VERSION 5.7 ;
BUSBITCHARS "[]" ;
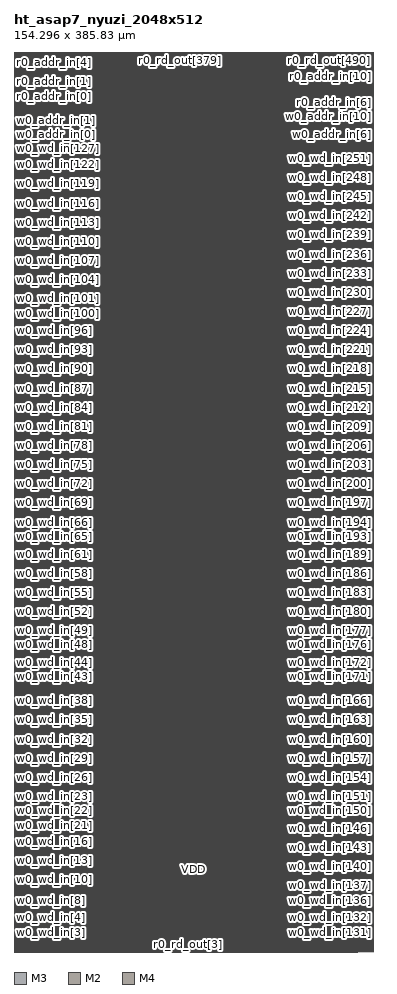
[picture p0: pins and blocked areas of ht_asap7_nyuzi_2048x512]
MACRO ht_asap7_nyuzi_2048x512
  FOREIGN ht_asap7_nyuzi_2048x512 0 0 ;
  SYMMETRY X Y R90 ;
  SIZE 154.296 BY 385.830 ;
  CLASS BLOCK ;
  PIN w0_wd_in[0]
    DIRECTION INPUT ;
    USE SIGNAL ;
    SHAPE ABUTMENT ;
    PORT
      LAYER M3 ;
      RECT 0.000 0.276 0.072 0.300 ;
    END
  END w0_wd_in[0]
  PIN w0_wd_in[1]
    DIRECTION INPUT ;
    USE SIGNAL ;
    SHAPE ABUTMENT ;
    PORT
      LAYER M3 ;
      RECT 0.000 3.012 0.072 3.036 ;
    END
  END w0_wd_in[1]
  PIN w0_wd_in[2]
    DIRECTION INPUT ;
    USE SIGNAL ;
    SHAPE ABUTMENT ;
    PORT
      LAYER M3 ;
      RECT 0.000 5.748 0.072 5.772 ;
    END
  END w0_wd_in[2]
  PIN w0_wd_in[3]
    DIRECTION INPUT ;
    USE SIGNAL ;
    SHAPE ABUTMENT ;
    PORT
      LAYER M3 ;
      RECT 0.000 8.484 0.072 8.508 ;
    END
  END w0_wd_in[3]
  PIN w0_wd_in[4]
    DIRECTION INPUT ;
    USE SIGNAL ;
    SHAPE ABUTMENT ;
    PORT
      LAYER M3 ;
      RECT 0.000 11.220 0.072 11.244 ;
    END
  END w0_wd_in[4]
  PIN w0_wd_in[5]
    DIRECTION INPUT ;
    USE SIGNAL ;
    SHAPE ABUTMENT ;
    PORT
      LAYER M3 ;
      RECT 0.000 13.956 0.072 13.980 ;
    END
  END w0_wd_in[5]
  PIN w0_wd_in[6]
    DIRECTION INPUT ;
    USE SIGNAL ;
    SHAPE ABUTMENT ;
    PORT
      LAYER M3 ;
      RECT 0.000 16.692 0.072 16.716 ;
    END
  END w0_wd_in[6]
  PIN w0_wd_in[7]
    DIRECTION INPUT ;
    USE SIGNAL ;
    SHAPE ABUTMENT ;
    PORT
      LAYER M3 ;
      RECT 0.000 19.428 0.072 19.452 ;
    END
  END w0_wd_in[7]
  PIN w0_wd_in[8]
    DIRECTION INPUT ;
    USE SIGNAL ;
    SHAPE ABUTMENT ;
    PORT
      LAYER M3 ;
      RECT 0.000 22.164 0.072 22.188 ;
    END
  END w0_wd_in[8]
  PIN w0_wd_in[9]
    DIRECTION INPUT ;
    USE SIGNAL ;
    SHAPE ABUTMENT ;
    PORT
      LAYER M3 ;
      RECT 0.000 24.900 0.072 24.924 ;
    END
  END w0_wd_in[9]
  PIN w0_wd_in[10]
    DIRECTION INPUT ;
    USE SIGNAL ;
    SHAPE ABUTMENT ;
    PORT
      LAYER M3 ;
      RECT 0.000 27.636 0.072 27.660 ;
    END
  END w0_wd_in[10]
  PIN w0_wd_in[11]
    DIRECTION INPUT ;
    USE SIGNAL ;
    SHAPE ABUTMENT ;
    PORT
      LAYER M3 ;
      RECT 0.000 30.372 0.072 30.396 ;
    END
  END w0_wd_in[11]
  PIN w0_wd_in[12]
    DIRECTION INPUT ;
    USE SIGNAL ;
    SHAPE ABUTMENT ;
    PORT
      LAYER M3 ;
      RECT 0.000 33.108 0.072 33.132 ;
    END
  END w0_wd_in[12]
  PIN w0_wd_in[13]
    DIRECTION INPUT ;
    USE SIGNAL ;
    SHAPE ABUTMENT ;
    PORT
      LAYER M3 ;
      RECT 0.000 35.844 0.072 35.868 ;
    END
  END w0_wd_in[13]
  PIN w0_wd_in[14]
    DIRECTION INPUT ;
    USE SIGNAL ;
    SHAPE ABUTMENT ;
    PORT
      LAYER M3 ;
      RECT 0.000 38.580 0.072 38.604 ;
    END
  END w0_wd_in[14]
  PIN w0_wd_in[15]
    DIRECTION INPUT ;
    USE SIGNAL ;
    SHAPE ABUTMENT ;
    PORT
      LAYER M3 ;
      RECT 0.000 41.316 0.072 41.340 ;
    END
  END w0_wd_in[15]
  PIN w0_wd_in[16]
    DIRECTION INPUT ;
    USE SIGNAL ;
    SHAPE ABUTMENT ;
    PORT
      LAYER M3 ;
      RECT 0.000 44.052 0.072 44.076 ;
    END
  END w0_wd_in[16]
  PIN w0_wd_in[17]
    DIRECTION INPUT ;
    USE SIGNAL ;
    SHAPE ABUTMENT ;
    PORT
      LAYER M3 ;
      RECT 0.000 46.788 0.072 46.812 ;
    END
  END w0_wd_in[17]
  PIN w0_wd_in[18]
    DIRECTION INPUT ;
    USE SIGNAL ;
    SHAPE ABUTMENT ;
    PORT
      LAYER M3 ;
      RECT 0.000 49.524 0.072 49.548 ;
    END
  END w0_wd_in[18]
  PIN w0_wd_in[19]
    DIRECTION INPUT ;
    USE SIGNAL ;
    SHAPE ABUTMENT ;
    PORT
      LAYER M3 ;
      RECT 0.000 52.260 0.072 52.284 ;
    END
  END w0_wd_in[19]
  PIN w0_wd_in[20]
    DIRECTION INPUT ;
    USE SIGNAL ;
    SHAPE ABUTMENT ;
    PORT
      LAYER M3 ;
      RECT 0.000 54.996 0.072 55.020 ;
    END
  END w0_wd_in[20]
  PIN w0_wd_in[21]
    DIRECTION INPUT ;
    USE SIGNAL ;
    SHAPE ABUTMENT ;
    PORT
      LAYER M3 ;
      RECT 0.000 57.732 0.072 57.756 ;
    END
  END w0_wd_in[21]
  PIN w0_wd_in[22]
    DIRECTION INPUT ;
    USE SIGNAL ;
    SHAPE ABUTMENT ;
    PORT
      LAYER M3 ;
      RECT 0.000 60.468 0.072 60.492 ;
    END
  END w0_wd_in[22]
  PIN w0_wd_in[23]
    DIRECTION INPUT ;
    USE SIGNAL ;
    SHAPE ABUTMENT ;
    PORT
      LAYER M3 ;
      RECT 0.000 63.204 0.072 63.228 ;
    END
  END w0_wd_in[23]
  PIN w0_wd_in[24]
    DIRECTION INPUT ;
    USE SIGNAL ;
    SHAPE ABUTMENT ;
    PORT
      LAYER M3 ;
      RECT 0.000 65.940 0.072 65.964 ;
    END
  END w0_wd_in[24]
  PIN w0_wd_in[25]
    DIRECTION INPUT ;
    USE SIGNAL ;
    SHAPE ABUTMENT ;
    PORT
      LAYER M3 ;
      RECT 0.000 68.676 0.072 68.700 ;
    END
  END w0_wd_in[25]
  PIN w0_wd_in[26]
    DIRECTION INPUT ;
    USE SIGNAL ;
    SHAPE ABUTMENT ;
    PORT
      LAYER M3 ;
      RECT 0.000 71.412 0.072 71.436 ;
    END
  END w0_wd_in[26]
  PIN w0_wd_in[27]
    DIRECTION INPUT ;
    USE SIGNAL ;
    SHAPE ABUTMENT ;
    PORT
      LAYER M3 ;
      RECT 0.000 74.148 0.072 74.172 ;
    END
  END w0_wd_in[27]
  PIN w0_wd_in[28]
    DIRECTION INPUT ;
    USE SIGNAL ;
    SHAPE ABUTMENT ;
    PORT
      LAYER M3 ;
      RECT 0.000 76.884 0.072 76.908 ;
    END
  END w0_wd_in[28]
  PIN w0_wd_in[29]
    DIRECTION INPUT ;
    USE SIGNAL ;
    SHAPE ABUTMENT ;
    PORT
      LAYER M3 ;
      RECT 0.000 79.620 0.072 79.644 ;
    END
  END w0_wd_in[29]
  PIN w0_wd_in[30]
    DIRECTION INPUT ;
    USE SIGNAL ;
    SHAPE ABUTMENT ;
    PORT
      LAYER M3 ;
      RECT 0.000 82.356 0.072 82.380 ;
    END
  END w0_wd_in[30]
  PIN w0_wd_in[31]
    DIRECTION INPUT ;
    USE SIGNAL ;
    SHAPE ABUTMENT ;
    PORT
      LAYER M3 ;
      RECT 0.000 85.092 0.072 85.116 ;
    END
  END w0_wd_in[31]
  PIN w0_wd_in[32]
    DIRECTION INPUT ;
    USE SIGNAL ;
    SHAPE ABUTMENT ;
    PORT
      LAYER M3 ;
      RECT 0.000 87.828 0.072 87.852 ;
    END
  END w0_wd_in[32]
  PIN w0_wd_in[33]
    DIRECTION INPUT ;
    USE SIGNAL ;
    SHAPE ABUTMENT ;
    PORT
      LAYER M3 ;
      RECT 0.000 90.564 0.072 90.588 ;
    END
  END w0_wd_in[33]
  PIN w0_wd_in[34]
    DIRECTION INPUT ;
    USE SIGNAL ;
    SHAPE ABUTMENT ;
    PORT
      LAYER M3 ;
      RECT 0.000 93.300 0.072 93.324 ;
    END
  END w0_wd_in[34]
  PIN w0_wd_in[35]
    DIRECTION INPUT ;
    USE SIGNAL ;
    SHAPE ABUTMENT ;
    PORT
      LAYER M3 ;
      RECT 0.000 96.036 0.072 96.060 ;
    END
  END w0_wd_in[35]
  PIN w0_wd_in[36]
    DIRECTION INPUT ;
    USE SIGNAL ;
    SHAPE ABUTMENT ;
    PORT
      LAYER M3 ;
      RECT 0.000 98.772 0.072 98.796 ;
    END
  END w0_wd_in[36]
  PIN w0_wd_in[37]
    DIRECTION INPUT ;
    USE SIGNAL ;
    SHAPE ABUTMENT ;
    PORT
      LAYER M3 ;
      RECT 0.000 101.508 0.072 101.532 ;
    END
  END w0_wd_in[37]
  PIN w0_wd_in[38]
    DIRECTION INPUT ;
    USE SIGNAL ;
    SHAPE ABUTMENT ;
    PORT
      LAYER M3 ;
      RECT 0.000 104.244 0.072 104.268 ;
    END
  END w0_wd_in[38]
  PIN w0_wd_in[39]
    DIRECTION INPUT ;
    USE SIGNAL ;
    SHAPE ABUTMENT ;
    PORT
      LAYER M3 ;
      RECT 0.000 106.980 0.072 107.004 ;
    END
  END w0_wd_in[39]
  PIN w0_wd_in[40]
    DIRECTION INPUT ;
    USE SIGNAL ;
    SHAPE ABUTMENT ;
    PORT
      LAYER M3 ;
      RECT 0.000 109.716 0.072 109.740 ;
    END
  END w0_wd_in[40]
  PIN w0_wd_in[41]
    DIRECTION INPUT ;
    USE SIGNAL ;
    SHAPE ABUTMENT ;
    PORT
      LAYER M3 ;
      RECT 0.000 112.452 0.072 112.476 ;
    END
  END w0_wd_in[41]
  PIN w0_wd_in[42]
    DIRECTION INPUT ;
    USE SIGNAL ;
    SHAPE ABUTMENT ;
    PORT
      LAYER M3 ;
      RECT 0.000 115.188 0.072 115.212 ;
    END
  END w0_wd_in[42]
  PIN w0_wd_in[43]
    DIRECTION INPUT ;
    USE SIGNAL ;
    SHAPE ABUTMENT ;
    PORT
      LAYER M3 ;
      RECT 0.000 117.924 0.072 117.948 ;
    END
  END w0_wd_in[43]
  PIN w0_wd_in[44]
    DIRECTION INPUT ;
    USE SIGNAL ;
    SHAPE ABUTMENT ;
    PORT
      LAYER M3 ;
      RECT 0.000 120.660 0.072 120.684 ;
    END
  END w0_wd_in[44]
  PIN w0_wd_in[45]
    DIRECTION INPUT ;
    USE SIGNAL ;
    SHAPE ABUTMENT ;
    PORT
      LAYER M3 ;
      RECT 0.000 123.396 0.072 123.420 ;
    END
  END w0_wd_in[45]
  PIN w0_wd_in[46]
    DIRECTION INPUT ;
    USE SIGNAL ;
    SHAPE ABUTMENT ;
    PORT
      LAYER M3 ;
      RECT 0.000 126.132 0.072 126.156 ;
    END
  END w0_wd_in[46]
  PIN w0_wd_in[47]
    DIRECTION INPUT ;
    USE SIGNAL ;
    SHAPE ABUTMENT ;
    PORT
      LAYER M3 ;
      RECT 0.000 128.868 0.072 128.892 ;
    END
  END w0_wd_in[47]
  PIN w0_wd_in[48]
    DIRECTION INPUT ;
    USE SIGNAL ;
    SHAPE ABUTMENT ;
    PORT
      LAYER M3 ;
      RECT 0.000 131.604 0.072 131.628 ;
    END
  END w0_wd_in[48]
  PIN w0_wd_in[49]
    DIRECTION INPUT ;
    USE SIGNAL ;
    SHAPE ABUTMENT ;
    PORT
      LAYER M3 ;
      RECT 0.000 134.340 0.072 134.364 ;
    END
  END w0_wd_in[49]
  PIN w0_wd_in[50]
    DIRECTION INPUT ;
    USE SIGNAL ;
    SHAPE ABUTMENT ;
    PORT
      LAYER M3 ;
      RECT 0.000 137.076 0.072 137.100 ;
    END
  END w0_wd_in[50]
  PIN w0_wd_in[51]
    DIRECTION INPUT ;
    USE SIGNAL ;
    SHAPE ABUTMENT ;
    PORT
      LAYER M3 ;
      RECT 0.000 139.812 0.072 139.836 ;
    END
  END w0_wd_in[51]
  PIN w0_wd_in[52]
    DIRECTION INPUT ;
    USE SIGNAL ;
    SHAPE ABUTMENT ;
    PORT
      LAYER M3 ;
      RECT 0.000 142.548 0.072 142.572 ;
    END
  END w0_wd_in[52]
  PIN w0_wd_in[53]
    DIRECTION INPUT ;
    USE SIGNAL ;
    SHAPE ABUTMENT ;
    PORT
      LAYER M3 ;
      RECT 0.000 145.284 0.072 145.308 ;
    END
  END w0_wd_in[53]
  PIN w0_wd_in[54]
    DIRECTION INPUT ;
    USE SIGNAL ;
    SHAPE ABUTMENT ;
    PORT
      LAYER M3 ;
      RECT 0.000 148.020 0.072 148.044 ;
    END
  END w0_wd_in[54]
  PIN w0_wd_in[55]
    DIRECTION INPUT ;
    USE SIGNAL ;
    SHAPE ABUTMENT ;
    PORT
      LAYER M3 ;
      RECT 0.000 150.756 0.072 150.780 ;
    END
  END w0_wd_in[55]
  PIN w0_wd_in[56]
    DIRECTION INPUT ;
    USE SIGNAL ;
    SHAPE ABUTMENT ;
    PORT
      LAYER M3 ;
      RECT 0.000 153.492 0.072 153.516 ;
    END
  END w0_wd_in[56]
  PIN w0_wd_in[57]
    DIRECTION INPUT ;
    USE SIGNAL ;
    SHAPE ABUTMENT ;
    PORT
      LAYER M3 ;
      RECT 0.000 156.228 0.072 156.252 ;
    END
  END w0_wd_in[57]
  PIN w0_wd_in[58]
    DIRECTION INPUT ;
    USE SIGNAL ;
    SHAPE ABUTMENT ;
    PORT
      LAYER M3 ;
      RECT 0.000 158.964 0.072 158.988 ;
    END
  END w0_wd_in[58]
  PIN w0_wd_in[59]
    DIRECTION INPUT ;
    USE SIGNAL ;
    SHAPE ABUTMENT ;
    PORT
      LAYER M3 ;
      RECT 0.000 161.700 0.072 161.724 ;
    END
  END w0_wd_in[59]
  PIN w0_wd_in[60]
    DIRECTION INPUT ;
    USE SIGNAL ;
    SHAPE ABUTMENT ;
    PORT
      LAYER M3 ;
      RECT 0.000 164.436 0.072 164.460 ;
    END
  END w0_wd_in[60]
  PIN w0_wd_in[61]
    DIRECTION INPUT ;
    USE SIGNAL ;
    SHAPE ABUTMENT ;
    PORT
      LAYER M3 ;
      RECT 0.000 167.172 0.072 167.196 ;
    END
  END w0_wd_in[61]
  PIN w0_wd_in[62]
    DIRECTION INPUT ;
    USE SIGNAL ;
    SHAPE ABUTMENT ;
    PORT
      LAYER M3 ;
      RECT 0.000 169.908 0.072 169.932 ;
    END
  END w0_wd_in[62]
  PIN w0_wd_in[63]
    DIRECTION INPUT ;
    USE SIGNAL ;
    SHAPE ABUTMENT ;
    PORT
      LAYER M3 ;
      RECT 0.000 172.644 0.072 172.668 ;
    END
  END w0_wd_in[63]
  PIN w0_wd_in[64]
    DIRECTION INPUT ;
    USE SIGNAL ;
    SHAPE ABUTMENT ;
    PORT
      LAYER M3 ;
      RECT 0.000 175.380 0.072 175.404 ;
    END
  END w0_wd_in[64]
  PIN w0_wd_in[65]
    DIRECTION INPUT ;
    USE SIGNAL ;
    SHAPE ABUTMENT ;
    PORT
      LAYER M3 ;
      RECT 0.000 178.116 0.072 178.140 ;
    END
  END w0_wd_in[65]
  PIN w0_wd_in[66]
    DIRECTION INPUT ;
    USE SIGNAL ;
    SHAPE ABUTMENT ;
    PORT
      LAYER M3 ;
      RECT 0.000 180.852 0.072 180.876 ;
    END
  END w0_wd_in[66]
  PIN w0_wd_in[67]
    DIRECTION INPUT ;
    USE SIGNAL ;
    SHAPE ABUTMENT ;
    PORT
      LAYER M3 ;
      RECT 0.000 183.588 0.072 183.612 ;
    END
  END w0_wd_in[67]
  PIN w0_wd_in[68]
    DIRECTION INPUT ;
    USE SIGNAL ;
    SHAPE ABUTMENT ;
    PORT
      LAYER M3 ;
      RECT 0.000 186.324 0.072 186.348 ;
    END
  END w0_wd_in[68]
  PIN w0_wd_in[69]
    DIRECTION INPUT ;
    USE SIGNAL ;
    SHAPE ABUTMENT ;
    PORT
      LAYER M3 ;
      RECT 0.000 189.060 0.072 189.084 ;
    END
  END w0_wd_in[69]
  PIN w0_wd_in[70]
    DIRECTION INPUT ;
    USE SIGNAL ;
    SHAPE ABUTMENT ;
    PORT
      LAYER M3 ;
      RECT 0.000 191.796 0.072 191.820 ;
    END
  END w0_wd_in[70]
  PIN w0_wd_in[71]
    DIRECTION INPUT ;
    USE SIGNAL ;
    SHAPE ABUTMENT ;
    PORT
      LAYER M3 ;
      RECT 0.000 194.532 0.072 194.556 ;
    END
  END w0_wd_in[71]
  PIN w0_wd_in[72]
    DIRECTION INPUT ;
    USE SIGNAL ;
    SHAPE ABUTMENT ;
    PORT
      LAYER M3 ;
      RECT 0.000 197.268 0.072 197.292 ;
    END
  END w0_wd_in[72]
  PIN w0_wd_in[73]
    DIRECTION INPUT ;
    USE SIGNAL ;
    SHAPE ABUTMENT ;
    PORT
      LAYER M3 ;
      RECT 0.000 200.004 0.072 200.028 ;
    END
  END w0_wd_in[73]
  PIN w0_wd_in[74]
    DIRECTION INPUT ;
    USE SIGNAL ;
    SHAPE ABUTMENT ;
    PORT
      LAYER M3 ;
      RECT 0.000 202.740 0.072 202.764 ;
    END
  END w0_wd_in[74]
  PIN w0_wd_in[75]
    DIRECTION INPUT ;
    USE SIGNAL ;
    SHAPE ABUTMENT ;
    PORT
      LAYER M3 ;
      RECT 0.000 205.476 0.072 205.500 ;
    END
  END w0_wd_in[75]
  PIN w0_wd_in[76]
    DIRECTION INPUT ;
    USE SIGNAL ;
    SHAPE ABUTMENT ;
    PORT
      LAYER M3 ;
      RECT 0.000 208.212 0.072 208.236 ;
    END
  END w0_wd_in[76]
  PIN w0_wd_in[77]
    DIRECTION INPUT ;
    USE SIGNAL ;
    SHAPE ABUTMENT ;
    PORT
      LAYER M3 ;
      RECT 0.000 210.948 0.072 210.972 ;
    END
  END w0_wd_in[77]
  PIN w0_wd_in[78]
    DIRECTION INPUT ;
    USE SIGNAL ;
    SHAPE ABUTMENT ;
    PORT
      LAYER M3 ;
      RECT 0.000 213.684 0.072 213.708 ;
    END
  END w0_wd_in[78]
  PIN w0_wd_in[79]
    DIRECTION INPUT ;
    USE SIGNAL ;
    SHAPE ABUTMENT ;
    PORT
      LAYER M3 ;
      RECT 0.000 216.420 0.072 216.444 ;
    END
  END w0_wd_in[79]
  PIN w0_wd_in[80]
    DIRECTION INPUT ;
    USE SIGNAL ;
    SHAPE ABUTMENT ;
    PORT
      LAYER M3 ;
      RECT 0.000 219.156 0.072 219.180 ;
    END
  END w0_wd_in[80]
  PIN w0_wd_in[81]
    DIRECTION INPUT ;
    USE SIGNAL ;
    SHAPE ABUTMENT ;
    PORT
      LAYER M3 ;
      RECT 0.000 221.892 0.072 221.916 ;
    END
  END w0_wd_in[81]
  PIN w0_wd_in[82]
    DIRECTION INPUT ;
    USE SIGNAL ;
    SHAPE ABUTMENT ;
    PORT
      LAYER M3 ;
      RECT 0.000 224.628 0.072 224.652 ;
    END
  END w0_wd_in[82]
  PIN w0_wd_in[83]
    DIRECTION INPUT ;
    USE SIGNAL ;
    SHAPE ABUTMENT ;
    PORT
      LAYER M3 ;
      RECT 0.000 227.364 0.072 227.388 ;
    END
  END w0_wd_in[83]
  PIN w0_wd_in[84]
    DIRECTION INPUT ;
    USE SIGNAL ;
    SHAPE ABUTMENT ;
    PORT
      LAYER M3 ;
      RECT 0.000 230.100 0.072 230.124 ;
    END
  END w0_wd_in[84]
  PIN w0_wd_in[85]
    DIRECTION INPUT ;
    USE SIGNAL ;
    SHAPE ABUTMENT ;
    PORT
      LAYER M3 ;
      RECT 0.000 232.836 0.072 232.860 ;
    END
  END w0_wd_in[85]
  PIN w0_wd_in[86]
    DIRECTION INPUT ;
    USE SIGNAL ;
    SHAPE ABUTMENT ;
    PORT
      LAYER M3 ;
      RECT 0.000 235.572 0.072 235.596 ;
    END
  END w0_wd_in[86]
  PIN w0_wd_in[87]
    DIRECTION INPUT ;
    USE SIGNAL ;
    SHAPE ABUTMENT ;
    PORT
      LAYER M3 ;
      RECT 0.000 238.308 0.072 238.332 ;
    END
  END w0_wd_in[87]
  PIN w0_wd_in[88]
    DIRECTION INPUT ;
    USE SIGNAL ;
    SHAPE ABUTMENT ;
    PORT
      LAYER M3 ;
      RECT 0.000 241.044 0.072 241.068 ;
    END
  END w0_wd_in[88]
  PIN w0_wd_in[89]
    DIRECTION INPUT ;
    USE SIGNAL ;
    SHAPE ABUTMENT ;
    PORT
      LAYER M3 ;
      RECT 0.000 243.780 0.072 243.804 ;
    END
  END w0_wd_in[89]
  PIN w0_wd_in[90]
    DIRECTION INPUT ;
    USE SIGNAL ;
    SHAPE ABUTMENT ;
    PORT
      LAYER M3 ;
      RECT 0.000 246.516 0.072 246.540 ;
    END
  END w0_wd_in[90]
  PIN w0_wd_in[91]
    DIRECTION INPUT ;
    USE SIGNAL ;
    SHAPE ABUTMENT ;
    PORT
      LAYER M3 ;
      RECT 0.000 249.252 0.072 249.276 ;
    END
  END w0_wd_in[91]
  PIN w0_wd_in[92]
    DIRECTION INPUT ;
    USE SIGNAL ;
    SHAPE ABUTMENT ;
    PORT
      LAYER M3 ;
      RECT 0.000 251.988 0.072 252.012 ;
    END
  END w0_wd_in[92]
  PIN w0_wd_in[93]
    DIRECTION INPUT ;
    USE SIGNAL ;
    SHAPE ABUTMENT ;
    PORT
      LAYER M3 ;
      RECT 0.000 254.724 0.072 254.748 ;
    END
  END w0_wd_in[93]
  PIN w0_wd_in[94]
    DIRECTION INPUT ;
    USE SIGNAL ;
    SHAPE ABUTMENT ;
    PORT
      LAYER M3 ;
      RECT 0.000 257.460 0.072 257.484 ;
    END
  END w0_wd_in[94]
  PIN w0_wd_in[95]
    DIRECTION INPUT ;
    USE SIGNAL ;
    SHAPE ABUTMENT ;
    PORT
      LAYER M3 ;
      RECT 0.000 260.196 0.072 260.220 ;
    END
  END w0_wd_in[95]
  PIN w0_wd_in[96]
    DIRECTION INPUT ;
    USE SIGNAL ;
    SHAPE ABUTMENT ;
    PORT
      LAYER M3 ;
      RECT 0.000 262.932 0.072 262.956 ;
    END
  END w0_wd_in[96]
  PIN w0_wd_in[97]
    DIRECTION INPUT ;
    USE SIGNAL ;
    SHAPE ABUTMENT ;
    PORT
      LAYER M3 ;
      RECT 0.000 265.668 0.072 265.692 ;
    END
  END w0_wd_in[97]
  PIN w0_wd_in[98]
    DIRECTION INPUT ;
    USE SIGNAL ;
    SHAPE ABUTMENT ;
    PORT
      LAYER M3 ;
      RECT 0.000 268.404 0.072 268.428 ;
    END
  END w0_wd_in[98]
  PIN w0_wd_in[99]
    DIRECTION INPUT ;
    USE SIGNAL ;
    SHAPE ABUTMENT ;
    PORT
      LAYER M3 ;
      RECT 0.000 271.140 0.072 271.164 ;
    END
  END w0_wd_in[99]
  PIN w0_wd_in[100]
    DIRECTION INPUT ;
    USE SIGNAL ;
    SHAPE ABUTMENT ;
    PORT
      LAYER M3 ;
      RECT 0.000 273.876 0.072 273.900 ;
    END
  END w0_wd_in[100]
  PIN w0_wd_in[101]
    DIRECTION INPUT ;
    USE SIGNAL ;
    SHAPE ABUTMENT ;
    PORT
      LAYER M3 ;
      RECT 0.000 276.612 0.072 276.636 ;
    END
  END w0_wd_in[101]
  PIN w0_wd_in[102]
    DIRECTION INPUT ;
    USE SIGNAL ;
    SHAPE ABUTMENT ;
    PORT
      LAYER M3 ;
      RECT 0.000 279.348 0.072 279.372 ;
    END
  END w0_wd_in[102]
  PIN w0_wd_in[103]
    DIRECTION INPUT ;
    USE SIGNAL ;
    SHAPE ABUTMENT ;
    PORT
      LAYER M3 ;
      RECT 0.000 282.084 0.072 282.108 ;
    END
  END w0_wd_in[103]
  PIN w0_wd_in[104]
    DIRECTION INPUT ;
    USE SIGNAL ;
    SHAPE ABUTMENT ;
    PORT
      LAYER M3 ;
      RECT 0.000 284.820 0.072 284.844 ;
    END
  END w0_wd_in[104]
  PIN w0_wd_in[105]
    DIRECTION INPUT ;
    USE SIGNAL ;
    SHAPE ABUTMENT ;
    PORT
      LAYER M3 ;
      RECT 0.000 287.556 0.072 287.580 ;
    END
  END w0_wd_in[105]
  PIN w0_wd_in[106]
    DIRECTION INPUT ;
    USE SIGNAL ;
    SHAPE ABUTMENT ;
    PORT
      LAYER M3 ;
      RECT 0.000 290.292 0.072 290.316 ;
    END
  END w0_wd_in[106]
  PIN w0_wd_in[107]
    DIRECTION INPUT ;
    USE SIGNAL ;
    SHAPE ABUTMENT ;
    PORT
      LAYER M3 ;
      RECT 0.000 293.028 0.072 293.052 ;
    END
  END w0_wd_in[107]
  PIN w0_wd_in[108]
    DIRECTION INPUT ;
    USE SIGNAL ;
    SHAPE ABUTMENT ;
    PORT
      LAYER M3 ;
      RECT 0.000 295.764 0.072 295.788 ;
    END
  END w0_wd_in[108]
  PIN w0_wd_in[109]
    DIRECTION INPUT ;
    USE SIGNAL ;
    SHAPE ABUTMENT ;
    PORT
      LAYER M3 ;
      RECT 0.000 298.500 0.072 298.524 ;
    END
  END w0_wd_in[109]
  PIN w0_wd_in[110]
    DIRECTION INPUT ;
    USE SIGNAL ;
    SHAPE ABUTMENT ;
    PORT
      LAYER M3 ;
      RECT 0.000 301.236 0.072 301.260 ;
    END
  END w0_wd_in[110]
  PIN w0_wd_in[111]
    DIRECTION INPUT ;
    USE SIGNAL ;
    SHAPE ABUTMENT ;
    PORT
      LAYER M3 ;
      RECT 0.000 303.972 0.072 303.996 ;
    END
  END w0_wd_in[111]
  PIN w0_wd_in[112]
    DIRECTION INPUT ;
    USE SIGNAL ;
    SHAPE ABUTMENT ;
    PORT
      LAYER M3 ;
      RECT 0.000 306.708 0.072 306.732 ;
    END
  END w0_wd_in[112]
  PIN w0_wd_in[113]
    DIRECTION INPUT ;
    USE SIGNAL ;
    SHAPE ABUTMENT ;
    PORT
      LAYER M3 ;
      RECT 0.000 309.444 0.072 309.468 ;
    END
  END w0_wd_in[113]
  PIN w0_wd_in[114]
    DIRECTION INPUT ;
    USE SIGNAL ;
    SHAPE ABUTMENT ;
    PORT
      LAYER M3 ;
      RECT 0.000 312.180 0.072 312.204 ;
    END
  END w0_wd_in[114]
  PIN w0_wd_in[115]
    DIRECTION INPUT ;
    USE SIGNAL ;
    SHAPE ABUTMENT ;
    PORT
      LAYER M3 ;
      RECT 0.000 314.916 0.072 314.940 ;
    END
  END w0_wd_in[115]
  PIN w0_wd_in[116]
    DIRECTION INPUT ;
    USE SIGNAL ;
    SHAPE ABUTMENT ;
    PORT
      LAYER M3 ;
      RECT 0.000 317.652 0.072 317.676 ;
    END
  END w0_wd_in[116]
  PIN w0_wd_in[117]
    DIRECTION INPUT ;
    USE SIGNAL ;
    SHAPE ABUTMENT ;
    PORT
      LAYER M3 ;
      RECT 0.000 320.388 0.072 320.412 ;
    END
  END w0_wd_in[117]
  PIN w0_wd_in[118]
    DIRECTION INPUT ;
    USE SIGNAL ;
    SHAPE ABUTMENT ;
    PORT
      LAYER M3 ;
      RECT 0.000 323.124 0.072 323.148 ;
    END
  END w0_wd_in[118]
  PIN w0_wd_in[119]
    DIRECTION INPUT ;
    USE SIGNAL ;
    SHAPE ABUTMENT ;
    PORT
      LAYER M3 ;
      RECT 0.000 325.860 0.072 325.884 ;
    END
  END w0_wd_in[119]
  PIN w0_wd_in[120]
    DIRECTION INPUT ;
    USE SIGNAL ;
    SHAPE ABUTMENT ;
    PORT
      LAYER M3 ;
      RECT 0.000 328.596 0.072 328.620 ;
    END
  END w0_wd_in[120]
  PIN w0_wd_in[121]
    DIRECTION INPUT ;
    USE SIGNAL ;
    SHAPE ABUTMENT ;
    PORT
      LAYER M3 ;
      RECT 0.000 331.332 0.072 331.356 ;
    END
  END w0_wd_in[121]
  PIN w0_wd_in[122]
    DIRECTION INPUT ;
    USE SIGNAL ;
    SHAPE ABUTMENT ;
    PORT
      LAYER M3 ;
      RECT 0.000 334.068 0.072 334.092 ;
    END
  END w0_wd_in[122]
  PIN w0_wd_in[123]
    DIRECTION INPUT ;
    USE SIGNAL ;
    SHAPE ABUTMENT ;
    PORT
      LAYER M3 ;
      RECT 0.000 336.804 0.072 336.828 ;
    END
  END w0_wd_in[123]
  PIN w0_wd_in[124]
    DIRECTION INPUT ;
    USE SIGNAL ;
    SHAPE ABUTMENT ;
    PORT
      LAYER M3 ;
      RECT 0.000 339.540 0.072 339.564 ;
    END
  END w0_wd_in[124]
  PIN w0_wd_in[125]
    DIRECTION INPUT ;
    USE SIGNAL ;
    SHAPE ABUTMENT ;
    PORT
      LAYER M3 ;
      RECT 0.000 342.276 0.072 342.300 ;
    END
  END w0_wd_in[125]
  PIN w0_wd_in[126]
    DIRECTION INPUT ;
    USE SIGNAL ;
    SHAPE ABUTMENT ;
    PORT
      LAYER M3 ;
      RECT 0.000 345.012 0.072 345.036 ;
    END
  END w0_wd_in[126]
  PIN w0_wd_in[127]
    DIRECTION INPUT ;
    USE SIGNAL ;
    SHAPE ABUTMENT ;
    PORT
      LAYER M3 ;
      RECT 0.000 347.748 0.072 347.772 ;
    END
  END w0_wd_in[127]
  PIN w0_wd_in[128]
    DIRECTION INPUT ;
    USE SIGNAL ;
    SHAPE ABUTMENT ;
    PORT
      LAYER M3 ;
      RECT 154.224 0.276 154.296 0.300 ;
    END
  END w0_wd_in[128]
  PIN w0_wd_in[129]
    DIRECTION INPUT ;
    USE SIGNAL ;
    SHAPE ABUTMENT ;
    PORT
      LAYER M3 ;
      RECT 154.224 3.012 154.296 3.036 ;
    END
  END w0_wd_in[129]
  PIN w0_wd_in[130]
    DIRECTION INPUT ;
    USE SIGNAL ;
    SHAPE ABUTMENT ;
    PORT
      LAYER M3 ;
      RECT 154.224 5.748 154.296 5.772 ;
    END
  END w0_wd_in[130]
  PIN w0_wd_in[131]
    DIRECTION INPUT ;
    USE SIGNAL ;
    SHAPE ABUTMENT ;
    PORT
      LAYER M3 ;
      RECT 154.224 8.484 154.296 8.508 ;
    END
  END w0_wd_in[131]
  PIN w0_wd_in[132]
    DIRECTION INPUT ;
    USE SIGNAL ;
    SHAPE ABUTMENT ;
    PORT
      LAYER M3 ;
      RECT 154.224 11.220 154.296 11.244 ;
    END
  END w0_wd_in[132]
  PIN w0_wd_in[133]
    DIRECTION INPUT ;
    USE SIGNAL ;
    SHAPE ABUTMENT ;
    PORT
      LAYER M3 ;
      RECT 154.224 13.956 154.296 13.980 ;
    END
  END w0_wd_in[133]
  PIN w0_wd_in[134]
    DIRECTION INPUT ;
    USE SIGNAL ;
    SHAPE ABUTMENT ;
    PORT
      LAYER M3 ;
      RECT 154.224 16.692 154.296 16.716 ;
    END
  END w0_wd_in[134]
  PIN w0_wd_in[135]
    DIRECTION INPUT ;
    USE SIGNAL ;
    SHAPE ABUTMENT ;
    PORT
      LAYER M3 ;
      RECT 154.224 19.428 154.296 19.452 ;
    END
  END w0_wd_in[135]
  PIN w0_wd_in[136]
    DIRECTION INPUT ;
    USE SIGNAL ;
    SHAPE ABUTMENT ;
    PORT
      LAYER M3 ;
      RECT 154.224 22.164 154.296 22.188 ;
    END
  END w0_wd_in[136]
  PIN w0_wd_in[137]
    DIRECTION INPUT ;
    USE SIGNAL ;
    SHAPE ABUTMENT ;
    PORT
      LAYER M3 ;
      RECT 154.224 24.900 154.296 24.924 ;
    END
  END w0_wd_in[137]
  PIN w0_wd_in[138]
    DIRECTION INPUT ;
    USE SIGNAL ;
    SHAPE ABUTMENT ;
    PORT
      LAYER M3 ;
      RECT 154.224 27.636 154.296 27.660 ;
    END
  END w0_wd_in[138]
  PIN w0_wd_in[139]
    DIRECTION INPUT ;
    USE SIGNAL ;
    SHAPE ABUTMENT ;
    PORT
      LAYER M3 ;
      RECT 154.224 30.372 154.296 30.396 ;
    END
  END w0_wd_in[139]
  PIN w0_wd_in[140]
    DIRECTION INPUT ;
    USE SIGNAL ;
    SHAPE ABUTMENT ;
    PORT
      LAYER M3 ;
      RECT 154.224 33.108 154.296 33.132 ;
    END
  END w0_wd_in[140]
  PIN w0_wd_in[141]
    DIRECTION INPUT ;
    USE SIGNAL ;
    SHAPE ABUTMENT ;
    PORT
      LAYER M3 ;
      RECT 154.224 35.844 154.296 35.868 ;
    END
  END w0_wd_in[141]
  PIN w0_wd_in[142]
    DIRECTION INPUT ;
    USE SIGNAL ;
    SHAPE ABUTMENT ;
    PORT
      LAYER M3 ;
      RECT 154.224 38.580 154.296 38.604 ;
    END
  END w0_wd_in[142]
  PIN w0_wd_in[143]
    DIRECTION INPUT ;
    USE SIGNAL ;
    SHAPE ABUTMENT ;
    PORT
      LAYER M3 ;
      RECT 154.224 41.316 154.296 41.340 ;
    END
  END w0_wd_in[143]
  PIN w0_wd_in[144]
    DIRECTION INPUT ;
    USE SIGNAL ;
    SHAPE ABUTMENT ;
    PORT
      LAYER M3 ;
      RECT 154.224 44.052 154.296 44.076 ;
    END
  END w0_wd_in[144]
  PIN w0_wd_in[145]
    DIRECTION INPUT ;
    USE SIGNAL ;
    SHAPE ABUTMENT ;
    PORT
      LAYER M3 ;
      RECT 154.224 46.788 154.296 46.812 ;
    END
  END w0_wd_in[145]
  PIN w0_wd_in[146]
    DIRECTION INPUT ;
    USE SIGNAL ;
    SHAPE ABUTMENT ;
    PORT
      LAYER M3 ;
      RECT 154.224 49.524 154.296 49.548 ;
    END
  END w0_wd_in[146]
  PIN w0_wd_in[147]
    DIRECTION INPUT ;
    USE SIGNAL ;
    SHAPE ABUTMENT ;
    PORT
      LAYER M3 ;
      RECT 154.224 52.260 154.296 52.284 ;
    END
  END w0_wd_in[147]
  PIN w0_wd_in[148]
    DIRECTION INPUT ;
    USE SIGNAL ;
    SHAPE ABUTMENT ;
    PORT
      LAYER M3 ;
      RECT 154.224 54.996 154.296 55.020 ;
    END
  END w0_wd_in[148]
  PIN w0_wd_in[149]
    DIRECTION INPUT ;
    USE SIGNAL ;
    SHAPE ABUTMENT ;
    PORT
      LAYER M3 ;
      RECT 154.224 57.732 154.296 57.756 ;
    END
  END w0_wd_in[149]
  PIN w0_wd_in[150]
    DIRECTION INPUT ;
    USE SIGNAL ;
    SHAPE ABUTMENT ;
    PORT
      LAYER M3 ;
      RECT 154.224 60.468 154.296 60.492 ;
    END
  END w0_wd_in[150]
  PIN w0_wd_in[151]
    DIRECTION INPUT ;
    USE SIGNAL ;
    SHAPE ABUTMENT ;
    PORT
      LAYER M3 ;
      RECT 154.224 63.204 154.296 63.228 ;
    END
  END w0_wd_in[151]
  PIN w0_wd_in[152]
    DIRECTION INPUT ;
    USE SIGNAL ;
    SHAPE ABUTMENT ;
    PORT
      LAYER M3 ;
      RECT 154.224 65.940 154.296 65.964 ;
    END
  END w0_wd_in[152]
  PIN w0_wd_in[153]
    DIRECTION INPUT ;
    USE SIGNAL ;
    SHAPE ABUTMENT ;
    PORT
      LAYER M3 ;
      RECT 154.224 68.676 154.296 68.700 ;
    END
  END w0_wd_in[153]
  PIN w0_wd_in[154]
    DIRECTION INPUT ;
    USE SIGNAL ;
    SHAPE ABUTMENT ;
    PORT
      LAYER M3 ;
      RECT 154.224 71.412 154.296 71.436 ;
    END
  END w0_wd_in[154]
  PIN w0_wd_in[155]
    DIRECTION INPUT ;
    USE SIGNAL ;
    SHAPE ABUTMENT ;
    PORT
      LAYER M3 ;
      RECT 154.224 74.148 154.296 74.172 ;
    END
  END w0_wd_in[155]
  PIN w0_wd_in[156]
    DIRECTION INPUT ;
    USE SIGNAL ;
    SHAPE ABUTMENT ;
    PORT
      LAYER M3 ;
      RECT 154.224 76.884 154.296 76.908 ;
    END
  END w0_wd_in[156]
  PIN w0_wd_in[157]
    DIRECTION INPUT ;
    USE SIGNAL ;
    SHAPE ABUTMENT ;
    PORT
      LAYER M3 ;
      RECT 154.224 79.620 154.296 79.644 ;
    END
  END w0_wd_in[157]
  PIN w0_wd_in[158]
    DIRECTION INPUT ;
    USE SIGNAL ;
    SHAPE ABUTMENT ;
    PORT
      LAYER M3 ;
      RECT 154.224 82.356 154.296 82.380 ;
    END
  END w0_wd_in[158]
  PIN w0_wd_in[159]
    DIRECTION INPUT ;
    USE SIGNAL ;
    SHAPE ABUTMENT ;
    PORT
      LAYER M3 ;
      RECT 154.224 85.092 154.296 85.116 ;
    END
  END w0_wd_in[159]
  PIN w0_wd_in[160]
    DIRECTION INPUT ;
    USE SIGNAL ;
    SHAPE ABUTMENT ;
    PORT
      LAYER M3 ;
      RECT 154.224 87.828 154.296 87.852 ;
    END
  END w0_wd_in[160]
  PIN w0_wd_in[161]
    DIRECTION INPUT ;
    USE SIGNAL ;
    SHAPE ABUTMENT ;
    PORT
      LAYER M3 ;
      RECT 154.224 90.564 154.296 90.588 ;
    END
  END w0_wd_in[161]
  PIN w0_wd_in[162]
    DIRECTION INPUT ;
    USE SIGNAL ;
    SHAPE ABUTMENT ;
    PORT
      LAYER M3 ;
      RECT 154.224 93.300 154.296 93.324 ;
    END
  END w0_wd_in[162]
  PIN w0_wd_in[163]
    DIRECTION INPUT ;
    USE SIGNAL ;
    SHAPE ABUTMENT ;
    PORT
      LAYER M3 ;
      RECT 154.224 96.036 154.296 96.060 ;
    END
  END w0_wd_in[163]
  PIN w0_wd_in[164]
    DIRECTION INPUT ;
    USE SIGNAL ;
    SHAPE ABUTMENT ;
    PORT
      LAYER M3 ;
      RECT 154.224 98.772 154.296 98.796 ;
    END
  END w0_wd_in[164]
  PIN w0_wd_in[165]
    DIRECTION INPUT ;
    USE SIGNAL ;
    SHAPE ABUTMENT ;
    PORT
      LAYER M3 ;
      RECT 154.224 101.508 154.296 101.532 ;
    END
  END w0_wd_in[165]
  PIN w0_wd_in[166]
    DIRECTION INPUT ;
    USE SIGNAL ;
    SHAPE ABUTMENT ;
    PORT
      LAYER M3 ;
      RECT 154.224 104.244 154.296 104.268 ;
    END
  END w0_wd_in[166]
  PIN w0_wd_in[167]
    DIRECTION INPUT ;
    USE SIGNAL ;
    SHAPE ABUTMENT ;
    PORT
      LAYER M3 ;
      RECT 154.224 106.980 154.296 107.004 ;
    END
  END w0_wd_in[167]
  PIN w0_wd_in[168]
    DIRECTION INPUT ;
    USE SIGNAL ;
    SHAPE ABUTMENT ;
    PORT
      LAYER M3 ;
      RECT 154.224 109.716 154.296 109.740 ;
    END
  END w0_wd_in[168]
  PIN w0_wd_in[169]
    DIRECTION INPUT ;
    USE SIGNAL ;
    SHAPE ABUTMENT ;
    PORT
      LAYER M3 ;
      RECT 154.224 112.452 154.296 112.476 ;
    END
  END w0_wd_in[169]
  PIN w0_wd_in[170]
    DIRECTION INPUT ;
    USE SIGNAL ;
    SHAPE ABUTMENT ;
    PORT
      LAYER M3 ;
      RECT 154.224 115.188 154.296 115.212 ;
    END
  END w0_wd_in[170]
  PIN w0_wd_in[171]
    DIRECTION INPUT ;
    USE SIGNAL ;
    SHAPE ABUTMENT ;
    PORT
      LAYER M3 ;
      RECT 154.224 117.924 154.296 117.948 ;
    END
  END w0_wd_in[171]
  PIN w0_wd_in[172]
    DIRECTION INPUT ;
    USE SIGNAL ;
    SHAPE ABUTMENT ;
    PORT
      LAYER M3 ;
      RECT 154.224 120.660 154.296 120.684 ;
    END
  END w0_wd_in[172]
  PIN w0_wd_in[173]
    DIRECTION INPUT ;
    USE SIGNAL ;
    SHAPE ABUTMENT ;
    PORT
      LAYER M3 ;
      RECT 154.224 123.396 154.296 123.420 ;
    END
  END w0_wd_in[173]
  PIN w0_wd_in[174]
    DIRECTION INPUT ;
    USE SIGNAL ;
    SHAPE ABUTMENT ;
    PORT
      LAYER M3 ;
      RECT 154.224 126.132 154.296 126.156 ;
    END
  END w0_wd_in[174]
  PIN w0_wd_in[175]
    DIRECTION INPUT ;
    USE SIGNAL ;
    SHAPE ABUTMENT ;
    PORT
      LAYER M3 ;
      RECT 154.224 128.868 154.296 128.892 ;
    END
  END w0_wd_in[175]
  PIN w0_wd_in[176]
    DIRECTION INPUT ;
    USE SIGNAL ;
    SHAPE ABUTMENT ;
    PORT
      LAYER M3 ;
      RECT 154.224 131.604 154.296 131.628 ;
    END
  END w0_wd_in[176]
  PIN w0_wd_in[177]
    DIRECTION INPUT ;
    USE SIGNAL ;
    SHAPE ABUTMENT ;
    PORT
      LAYER M3 ;
      RECT 154.224 134.340 154.296 134.364 ;
    END
  END w0_wd_in[177]
  PIN w0_wd_in[178]
    DIRECTION INPUT ;
    USE SIGNAL ;
    SHAPE ABUTMENT ;
    PORT
      LAYER M3 ;
      RECT 154.224 137.076 154.296 137.100 ;
    END
  END w0_wd_in[178]
  PIN w0_wd_in[179]
    DIRECTION INPUT ;
    USE SIGNAL ;
    SHAPE ABUTMENT ;
    PORT
      LAYER M3 ;
      RECT 154.224 139.812 154.296 139.836 ;
    END
  END w0_wd_in[179]
  PIN w0_wd_in[180]
    DIRECTION INPUT ;
    USE SIGNAL ;
    SHAPE ABUTMENT ;
    PORT
      LAYER M3 ;
      RECT 154.224 142.548 154.296 142.572 ;
    END
  END w0_wd_in[180]
  PIN w0_wd_in[181]
    DIRECTION INPUT ;
    USE SIGNAL ;
    SHAPE ABUTMENT ;
    PORT
      LAYER M3 ;
      RECT 154.224 145.284 154.296 145.308 ;
    END
  END w0_wd_in[181]
  PIN w0_wd_in[182]
    DIRECTION INPUT ;
    USE SIGNAL ;
    SHAPE ABUTMENT ;
    PORT
      LAYER M3 ;
      RECT 154.224 148.020 154.296 148.044 ;
    END
  END w0_wd_in[182]
  PIN w0_wd_in[183]
    DIRECTION INPUT ;
    USE SIGNAL ;
    SHAPE ABUTMENT ;
    PORT
      LAYER M3 ;
      RECT 154.224 150.756 154.296 150.780 ;
    END
  END w0_wd_in[183]
  PIN w0_wd_in[184]
    DIRECTION INPUT ;
    USE SIGNAL ;
    SHAPE ABUTMENT ;
    PORT
      LAYER M3 ;
      RECT 154.224 153.492 154.296 153.516 ;
    END
  END w0_wd_in[184]
  PIN w0_wd_in[185]
    DIRECTION INPUT ;
    USE SIGNAL ;
    SHAPE ABUTMENT ;
    PORT
      LAYER M3 ;
      RECT 154.224 156.228 154.296 156.252 ;
    END
  END w0_wd_in[185]
  PIN w0_wd_in[186]
    DIRECTION INPUT ;
    USE SIGNAL ;
    SHAPE ABUTMENT ;
    PORT
      LAYER M3 ;
      RECT 154.224 158.964 154.296 158.988 ;
    END
  END w0_wd_in[186]
  PIN w0_wd_in[187]
    DIRECTION INPUT ;
    USE SIGNAL ;
    SHAPE ABUTMENT ;
    PORT
      LAYER M3 ;
      RECT 154.224 161.700 154.296 161.724 ;
    END
  END w0_wd_in[187]
  PIN w0_wd_in[188]
    DIRECTION INPUT ;
    USE SIGNAL ;
    SHAPE ABUTMENT ;
    PORT
      LAYER M3 ;
      RECT 154.224 164.436 154.296 164.460 ;
    END
  END w0_wd_in[188]
  PIN w0_wd_in[189]
    DIRECTION INPUT ;
    USE SIGNAL ;
    SHAPE ABUTMENT ;
    PORT
      LAYER M3 ;
      RECT 154.224 167.172 154.296 167.196 ;
    END
  END w0_wd_in[189]
  PIN w0_wd_in[190]
    DIRECTION INPUT ;
    USE SIGNAL ;
    SHAPE ABUTMENT ;
    PORT
      LAYER M3 ;
      RECT 154.224 169.908 154.296 169.932 ;
    END
  END w0_wd_in[190]
  PIN w0_wd_in[191]
    DIRECTION INPUT ;
    USE SIGNAL ;
    SHAPE ABUTMENT ;
    PORT
      LAYER M3 ;
      RECT 154.224 172.644 154.296 172.668 ;
    END
  END w0_wd_in[191]
  PIN w0_wd_in[192]
    DIRECTION INPUT ;
    USE SIGNAL ;
    SHAPE ABUTMENT ;
    PORT
      LAYER M3 ;
      RECT 154.224 175.380 154.296 175.404 ;
    END
  END w0_wd_in[192]
  PIN w0_wd_in[193]
    DIRECTION INPUT ;
    USE SIGNAL ;
    SHAPE ABUTMENT ;
    PORT
      LAYER M3 ;
      RECT 154.224 178.116 154.296 178.140 ;
    END
  END w0_wd_in[193]
  PIN w0_wd_in[194]
    DIRECTION INPUT ;
    USE SIGNAL ;
    SHAPE ABUTMENT ;
    PORT
      LAYER M3 ;
      RECT 154.224 180.852 154.296 180.876 ;
    END
  END w0_wd_in[194]
  PIN w0_wd_in[195]
    DIRECTION INPUT ;
    USE SIGNAL ;
    SHAPE ABUTMENT ;
    PORT
      LAYER M3 ;
      RECT 154.224 183.588 154.296 183.612 ;
    END
  END w0_wd_in[195]
  PIN w0_wd_in[196]
    DIRECTION INPUT ;
    USE SIGNAL ;
    SHAPE ABUTMENT ;
    PORT
      LAYER M3 ;
      RECT 154.224 186.324 154.296 186.348 ;
    END
  END w0_wd_in[196]
  PIN w0_wd_in[197]
    DIRECTION INPUT ;
    USE SIGNAL ;
    SHAPE ABUTMENT ;
    PORT
      LAYER M3 ;
      RECT 154.224 189.060 154.296 189.084 ;
    END
  END w0_wd_in[197]
  PIN w0_wd_in[198]
    DIRECTION INPUT ;
    USE SIGNAL ;
    SHAPE ABUTMENT ;
    PORT
      LAYER M3 ;
      RECT 154.224 191.796 154.296 191.820 ;
    END
  END w0_wd_in[198]
  PIN w0_wd_in[199]
    DIRECTION INPUT ;
    USE SIGNAL ;
    SHAPE ABUTMENT ;
    PORT
      LAYER M3 ;
      RECT 154.224 194.532 154.296 194.556 ;
    END
  END w0_wd_in[199]
  PIN w0_wd_in[200]
    DIRECTION INPUT ;
    USE SIGNAL ;
    SHAPE ABUTMENT ;
    PORT
      LAYER M3 ;
      RECT 154.224 197.268 154.296 197.292 ;
    END
  END w0_wd_in[200]
  PIN w0_wd_in[201]
    DIRECTION INPUT ;
    USE SIGNAL ;
    SHAPE ABUTMENT ;
    PORT
      LAYER M3 ;
      RECT 154.224 200.004 154.296 200.028 ;
    END
  END w0_wd_in[201]
  PIN w0_wd_in[202]
    DIRECTION INPUT ;
    USE SIGNAL ;
    SHAPE ABUTMENT ;
    PORT
      LAYER M3 ;
      RECT 154.224 202.740 154.296 202.764 ;
    END
  END w0_wd_in[202]
  PIN w0_wd_in[203]
    DIRECTION INPUT ;
    USE SIGNAL ;
    SHAPE ABUTMENT ;
    PORT
      LAYER M3 ;
      RECT 154.224 205.476 154.296 205.500 ;
    END
  END w0_wd_in[203]
  PIN w0_wd_in[204]
    DIRECTION INPUT ;
    USE SIGNAL ;
    SHAPE ABUTMENT ;
    PORT
      LAYER M3 ;
      RECT 154.224 208.212 154.296 208.236 ;
    END
  END w0_wd_in[204]
  PIN w0_wd_in[205]
    DIRECTION INPUT ;
    USE SIGNAL ;
    SHAPE ABUTMENT ;
    PORT
      LAYER M3 ;
      RECT 154.224 210.948 154.296 210.972 ;
    END
  END w0_wd_in[205]
  PIN w0_wd_in[206]
    DIRECTION INPUT ;
    USE SIGNAL ;
    SHAPE ABUTMENT ;
    PORT
      LAYER M3 ;
      RECT 154.224 213.684 154.296 213.708 ;
    END
  END w0_wd_in[206]
  PIN w0_wd_in[207]
    DIRECTION INPUT ;
    USE SIGNAL ;
    SHAPE ABUTMENT ;
    PORT
      LAYER M3 ;
      RECT 154.224 216.420 154.296 216.444 ;
    END
  END w0_wd_in[207]
  PIN w0_wd_in[208]
    DIRECTION INPUT ;
    USE SIGNAL ;
    SHAPE ABUTMENT ;
    PORT
      LAYER M3 ;
      RECT 154.224 219.156 154.296 219.180 ;
    END
  END w0_wd_in[208]
  PIN w0_wd_in[209]
    DIRECTION INPUT ;
    USE SIGNAL ;
    SHAPE ABUTMENT ;
    PORT
      LAYER M3 ;
      RECT 154.224 221.892 154.296 221.916 ;
    END
  END w0_wd_in[209]
  PIN w0_wd_in[210]
    DIRECTION INPUT ;
    USE SIGNAL ;
    SHAPE ABUTMENT ;
    PORT
      LAYER M3 ;
      RECT 154.224 224.628 154.296 224.652 ;
    END
  END w0_wd_in[210]
  PIN w0_wd_in[211]
    DIRECTION INPUT ;
    USE SIGNAL ;
    SHAPE ABUTMENT ;
    PORT
      LAYER M3 ;
      RECT 154.224 227.364 154.296 227.388 ;
    END
  END w0_wd_in[211]
  PIN w0_wd_in[212]
    DIRECTION INPUT ;
    USE SIGNAL ;
    SHAPE ABUTMENT ;
    PORT
      LAYER M3 ;
      RECT 154.224 230.100 154.296 230.124 ;
    END
  END w0_wd_in[212]
  PIN w0_wd_in[213]
    DIRECTION INPUT ;
    USE SIGNAL ;
    SHAPE ABUTMENT ;
    PORT
      LAYER M3 ;
      RECT 154.224 232.836 154.296 232.860 ;
    END
  END w0_wd_in[213]
  PIN w0_wd_in[214]
    DIRECTION INPUT ;
    USE SIGNAL ;
    SHAPE ABUTMENT ;
    PORT
      LAYER M3 ;
      RECT 154.224 235.572 154.296 235.596 ;
    END
  END w0_wd_in[214]
  PIN w0_wd_in[215]
    DIRECTION INPUT ;
    USE SIGNAL ;
    SHAPE ABUTMENT ;
    PORT
      LAYER M3 ;
      RECT 154.224 238.308 154.296 238.332 ;
    END
  END w0_wd_in[215]
  PIN w0_wd_in[216]
    DIRECTION INPUT ;
    USE SIGNAL ;
    SHAPE ABUTMENT ;
    PORT
      LAYER M3 ;
      RECT 154.224 241.044 154.296 241.068 ;
    END
  END w0_wd_in[216]
  PIN w0_wd_in[217]
    DIRECTION INPUT ;
    USE SIGNAL ;
    SHAPE ABUTMENT ;
    PORT
      LAYER M3 ;
      RECT 154.224 243.780 154.296 243.804 ;
    END
  END w0_wd_in[217]
  PIN w0_wd_in[218]
    DIRECTION INPUT ;
    USE SIGNAL ;
    SHAPE ABUTMENT ;
    PORT
      LAYER M3 ;
      RECT 154.224 246.516 154.296 246.540 ;
    END
  END w0_wd_in[218]
  PIN w0_wd_in[219]
    DIRECTION INPUT ;
    USE SIGNAL ;
    SHAPE ABUTMENT ;
    PORT
      LAYER M3 ;
      RECT 154.224 249.252 154.296 249.276 ;
    END
  END w0_wd_in[219]
  PIN w0_wd_in[220]
    DIRECTION INPUT ;
    USE SIGNAL ;
    SHAPE ABUTMENT ;
    PORT
      LAYER M3 ;
      RECT 154.224 251.988 154.296 252.012 ;
    END
  END w0_wd_in[220]
  PIN w0_wd_in[221]
    DIRECTION INPUT ;
    USE SIGNAL ;
    SHAPE ABUTMENT ;
    PORT
      LAYER M3 ;
      RECT 154.224 254.724 154.296 254.748 ;
    END
  END w0_wd_in[221]
  PIN w0_wd_in[222]
    DIRECTION INPUT ;
    USE SIGNAL ;
    SHAPE ABUTMENT ;
    PORT
      LAYER M3 ;
      RECT 154.224 257.460 154.296 257.484 ;
    END
  END w0_wd_in[222]
  PIN w0_wd_in[223]
    DIRECTION INPUT ;
    USE SIGNAL ;
    SHAPE ABUTMENT ;
    PORT
      LAYER M3 ;
      RECT 154.224 260.196 154.296 260.220 ;
    END
  END w0_wd_in[223]
  PIN w0_wd_in[224]
    DIRECTION INPUT ;
    USE SIGNAL ;
    SHAPE ABUTMENT ;
    PORT
      LAYER M3 ;
      RECT 154.224 262.932 154.296 262.956 ;
    END
  END w0_wd_in[224]
  PIN w0_wd_in[225]
    DIRECTION INPUT ;
    USE SIGNAL ;
    SHAPE ABUTMENT ;
    PORT
      LAYER M3 ;
      RECT 154.224 265.668 154.296 265.692 ;
    END
  END w0_wd_in[225]
  PIN w0_wd_in[226]
    DIRECTION INPUT ;
    USE SIGNAL ;
    SHAPE ABUTMENT ;
    PORT
      LAYER M3 ;
      RECT 154.224 268.404 154.296 268.428 ;
    END
  END w0_wd_in[226]
  PIN w0_wd_in[227]
    DIRECTION INPUT ;
    USE SIGNAL ;
    SHAPE ABUTMENT ;
    PORT
      LAYER M3 ;
      RECT 154.224 271.140 154.296 271.164 ;
    END
  END w0_wd_in[227]
  PIN w0_wd_in[228]
    DIRECTION INPUT ;
    USE SIGNAL ;
    SHAPE ABUTMENT ;
    PORT
      LAYER M3 ;
      RECT 154.224 273.876 154.296 273.900 ;
    END
  END w0_wd_in[228]
  PIN w0_wd_in[229]
    DIRECTION INPUT ;
    USE SIGNAL ;
    SHAPE ABUTMENT ;
    PORT
      LAYER M3 ;
      RECT 154.224 276.612 154.296 276.636 ;
    END
  END w0_wd_in[229]
  PIN w0_wd_in[230]
    DIRECTION INPUT ;
    USE SIGNAL ;
    SHAPE ABUTMENT ;
    PORT
      LAYER M3 ;
      RECT 154.224 279.348 154.296 279.372 ;
    END
  END w0_wd_in[230]
  PIN w0_wd_in[231]
    DIRECTION INPUT ;
    USE SIGNAL ;
    SHAPE ABUTMENT ;
    PORT
      LAYER M3 ;
      RECT 154.224 282.084 154.296 282.108 ;
    END
  END w0_wd_in[231]
  PIN w0_wd_in[232]
    DIRECTION INPUT ;
    USE SIGNAL ;
    SHAPE ABUTMENT ;
    PORT
      LAYER M3 ;
      RECT 154.224 284.820 154.296 284.844 ;
    END
  END w0_wd_in[232]
  PIN w0_wd_in[233]
    DIRECTION INPUT ;
    USE SIGNAL ;
    SHAPE ABUTMENT ;
    PORT
      LAYER M3 ;
      RECT 154.224 287.556 154.296 287.580 ;
    END
  END w0_wd_in[233]
  PIN w0_wd_in[234]
    DIRECTION INPUT ;
    USE SIGNAL ;
    SHAPE ABUTMENT ;
    PORT
      LAYER M3 ;
      RECT 154.224 290.292 154.296 290.316 ;
    END
  END w0_wd_in[234]
  PIN w0_wd_in[235]
    DIRECTION INPUT ;
    USE SIGNAL ;
    SHAPE ABUTMENT ;
    PORT
      LAYER M3 ;
      RECT 154.224 293.028 154.296 293.052 ;
    END
  END w0_wd_in[235]
  PIN w0_wd_in[236]
    DIRECTION INPUT ;
    USE SIGNAL ;
    SHAPE ABUTMENT ;
    PORT
      LAYER M3 ;
      RECT 154.224 295.764 154.296 295.788 ;
    END
  END w0_wd_in[236]
  PIN w0_wd_in[237]
    DIRECTION INPUT ;
    USE SIGNAL ;
    SHAPE ABUTMENT ;
    PORT
      LAYER M3 ;
      RECT 154.224 298.500 154.296 298.524 ;
    END
  END w0_wd_in[237]
  PIN w0_wd_in[238]
    DIRECTION INPUT ;
    USE SIGNAL ;
    SHAPE ABUTMENT ;
    PORT
      LAYER M3 ;
      RECT 154.224 301.236 154.296 301.260 ;
    END
  END w0_wd_in[238]
  PIN w0_wd_in[239]
    DIRECTION INPUT ;
    USE SIGNAL ;
    SHAPE ABUTMENT ;
    PORT
      LAYER M3 ;
      RECT 154.224 303.972 154.296 303.996 ;
    END
  END w0_wd_in[239]
  PIN w0_wd_in[240]
    DIRECTION INPUT ;
    USE SIGNAL ;
    SHAPE ABUTMENT ;
    PORT
      LAYER M3 ;
      RECT 154.224 306.708 154.296 306.732 ;
    END
  END w0_wd_in[240]
  PIN w0_wd_in[241]
    DIRECTION INPUT ;
    USE SIGNAL ;
    SHAPE ABUTMENT ;
    PORT
      LAYER M3 ;
      RECT 154.224 309.444 154.296 309.468 ;
    END
  END w0_wd_in[241]
  PIN w0_wd_in[242]
    DIRECTION INPUT ;
    USE SIGNAL ;
    SHAPE ABUTMENT ;
    PORT
      LAYER M3 ;
      RECT 154.224 312.180 154.296 312.204 ;
    END
  END w0_wd_in[242]
  PIN w0_wd_in[243]
    DIRECTION INPUT ;
    USE SIGNAL ;
    SHAPE ABUTMENT ;
    PORT
      LAYER M3 ;
      RECT 154.224 314.916 154.296 314.940 ;
    END
  END w0_wd_in[243]
  PIN w0_wd_in[244]
    DIRECTION INPUT ;
    USE SIGNAL ;
    SHAPE ABUTMENT ;
    PORT
      LAYER M3 ;
      RECT 154.224 317.652 154.296 317.676 ;
    END
  END w0_wd_in[244]
  PIN w0_wd_in[245]
    DIRECTION INPUT ;
    USE SIGNAL ;
    SHAPE ABUTMENT ;
    PORT
      LAYER M3 ;
      RECT 154.224 320.388 154.296 320.412 ;
    END
  END w0_wd_in[245]
  PIN w0_wd_in[246]
    DIRECTION INPUT ;
    USE SIGNAL ;
    SHAPE ABUTMENT ;
    PORT
      LAYER M3 ;
      RECT 154.224 323.124 154.296 323.148 ;
    END
  END w0_wd_in[246]
  PIN w0_wd_in[247]
    DIRECTION INPUT ;
    USE SIGNAL ;
    SHAPE ABUTMENT ;
    PORT
      LAYER M3 ;
      RECT 154.224 325.860 154.296 325.884 ;
    END
  END w0_wd_in[247]
  PIN w0_wd_in[248]
    DIRECTION INPUT ;
    USE SIGNAL ;
    SHAPE ABUTMENT ;
    PORT
      LAYER M3 ;
      RECT 154.224 328.596 154.296 328.620 ;
    END
  END w0_wd_in[248]
  PIN w0_wd_in[249]
    DIRECTION INPUT ;
    USE SIGNAL ;
    SHAPE ABUTMENT ;
    PORT
      LAYER M3 ;
      RECT 154.224 331.332 154.296 331.356 ;
    END
  END w0_wd_in[249]
  PIN w0_wd_in[250]
    DIRECTION INPUT ;
    USE SIGNAL ;
    SHAPE ABUTMENT ;
    PORT
      LAYER M3 ;
      RECT 154.224 334.068 154.296 334.092 ;
    END
  END w0_wd_in[250]
  PIN w0_wd_in[251]
    DIRECTION INPUT ;
    USE SIGNAL ;
    SHAPE ABUTMENT ;
    PORT
      LAYER M3 ;
      RECT 154.224 336.804 154.296 336.828 ;
    END
  END w0_wd_in[251]
  PIN w0_wd_in[252]
    DIRECTION INPUT ;
    USE SIGNAL ;
    SHAPE ABUTMENT ;
    PORT
      LAYER M3 ;
      RECT 154.224 339.540 154.296 339.564 ;
    END
  END w0_wd_in[252]
  PIN w0_wd_in[253]
    DIRECTION INPUT ;
    USE SIGNAL ;
    SHAPE ABUTMENT ;
    PORT
      LAYER M3 ;
      RECT 154.224 342.276 154.296 342.300 ;
    END
  END w0_wd_in[253]
  PIN w0_wd_in[254]
    DIRECTION INPUT ;
    USE SIGNAL ;
    SHAPE ABUTMENT ;
    PORT
      LAYER M3 ;
      RECT 154.224 345.012 154.296 345.036 ;
    END
  END w0_wd_in[254]
  PIN w0_wd_in[255]
    DIRECTION INPUT ;
    USE SIGNAL ;
    SHAPE ABUTMENT ;
    PORT
      LAYER M3 ;
      RECT 154.224 347.748 154.296 347.772 ;
    END
  END w0_wd_in[255]
  PIN w0_wd_in[256]
    DIRECTION INPUT ;
    USE SIGNAL ;
    SHAPE ABUTMENT ;
    PORT
      LAYER M2 ;
      RECT 0.207 0.000 0.225 0.270 ;
    END
  END w0_wd_in[256]
  PIN w0_wd_in[257]
    DIRECTION INPUT ;
    USE SIGNAL ;
    SHAPE ABUTMENT ;
    PORT
      LAYER M2 ;
      RECT 0.495 0.000 0.513 0.270 ;
    END
  END w0_wd_in[257]
  PIN w0_wd_in[258]
    DIRECTION INPUT ;
    USE SIGNAL ;
    SHAPE ABUTMENT ;
    PORT
      LAYER M2 ;
      RECT 0.783 0.000 0.801 0.270 ;
    END
  END w0_wd_in[258]
  PIN w0_wd_in[259]
    DIRECTION INPUT ;
    USE SIGNAL ;
    SHAPE ABUTMENT ;
    PORT
      LAYER M2 ;
      RECT 1.071 0.000 1.089 0.270 ;
    END
  END w0_wd_in[259]
  PIN w0_wd_in[260]
    DIRECTION INPUT ;
    USE SIGNAL ;
    SHAPE ABUTMENT ;
    PORT
      LAYER M2 ;
      RECT 1.359 0.000 1.377 0.270 ;
    END
  END w0_wd_in[260]
  PIN w0_wd_in[261]
    DIRECTION INPUT ;
    USE SIGNAL ;
    SHAPE ABUTMENT ;
    PORT
      LAYER M2 ;
      RECT 1.647 0.000 1.665 0.270 ;
    END
  END w0_wd_in[261]
  PIN w0_wd_in[262]
    DIRECTION INPUT ;
    USE SIGNAL ;
    SHAPE ABUTMENT ;
    PORT
      LAYER M2 ;
      RECT 1.935 0.000 1.953 0.270 ;
    END
  END w0_wd_in[262]
  PIN w0_wd_in[263]
    DIRECTION INPUT ;
    USE SIGNAL ;
    SHAPE ABUTMENT ;
    PORT
      LAYER M2 ;
      RECT 2.223 0.000 2.241 0.270 ;
    END
  END w0_wd_in[263]
  PIN w0_wd_in[264]
    DIRECTION INPUT ;
    USE SIGNAL ;
    SHAPE ABUTMENT ;
    PORT
      LAYER M2 ;
      RECT 2.511 0.000 2.529 0.270 ;
    END
  END w0_wd_in[264]
  PIN w0_wd_in[265]
    DIRECTION INPUT ;
    USE SIGNAL ;
    SHAPE ABUTMENT ;
    PORT
      LAYER M2 ;
      RECT 2.799 0.000 2.817 0.270 ;
    END
  END w0_wd_in[265]
  PIN w0_wd_in[266]
    DIRECTION INPUT ;
    USE SIGNAL ;
    SHAPE ABUTMENT ;
    PORT
      LAYER M2 ;
      RECT 3.087 0.000 3.105 0.270 ;
    END
  END w0_wd_in[266]
  PIN w0_wd_in[267]
    DIRECTION INPUT ;
    USE SIGNAL ;
    SHAPE ABUTMENT ;
    PORT
      LAYER M2 ;
      RECT 3.375 0.000 3.393 0.270 ;
    END
  END w0_wd_in[267]
  PIN w0_wd_in[268]
    DIRECTION INPUT ;
    USE SIGNAL ;
    SHAPE ABUTMENT ;
    PORT
      LAYER M2 ;
      RECT 3.663 0.000 3.681 0.270 ;
    END
  END w0_wd_in[268]
  PIN w0_wd_in[269]
    DIRECTION INPUT ;
    USE SIGNAL ;
    SHAPE ABUTMENT ;
    PORT
      LAYER M2 ;
      RECT 3.951 0.000 3.969 0.270 ;
    END
  END w0_wd_in[269]
  PIN w0_wd_in[270]
    DIRECTION INPUT ;
    USE SIGNAL ;
    SHAPE ABUTMENT ;
    PORT
      LAYER M2 ;
      RECT 4.239 0.000 4.257 0.270 ;
    END
  END w0_wd_in[270]
  PIN w0_wd_in[271]
    DIRECTION INPUT ;
    USE SIGNAL ;
    SHAPE ABUTMENT ;
    PORT
      LAYER M2 ;
      RECT 4.527 0.000 4.545 0.270 ;
    END
  END w0_wd_in[271]
  PIN w0_wd_in[272]
    DIRECTION INPUT ;
    USE SIGNAL ;
    SHAPE ABUTMENT ;
    PORT
      LAYER M2 ;
      RECT 4.815 0.000 4.833 0.270 ;
    END
  END w0_wd_in[272]
  PIN w0_wd_in[273]
    DIRECTION INPUT ;
    USE SIGNAL ;
    SHAPE ABUTMENT ;
    PORT
      LAYER M2 ;
      RECT 5.103 0.000 5.121 0.270 ;
    END
  END w0_wd_in[273]
  PIN w0_wd_in[274]
    DIRECTION INPUT ;
    USE SIGNAL ;
    SHAPE ABUTMENT ;
    PORT
      LAYER M2 ;
      RECT 5.391 0.000 5.409 0.270 ;
    END
  END w0_wd_in[274]
  PIN w0_wd_in[275]
    DIRECTION INPUT ;
    USE SIGNAL ;
    SHAPE ABUTMENT ;
    PORT
      LAYER M2 ;
      RECT 5.679 0.000 5.697 0.270 ;
    END
  END w0_wd_in[275]
  PIN w0_wd_in[276]
    DIRECTION INPUT ;
    USE SIGNAL ;
    SHAPE ABUTMENT ;
    PORT
      LAYER M2 ;
      RECT 5.967 0.000 5.985 0.270 ;
    END
  END w0_wd_in[276]
  PIN w0_wd_in[277]
    DIRECTION INPUT ;
    USE SIGNAL ;
    SHAPE ABUTMENT ;
    PORT
      LAYER M2 ;
      RECT 6.255 0.000 6.273 0.270 ;
    END
  END w0_wd_in[277]
  PIN w0_wd_in[278]
    DIRECTION INPUT ;
    USE SIGNAL ;
    SHAPE ABUTMENT ;
    PORT
      LAYER M2 ;
      RECT 6.543 0.000 6.561 0.270 ;
    END
  END w0_wd_in[278]
  PIN w0_wd_in[279]
    DIRECTION INPUT ;
    USE SIGNAL ;
    SHAPE ABUTMENT ;
    PORT
      LAYER M2 ;
      RECT 6.831 0.000 6.849 0.270 ;
    END
  END w0_wd_in[279]
  PIN w0_wd_in[280]
    DIRECTION INPUT ;
    USE SIGNAL ;
    SHAPE ABUTMENT ;
    PORT
      LAYER M2 ;
      RECT 7.119 0.000 7.137 0.270 ;
    END
  END w0_wd_in[280]
  PIN w0_wd_in[281]
    DIRECTION INPUT ;
    USE SIGNAL ;
    SHAPE ABUTMENT ;
    PORT
      LAYER M2 ;
      RECT 7.407 0.000 7.425 0.270 ;
    END
  END w0_wd_in[281]
  PIN w0_wd_in[282]
    DIRECTION INPUT ;
    USE SIGNAL ;
    SHAPE ABUTMENT ;
    PORT
      LAYER M2 ;
      RECT 7.695 0.000 7.713 0.270 ;
    END
  END w0_wd_in[282]
  PIN w0_wd_in[283]
    DIRECTION INPUT ;
    USE SIGNAL ;
    SHAPE ABUTMENT ;
    PORT
      LAYER M2 ;
      RECT 7.983 0.000 8.001 0.270 ;
    END
  END w0_wd_in[283]
  PIN w0_wd_in[284]
    DIRECTION INPUT ;
    USE SIGNAL ;
    SHAPE ABUTMENT ;
    PORT
      LAYER M2 ;
      RECT 8.271 0.000 8.289 0.270 ;
    END
  END w0_wd_in[284]
  PIN w0_wd_in[285]
    DIRECTION INPUT ;
    USE SIGNAL ;
    SHAPE ABUTMENT ;
    PORT
      LAYER M2 ;
      RECT 8.559 0.000 8.577 0.270 ;
    END
  END w0_wd_in[285]
  PIN w0_wd_in[286]
    DIRECTION INPUT ;
    USE SIGNAL ;
    SHAPE ABUTMENT ;
    PORT
      LAYER M2 ;
      RECT 8.847 0.000 8.865 0.270 ;
    END
  END w0_wd_in[286]
  PIN w0_wd_in[287]
    DIRECTION INPUT ;
    USE SIGNAL ;
    SHAPE ABUTMENT ;
    PORT
      LAYER M2 ;
      RECT 9.135 0.000 9.153 0.270 ;
    END
  END w0_wd_in[287]
  PIN w0_wd_in[288]
    DIRECTION INPUT ;
    USE SIGNAL ;
    SHAPE ABUTMENT ;
    PORT
      LAYER M2 ;
      RECT 9.423 0.000 9.441 0.270 ;
    END
  END w0_wd_in[288]
  PIN w0_wd_in[289]
    DIRECTION INPUT ;
    USE SIGNAL ;
    SHAPE ABUTMENT ;
    PORT
      LAYER M2 ;
      RECT 9.711 0.000 9.729 0.270 ;
    END
  END w0_wd_in[289]
  PIN w0_wd_in[290]
    DIRECTION INPUT ;
    USE SIGNAL ;
    SHAPE ABUTMENT ;
    PORT
      LAYER M2 ;
      RECT 9.999 0.000 10.017 0.270 ;
    END
  END w0_wd_in[290]
  PIN w0_wd_in[291]
    DIRECTION INPUT ;
    USE SIGNAL ;
    SHAPE ABUTMENT ;
    PORT
      LAYER M2 ;
      RECT 10.287 0.000 10.305 0.270 ;
    END
  END w0_wd_in[291]
  PIN w0_wd_in[292]
    DIRECTION INPUT ;
    USE SIGNAL ;
    SHAPE ABUTMENT ;
    PORT
      LAYER M2 ;
      RECT 10.575 0.000 10.593 0.270 ;
    END
  END w0_wd_in[292]
  PIN w0_wd_in[293]
    DIRECTION INPUT ;
    USE SIGNAL ;
    SHAPE ABUTMENT ;
    PORT
      LAYER M2 ;
      RECT 10.863 0.000 10.881 0.270 ;
    END
  END w0_wd_in[293]
  PIN w0_wd_in[294]
    DIRECTION INPUT ;
    USE SIGNAL ;
    SHAPE ABUTMENT ;
    PORT
      LAYER M2 ;
      RECT 11.151 0.000 11.169 0.270 ;
    END
  END w0_wd_in[294]
  PIN w0_wd_in[295]
    DIRECTION INPUT ;
    USE SIGNAL ;
    SHAPE ABUTMENT ;
    PORT
      LAYER M2 ;
      RECT 11.439 0.000 11.457 0.270 ;
    END
  END w0_wd_in[295]
  PIN w0_wd_in[296]
    DIRECTION INPUT ;
    USE SIGNAL ;
    SHAPE ABUTMENT ;
    PORT
      LAYER M2 ;
      RECT 11.727 0.000 11.745 0.270 ;
    END
  END w0_wd_in[296]
  PIN w0_wd_in[297]
    DIRECTION INPUT ;
    USE SIGNAL ;
    SHAPE ABUTMENT ;
    PORT
      LAYER M2 ;
      RECT 12.015 0.000 12.033 0.270 ;
    END
  END w0_wd_in[297]
  PIN w0_wd_in[298]
    DIRECTION INPUT ;
    USE SIGNAL ;
    SHAPE ABUTMENT ;
    PORT
      LAYER M2 ;
      RECT 12.303 0.000 12.321 0.270 ;
    END
  END w0_wd_in[298]
  PIN w0_wd_in[299]
    DIRECTION INPUT ;
    USE SIGNAL ;
    SHAPE ABUTMENT ;
    PORT
      LAYER M2 ;
      RECT 12.591 0.000 12.609 0.270 ;
    END
  END w0_wd_in[299]
  PIN w0_wd_in[300]
    DIRECTION INPUT ;
    USE SIGNAL ;
    SHAPE ABUTMENT ;
    PORT
      LAYER M2 ;
      RECT 12.879 0.000 12.897 0.270 ;
    END
  END w0_wd_in[300]
  PIN w0_wd_in[301]
    DIRECTION INPUT ;
    USE SIGNAL ;
    SHAPE ABUTMENT ;
    PORT
      LAYER M2 ;
      RECT 13.167 0.000 13.185 0.270 ;
    END
  END w0_wd_in[301]
  PIN w0_wd_in[302]
    DIRECTION INPUT ;
    USE SIGNAL ;
    SHAPE ABUTMENT ;
    PORT
      LAYER M2 ;
      RECT 13.455 0.000 13.473 0.270 ;
    END
  END w0_wd_in[302]
  PIN w0_wd_in[303]
    DIRECTION INPUT ;
    USE SIGNAL ;
    SHAPE ABUTMENT ;
    PORT
      LAYER M2 ;
      RECT 13.743 0.000 13.761 0.270 ;
    END
  END w0_wd_in[303]
  PIN w0_wd_in[304]
    DIRECTION INPUT ;
    USE SIGNAL ;
    SHAPE ABUTMENT ;
    PORT
      LAYER M2 ;
      RECT 14.031 0.000 14.049 0.270 ;
    END
  END w0_wd_in[304]
  PIN w0_wd_in[305]
    DIRECTION INPUT ;
    USE SIGNAL ;
    SHAPE ABUTMENT ;
    PORT
      LAYER M2 ;
      RECT 14.319 0.000 14.337 0.270 ;
    END
  END w0_wd_in[305]
  PIN w0_wd_in[306]
    DIRECTION INPUT ;
    USE SIGNAL ;
    SHAPE ABUTMENT ;
    PORT
      LAYER M2 ;
      RECT 14.607 0.000 14.625 0.270 ;
    END
  END w0_wd_in[306]
  PIN w0_wd_in[307]
    DIRECTION INPUT ;
    USE SIGNAL ;
    SHAPE ABUTMENT ;
    PORT
      LAYER M2 ;
      RECT 14.895 0.000 14.913 0.270 ;
    END
  END w0_wd_in[307]
  PIN w0_wd_in[308]
    DIRECTION INPUT ;
    USE SIGNAL ;
    SHAPE ABUTMENT ;
    PORT
      LAYER M2 ;
      RECT 15.183 0.000 15.201 0.270 ;
    END
  END w0_wd_in[308]
  PIN w0_wd_in[309]
    DIRECTION INPUT ;
    USE SIGNAL ;
    SHAPE ABUTMENT ;
    PORT
      LAYER M2 ;
      RECT 15.471 0.000 15.489 0.270 ;
    END
  END w0_wd_in[309]
  PIN w0_wd_in[310]
    DIRECTION INPUT ;
    USE SIGNAL ;
    SHAPE ABUTMENT ;
    PORT
      LAYER M2 ;
      RECT 15.759 0.000 15.777 0.270 ;
    END
  END w0_wd_in[310]
  PIN w0_wd_in[311]
    DIRECTION INPUT ;
    USE SIGNAL ;
    SHAPE ABUTMENT ;
    PORT
      LAYER M2 ;
      RECT 16.047 0.000 16.065 0.270 ;
    END
  END w0_wd_in[311]
  PIN w0_wd_in[312]
    DIRECTION INPUT ;
    USE SIGNAL ;
    SHAPE ABUTMENT ;
    PORT
      LAYER M2 ;
      RECT 16.335 0.000 16.353 0.270 ;
    END
  END w0_wd_in[312]
  PIN w0_wd_in[313]
    DIRECTION INPUT ;
    USE SIGNAL ;
    SHAPE ABUTMENT ;
    PORT
      LAYER M2 ;
      RECT 16.623 0.000 16.641 0.270 ;
    END
  END w0_wd_in[313]
  PIN w0_wd_in[314]
    DIRECTION INPUT ;
    USE SIGNAL ;
    SHAPE ABUTMENT ;
    PORT
      LAYER M2 ;
      RECT 16.911 0.000 16.929 0.270 ;
    END
  END w0_wd_in[314]
  PIN w0_wd_in[315]
    DIRECTION INPUT ;
    USE SIGNAL ;
    SHAPE ABUTMENT ;
    PORT
      LAYER M2 ;
      RECT 17.199 0.000 17.217 0.270 ;
    END
  END w0_wd_in[315]
  PIN w0_wd_in[316]
    DIRECTION INPUT ;
    USE SIGNAL ;
    SHAPE ABUTMENT ;
    PORT
      LAYER M2 ;
      RECT 17.487 0.000 17.505 0.270 ;
    END
  END w0_wd_in[316]
  PIN w0_wd_in[317]
    DIRECTION INPUT ;
    USE SIGNAL ;
    SHAPE ABUTMENT ;
    PORT
      LAYER M2 ;
      RECT 17.775 0.000 17.793 0.270 ;
    END
  END w0_wd_in[317]
  PIN w0_wd_in[318]
    DIRECTION INPUT ;
    USE SIGNAL ;
    SHAPE ABUTMENT ;
    PORT
      LAYER M2 ;
      RECT 18.063 0.000 18.081 0.270 ;
    END
  END w0_wd_in[318]
  PIN w0_wd_in[319]
    DIRECTION INPUT ;
    USE SIGNAL ;
    SHAPE ABUTMENT ;
    PORT
      LAYER M2 ;
      RECT 18.351 0.000 18.369 0.270 ;
    END
  END w0_wd_in[319]
  PIN w0_wd_in[320]
    DIRECTION INPUT ;
    USE SIGNAL ;
    SHAPE ABUTMENT ;
    PORT
      LAYER M2 ;
      RECT 18.639 0.000 18.657 0.270 ;
    END
  END w0_wd_in[320]
  PIN w0_wd_in[321]
    DIRECTION INPUT ;
    USE SIGNAL ;
    SHAPE ABUTMENT ;
    PORT
      LAYER M2 ;
      RECT 18.927 0.000 18.945 0.270 ;
    END
  END w0_wd_in[321]
  PIN w0_wd_in[322]
    DIRECTION INPUT ;
    USE SIGNAL ;
    SHAPE ABUTMENT ;
    PORT
      LAYER M2 ;
      RECT 19.215 0.000 19.233 0.270 ;
    END
  END w0_wd_in[322]
  PIN w0_wd_in[323]
    DIRECTION INPUT ;
    USE SIGNAL ;
    SHAPE ABUTMENT ;
    PORT
      LAYER M2 ;
      RECT 19.503 0.000 19.521 0.270 ;
    END
  END w0_wd_in[323]
  PIN w0_wd_in[324]
    DIRECTION INPUT ;
    USE SIGNAL ;
    SHAPE ABUTMENT ;
    PORT
      LAYER M2 ;
      RECT 19.791 0.000 19.809 0.270 ;
    END
  END w0_wd_in[324]
  PIN w0_wd_in[325]
    DIRECTION INPUT ;
    USE SIGNAL ;
    SHAPE ABUTMENT ;
    PORT
      LAYER M2 ;
      RECT 20.079 0.000 20.097 0.270 ;
    END
  END w0_wd_in[325]
  PIN w0_wd_in[326]
    DIRECTION INPUT ;
    USE SIGNAL ;
    SHAPE ABUTMENT ;
    PORT
      LAYER M2 ;
      RECT 20.367 0.000 20.385 0.270 ;
    END
  END w0_wd_in[326]
  PIN w0_wd_in[327]
    DIRECTION INPUT ;
    USE SIGNAL ;
    SHAPE ABUTMENT ;
    PORT
      LAYER M2 ;
      RECT 20.655 0.000 20.673 0.270 ;
    END
  END w0_wd_in[327]
  PIN w0_wd_in[328]
    DIRECTION INPUT ;
    USE SIGNAL ;
    SHAPE ABUTMENT ;
    PORT
      LAYER M2 ;
      RECT 20.943 0.000 20.961 0.270 ;
    END
  END w0_wd_in[328]
  PIN w0_wd_in[329]
    DIRECTION INPUT ;
    USE SIGNAL ;
    SHAPE ABUTMENT ;
    PORT
      LAYER M2 ;
      RECT 21.231 0.000 21.249 0.270 ;
    END
  END w0_wd_in[329]
  PIN w0_wd_in[330]
    DIRECTION INPUT ;
    USE SIGNAL ;
    SHAPE ABUTMENT ;
    PORT
      LAYER M2 ;
      RECT 21.519 0.000 21.537 0.270 ;
    END
  END w0_wd_in[330]
  PIN w0_wd_in[331]
    DIRECTION INPUT ;
    USE SIGNAL ;
    SHAPE ABUTMENT ;
    PORT
      LAYER M2 ;
      RECT 21.807 0.000 21.825 0.270 ;
    END
  END w0_wd_in[331]
  PIN w0_wd_in[332]
    DIRECTION INPUT ;
    USE SIGNAL ;
    SHAPE ABUTMENT ;
    PORT
      LAYER M2 ;
      RECT 22.095 0.000 22.113 0.270 ;
    END
  END w0_wd_in[332]
  PIN w0_wd_in[333]
    DIRECTION INPUT ;
    USE SIGNAL ;
    SHAPE ABUTMENT ;
    PORT
      LAYER M2 ;
      RECT 22.383 0.000 22.401 0.270 ;
    END
  END w0_wd_in[333]
  PIN w0_wd_in[334]
    DIRECTION INPUT ;
    USE SIGNAL ;
    SHAPE ABUTMENT ;
    PORT
      LAYER M2 ;
      RECT 22.671 0.000 22.689 0.270 ;
    END
  END w0_wd_in[334]
  PIN w0_wd_in[335]
    DIRECTION INPUT ;
    USE SIGNAL ;
    SHAPE ABUTMENT ;
    PORT
      LAYER M2 ;
      RECT 22.959 0.000 22.977 0.270 ;
    END
  END w0_wd_in[335]
  PIN w0_wd_in[336]
    DIRECTION INPUT ;
    USE SIGNAL ;
    SHAPE ABUTMENT ;
    PORT
      LAYER M2 ;
      RECT 23.247 0.000 23.265 0.270 ;
    END
  END w0_wd_in[336]
  PIN w0_wd_in[337]
    DIRECTION INPUT ;
    USE SIGNAL ;
    SHAPE ABUTMENT ;
    PORT
      LAYER M2 ;
      RECT 23.535 0.000 23.553 0.270 ;
    END
  END w0_wd_in[337]
  PIN w0_wd_in[338]
    DIRECTION INPUT ;
    USE SIGNAL ;
    SHAPE ABUTMENT ;
    PORT
      LAYER M2 ;
      RECT 23.823 0.000 23.841 0.270 ;
    END
  END w0_wd_in[338]
  PIN w0_wd_in[339]
    DIRECTION INPUT ;
    USE SIGNAL ;
    SHAPE ABUTMENT ;
    PORT
      LAYER M2 ;
      RECT 24.111 0.000 24.129 0.270 ;
    END
  END w0_wd_in[339]
  PIN w0_wd_in[340]
    DIRECTION INPUT ;
    USE SIGNAL ;
    SHAPE ABUTMENT ;
    PORT
      LAYER M2 ;
      RECT 24.399 0.000 24.417 0.270 ;
    END
  END w0_wd_in[340]
  PIN w0_wd_in[341]
    DIRECTION INPUT ;
    USE SIGNAL ;
    SHAPE ABUTMENT ;
    PORT
      LAYER M2 ;
      RECT 24.687 0.000 24.705 0.270 ;
    END
  END w0_wd_in[341]
  PIN w0_wd_in[342]
    DIRECTION INPUT ;
    USE SIGNAL ;
    SHAPE ABUTMENT ;
    PORT
      LAYER M2 ;
      RECT 24.975 0.000 24.993 0.270 ;
    END
  END w0_wd_in[342]
  PIN w0_wd_in[343]
    DIRECTION INPUT ;
    USE SIGNAL ;
    SHAPE ABUTMENT ;
    PORT
      LAYER M2 ;
      RECT 25.263 0.000 25.281 0.270 ;
    END
  END w0_wd_in[343]
  PIN w0_wd_in[344]
    DIRECTION INPUT ;
    USE SIGNAL ;
    SHAPE ABUTMENT ;
    PORT
      LAYER M2 ;
      RECT 25.551 0.000 25.569 0.270 ;
    END
  END w0_wd_in[344]
  PIN w0_wd_in[345]
    DIRECTION INPUT ;
    USE SIGNAL ;
    SHAPE ABUTMENT ;
    PORT
      LAYER M2 ;
      RECT 25.839 0.000 25.857 0.270 ;
    END
  END w0_wd_in[345]
  PIN w0_wd_in[346]
    DIRECTION INPUT ;
    USE SIGNAL ;
    SHAPE ABUTMENT ;
    PORT
      LAYER M2 ;
      RECT 26.127 0.000 26.145 0.270 ;
    END
  END w0_wd_in[346]
  PIN w0_wd_in[347]
    DIRECTION INPUT ;
    USE SIGNAL ;
    SHAPE ABUTMENT ;
    PORT
      LAYER M2 ;
      RECT 26.415 0.000 26.433 0.270 ;
    END
  END w0_wd_in[347]
  PIN w0_wd_in[348]
    DIRECTION INPUT ;
    USE SIGNAL ;
    SHAPE ABUTMENT ;
    PORT
      LAYER M2 ;
      RECT 26.703 0.000 26.721 0.270 ;
    END
  END w0_wd_in[348]
  PIN w0_wd_in[349]
    DIRECTION INPUT ;
    USE SIGNAL ;
    SHAPE ABUTMENT ;
    PORT
      LAYER M2 ;
      RECT 26.991 0.000 27.009 0.270 ;
    END
  END w0_wd_in[349]
  PIN w0_wd_in[350]
    DIRECTION INPUT ;
    USE SIGNAL ;
    SHAPE ABUTMENT ;
    PORT
      LAYER M2 ;
      RECT 27.279 0.000 27.297 0.270 ;
    END
  END w0_wd_in[350]
  PIN w0_wd_in[351]
    DIRECTION INPUT ;
    USE SIGNAL ;
    SHAPE ABUTMENT ;
    PORT
      LAYER M2 ;
      RECT 27.567 0.000 27.585 0.270 ;
    END
  END w0_wd_in[351]
  PIN w0_wd_in[352]
    DIRECTION INPUT ;
    USE SIGNAL ;
    SHAPE ABUTMENT ;
    PORT
      LAYER M2 ;
      RECT 27.855 0.000 27.873 0.270 ;
    END
  END w0_wd_in[352]
  PIN w0_wd_in[353]
    DIRECTION INPUT ;
    USE SIGNAL ;
    SHAPE ABUTMENT ;
    PORT
      LAYER M2 ;
      RECT 28.143 0.000 28.161 0.270 ;
    END
  END w0_wd_in[353]
  PIN w0_wd_in[354]
    DIRECTION INPUT ;
    USE SIGNAL ;
    SHAPE ABUTMENT ;
    PORT
      LAYER M2 ;
      RECT 28.431 0.000 28.449 0.270 ;
    END
  END w0_wd_in[354]
  PIN w0_wd_in[355]
    DIRECTION INPUT ;
    USE SIGNAL ;
    SHAPE ABUTMENT ;
    PORT
      LAYER M2 ;
      RECT 28.719 0.000 28.737 0.270 ;
    END
  END w0_wd_in[355]
  PIN w0_wd_in[356]
    DIRECTION INPUT ;
    USE SIGNAL ;
    SHAPE ABUTMENT ;
    PORT
      LAYER M2 ;
      RECT 29.007 0.000 29.025 0.270 ;
    END
  END w0_wd_in[356]
  PIN w0_wd_in[357]
    DIRECTION INPUT ;
    USE SIGNAL ;
    SHAPE ABUTMENT ;
    PORT
      LAYER M2 ;
      RECT 29.295 0.000 29.313 0.270 ;
    END
  END w0_wd_in[357]
  PIN w0_wd_in[358]
    DIRECTION INPUT ;
    USE SIGNAL ;
    SHAPE ABUTMENT ;
    PORT
      LAYER M2 ;
      RECT 29.583 0.000 29.601 0.270 ;
    END
  END w0_wd_in[358]
  PIN w0_wd_in[359]
    DIRECTION INPUT ;
    USE SIGNAL ;
    SHAPE ABUTMENT ;
    PORT
      LAYER M2 ;
      RECT 29.871 0.000 29.889 0.270 ;
    END
  END w0_wd_in[359]
  PIN w0_wd_in[360]
    DIRECTION INPUT ;
    USE SIGNAL ;
    SHAPE ABUTMENT ;
    PORT
      LAYER M2 ;
      RECT 30.159 0.000 30.177 0.270 ;
    END
  END w0_wd_in[360]
  PIN w0_wd_in[361]
    DIRECTION INPUT ;
    USE SIGNAL ;
    SHAPE ABUTMENT ;
    PORT
      LAYER M2 ;
      RECT 30.447 0.000 30.465 0.270 ;
    END
  END w0_wd_in[361]
  PIN w0_wd_in[362]
    DIRECTION INPUT ;
    USE SIGNAL ;
    SHAPE ABUTMENT ;
    PORT
      LAYER M2 ;
      RECT 30.735 0.000 30.753 0.270 ;
    END
  END w0_wd_in[362]
  PIN w0_wd_in[363]
    DIRECTION INPUT ;
    USE SIGNAL ;
    SHAPE ABUTMENT ;
    PORT
      LAYER M2 ;
      RECT 31.023 0.000 31.041 0.270 ;
    END
  END w0_wd_in[363]
  PIN w0_wd_in[364]
    DIRECTION INPUT ;
    USE SIGNAL ;
    SHAPE ABUTMENT ;
    PORT
      LAYER M2 ;
      RECT 31.311 0.000 31.329 0.270 ;
    END
  END w0_wd_in[364]
  PIN w0_wd_in[365]
    DIRECTION INPUT ;
    USE SIGNAL ;
    SHAPE ABUTMENT ;
    PORT
      LAYER M2 ;
      RECT 31.599 0.000 31.617 0.270 ;
    END
  END w0_wd_in[365]
  PIN w0_wd_in[366]
    DIRECTION INPUT ;
    USE SIGNAL ;
    SHAPE ABUTMENT ;
    PORT
      LAYER M2 ;
      RECT 31.887 0.000 31.905 0.270 ;
    END
  END w0_wd_in[366]
  PIN w0_wd_in[367]
    DIRECTION INPUT ;
    USE SIGNAL ;
    SHAPE ABUTMENT ;
    PORT
      LAYER M2 ;
      RECT 32.175 0.000 32.193 0.270 ;
    END
  END w0_wd_in[367]
  PIN w0_wd_in[368]
    DIRECTION INPUT ;
    USE SIGNAL ;
    SHAPE ABUTMENT ;
    PORT
      LAYER M2 ;
      RECT 32.463 0.000 32.481 0.270 ;
    END
  END w0_wd_in[368]
  PIN w0_wd_in[369]
    DIRECTION INPUT ;
    USE SIGNAL ;
    SHAPE ABUTMENT ;
    PORT
      LAYER M2 ;
      RECT 32.751 0.000 32.769 0.270 ;
    END
  END w0_wd_in[369]
  PIN w0_wd_in[370]
    DIRECTION INPUT ;
    USE SIGNAL ;
    SHAPE ABUTMENT ;
    PORT
      LAYER M2 ;
      RECT 33.039 0.000 33.057 0.270 ;
    END
  END w0_wd_in[370]
  PIN w0_wd_in[371]
    DIRECTION INPUT ;
    USE SIGNAL ;
    SHAPE ABUTMENT ;
    PORT
      LAYER M2 ;
      RECT 33.327 0.000 33.345 0.270 ;
    END
  END w0_wd_in[371]
  PIN w0_wd_in[372]
    DIRECTION INPUT ;
    USE SIGNAL ;
    SHAPE ABUTMENT ;
    PORT
      LAYER M2 ;
      RECT 33.615 0.000 33.633 0.270 ;
    END
  END w0_wd_in[372]
  PIN w0_wd_in[373]
    DIRECTION INPUT ;
    USE SIGNAL ;
    SHAPE ABUTMENT ;
    PORT
      LAYER M2 ;
      RECT 33.903 0.000 33.921 0.270 ;
    END
  END w0_wd_in[373]
  PIN w0_wd_in[374]
    DIRECTION INPUT ;
    USE SIGNAL ;
    SHAPE ABUTMENT ;
    PORT
      LAYER M2 ;
      RECT 34.191 0.000 34.209 0.270 ;
    END
  END w0_wd_in[374]
  PIN w0_wd_in[375]
    DIRECTION INPUT ;
    USE SIGNAL ;
    SHAPE ABUTMENT ;
    PORT
      LAYER M2 ;
      RECT 34.479 0.000 34.497 0.270 ;
    END
  END w0_wd_in[375]
  PIN w0_wd_in[376]
    DIRECTION INPUT ;
    USE SIGNAL ;
    SHAPE ABUTMENT ;
    PORT
      LAYER M2 ;
      RECT 34.767 0.000 34.785 0.270 ;
    END
  END w0_wd_in[376]
  PIN w0_wd_in[377]
    DIRECTION INPUT ;
    USE SIGNAL ;
    SHAPE ABUTMENT ;
    PORT
      LAYER M2 ;
      RECT 35.055 0.000 35.073 0.270 ;
    END
  END w0_wd_in[377]
  PIN w0_wd_in[378]
    DIRECTION INPUT ;
    USE SIGNAL ;
    SHAPE ABUTMENT ;
    PORT
      LAYER M2 ;
      RECT 35.343 0.000 35.361 0.270 ;
    END
  END w0_wd_in[378]
  PIN w0_wd_in[379]
    DIRECTION INPUT ;
    USE SIGNAL ;
    SHAPE ABUTMENT ;
    PORT
      LAYER M2 ;
      RECT 35.631 0.000 35.649 0.270 ;
    END
  END w0_wd_in[379]
  PIN w0_wd_in[380]
    DIRECTION INPUT ;
    USE SIGNAL ;
    SHAPE ABUTMENT ;
    PORT
      LAYER M2 ;
      RECT 35.919 0.000 35.937 0.270 ;
    END
  END w0_wd_in[380]
  PIN w0_wd_in[381]
    DIRECTION INPUT ;
    USE SIGNAL ;
    SHAPE ABUTMENT ;
    PORT
      LAYER M2 ;
      RECT 36.207 0.000 36.225 0.270 ;
    END
  END w0_wd_in[381]
  PIN w0_wd_in[382]
    DIRECTION INPUT ;
    USE SIGNAL ;
    SHAPE ABUTMENT ;
    PORT
      LAYER M2 ;
      RECT 36.495 0.000 36.513 0.270 ;
    END
  END w0_wd_in[382]
  PIN w0_wd_in[383]
    DIRECTION INPUT ;
    USE SIGNAL ;
    SHAPE ABUTMENT ;
    PORT
      LAYER M2 ;
      RECT 36.783 0.000 36.801 0.270 ;
    END
  END w0_wd_in[383]
  PIN w0_wd_in[384]
    DIRECTION INPUT ;
    USE SIGNAL ;
    SHAPE ABUTMENT ;
    PORT
      LAYER M2 ;
      RECT 37.071 0.000 37.089 0.270 ;
    END
  END w0_wd_in[384]
  PIN w0_wd_in[385]
    DIRECTION INPUT ;
    USE SIGNAL ;
    SHAPE ABUTMENT ;
    PORT
      LAYER M2 ;
      RECT 37.359 0.000 37.377 0.270 ;
    END
  END w0_wd_in[385]
  PIN w0_wd_in[386]
    DIRECTION INPUT ;
    USE SIGNAL ;
    SHAPE ABUTMENT ;
    PORT
      LAYER M2 ;
      RECT 37.647 0.000 37.665 0.270 ;
    END
  END w0_wd_in[386]
  PIN w0_wd_in[387]
    DIRECTION INPUT ;
    USE SIGNAL ;
    SHAPE ABUTMENT ;
    PORT
      LAYER M2 ;
      RECT 37.935 0.000 37.953 0.270 ;
    END
  END w0_wd_in[387]
  PIN w0_wd_in[388]
    DIRECTION INPUT ;
    USE SIGNAL ;
    SHAPE ABUTMENT ;
    PORT
      LAYER M2 ;
      RECT 38.223 0.000 38.241 0.270 ;
    END
  END w0_wd_in[388]
  PIN w0_wd_in[389]
    DIRECTION INPUT ;
    USE SIGNAL ;
    SHAPE ABUTMENT ;
    PORT
      LAYER M2 ;
      RECT 38.511 0.000 38.529 0.270 ;
    END
  END w0_wd_in[389]
  PIN w0_wd_in[390]
    DIRECTION INPUT ;
    USE SIGNAL ;
    SHAPE ABUTMENT ;
    PORT
      LAYER M2 ;
      RECT 38.799 0.000 38.817 0.270 ;
    END
  END w0_wd_in[390]
  PIN w0_wd_in[391]
    DIRECTION INPUT ;
    USE SIGNAL ;
    SHAPE ABUTMENT ;
    PORT
      LAYER M2 ;
      RECT 39.087 0.000 39.105 0.270 ;
    END
  END w0_wd_in[391]
  PIN w0_wd_in[392]
    DIRECTION INPUT ;
    USE SIGNAL ;
    SHAPE ABUTMENT ;
    PORT
      LAYER M2 ;
      RECT 39.375 0.000 39.393 0.270 ;
    END
  END w0_wd_in[392]
  PIN w0_wd_in[393]
    DIRECTION INPUT ;
    USE SIGNAL ;
    SHAPE ABUTMENT ;
    PORT
      LAYER M2 ;
      RECT 39.663 0.000 39.681 0.270 ;
    END
  END w0_wd_in[393]
  PIN w0_wd_in[394]
    DIRECTION INPUT ;
    USE SIGNAL ;
    SHAPE ABUTMENT ;
    PORT
      LAYER M2 ;
      RECT 39.951 0.000 39.969 0.270 ;
    END
  END w0_wd_in[394]
  PIN w0_wd_in[395]
    DIRECTION INPUT ;
    USE SIGNAL ;
    SHAPE ABUTMENT ;
    PORT
      LAYER M2 ;
      RECT 40.239 0.000 40.257 0.270 ;
    END
  END w0_wd_in[395]
  PIN w0_wd_in[396]
    DIRECTION INPUT ;
    USE SIGNAL ;
    SHAPE ABUTMENT ;
    PORT
      LAYER M2 ;
      RECT 40.527 0.000 40.545 0.270 ;
    END
  END w0_wd_in[396]
  PIN w0_wd_in[397]
    DIRECTION INPUT ;
    USE SIGNAL ;
    SHAPE ABUTMENT ;
    PORT
      LAYER M2 ;
      RECT 40.815 0.000 40.833 0.270 ;
    END
  END w0_wd_in[397]
  PIN w0_wd_in[398]
    DIRECTION INPUT ;
    USE SIGNAL ;
    SHAPE ABUTMENT ;
    PORT
      LAYER M2 ;
      RECT 41.103 0.000 41.121 0.270 ;
    END
  END w0_wd_in[398]
  PIN w0_wd_in[399]
    DIRECTION INPUT ;
    USE SIGNAL ;
    SHAPE ABUTMENT ;
    PORT
      LAYER M2 ;
      RECT 41.391 0.000 41.409 0.270 ;
    END
  END w0_wd_in[399]
  PIN w0_wd_in[400]
    DIRECTION INPUT ;
    USE SIGNAL ;
    SHAPE ABUTMENT ;
    PORT
      LAYER M2 ;
      RECT 41.679 0.000 41.697 0.270 ;
    END
  END w0_wd_in[400]
  PIN w0_wd_in[401]
    DIRECTION INPUT ;
    USE SIGNAL ;
    SHAPE ABUTMENT ;
    PORT
      LAYER M2 ;
      RECT 41.967 0.000 41.985 0.270 ;
    END
  END w0_wd_in[401]
  PIN w0_wd_in[402]
    DIRECTION INPUT ;
    USE SIGNAL ;
    SHAPE ABUTMENT ;
    PORT
      LAYER M2 ;
      RECT 42.255 0.000 42.273 0.270 ;
    END
  END w0_wd_in[402]
  PIN w0_wd_in[403]
    DIRECTION INPUT ;
    USE SIGNAL ;
    SHAPE ABUTMENT ;
    PORT
      LAYER M2 ;
      RECT 42.543 0.000 42.561 0.270 ;
    END
  END w0_wd_in[403]
  PIN w0_wd_in[404]
    DIRECTION INPUT ;
    USE SIGNAL ;
    SHAPE ABUTMENT ;
    PORT
      LAYER M2 ;
      RECT 42.831 0.000 42.849 0.270 ;
    END
  END w0_wd_in[404]
  PIN w0_wd_in[405]
    DIRECTION INPUT ;
    USE SIGNAL ;
    SHAPE ABUTMENT ;
    PORT
      LAYER M2 ;
      RECT 43.119 0.000 43.137 0.270 ;
    END
  END w0_wd_in[405]
  PIN w0_wd_in[406]
    DIRECTION INPUT ;
    USE SIGNAL ;
    SHAPE ABUTMENT ;
    PORT
      LAYER M2 ;
      RECT 43.407 0.000 43.425 0.270 ;
    END
  END w0_wd_in[406]
  PIN w0_wd_in[407]
    DIRECTION INPUT ;
    USE SIGNAL ;
    SHAPE ABUTMENT ;
    PORT
      LAYER M2 ;
      RECT 43.695 0.000 43.713 0.270 ;
    END
  END w0_wd_in[407]
  PIN w0_wd_in[408]
    DIRECTION INPUT ;
    USE SIGNAL ;
    SHAPE ABUTMENT ;
    PORT
      LAYER M2 ;
      RECT 43.983 0.000 44.001 0.270 ;
    END
  END w0_wd_in[408]
  PIN w0_wd_in[409]
    DIRECTION INPUT ;
    USE SIGNAL ;
    SHAPE ABUTMENT ;
    PORT
      LAYER M2 ;
      RECT 44.271 0.000 44.289 0.270 ;
    END
  END w0_wd_in[409]
  PIN w0_wd_in[410]
    DIRECTION INPUT ;
    USE SIGNAL ;
    SHAPE ABUTMENT ;
    PORT
      LAYER M2 ;
      RECT 44.559 0.000 44.577 0.270 ;
    END
  END w0_wd_in[410]
  PIN w0_wd_in[411]
    DIRECTION INPUT ;
    USE SIGNAL ;
    SHAPE ABUTMENT ;
    PORT
      LAYER M2 ;
      RECT 44.847 0.000 44.865 0.270 ;
    END
  END w0_wd_in[411]
  PIN w0_wd_in[412]
    DIRECTION INPUT ;
    USE SIGNAL ;
    SHAPE ABUTMENT ;
    PORT
      LAYER M2 ;
      RECT 45.135 0.000 45.153 0.270 ;
    END
  END w0_wd_in[412]
  PIN w0_wd_in[413]
    DIRECTION INPUT ;
    USE SIGNAL ;
    SHAPE ABUTMENT ;
    PORT
      LAYER M2 ;
      RECT 45.423 0.000 45.441 0.270 ;
    END
  END w0_wd_in[413]
  PIN w0_wd_in[414]
    DIRECTION INPUT ;
    USE SIGNAL ;
    SHAPE ABUTMENT ;
    PORT
      LAYER M2 ;
      RECT 45.711 0.000 45.729 0.270 ;
    END
  END w0_wd_in[414]
  PIN w0_wd_in[415]
    DIRECTION INPUT ;
    USE SIGNAL ;
    SHAPE ABUTMENT ;
    PORT
      LAYER M2 ;
      RECT 45.999 0.000 46.017 0.270 ;
    END
  END w0_wd_in[415]
  PIN w0_wd_in[416]
    DIRECTION INPUT ;
    USE SIGNAL ;
    SHAPE ABUTMENT ;
    PORT
      LAYER M2 ;
      RECT 46.287 0.000 46.305 0.270 ;
    END
  END w0_wd_in[416]
  PIN w0_wd_in[417]
    DIRECTION INPUT ;
    USE SIGNAL ;
    SHAPE ABUTMENT ;
    PORT
      LAYER M2 ;
      RECT 46.575 0.000 46.593 0.270 ;
    END
  END w0_wd_in[417]
  PIN w0_wd_in[418]
    DIRECTION INPUT ;
    USE SIGNAL ;
    SHAPE ABUTMENT ;
    PORT
      LAYER M2 ;
      RECT 46.863 0.000 46.881 0.270 ;
    END
  END w0_wd_in[418]
  PIN w0_wd_in[419]
    DIRECTION INPUT ;
    USE SIGNAL ;
    SHAPE ABUTMENT ;
    PORT
      LAYER M2 ;
      RECT 47.151 0.000 47.169 0.270 ;
    END
  END w0_wd_in[419]
  PIN w0_wd_in[420]
    DIRECTION INPUT ;
    USE SIGNAL ;
    SHAPE ABUTMENT ;
    PORT
      LAYER M2 ;
      RECT 47.439 0.000 47.457 0.270 ;
    END
  END w0_wd_in[420]
  PIN w0_wd_in[421]
    DIRECTION INPUT ;
    USE SIGNAL ;
    SHAPE ABUTMENT ;
    PORT
      LAYER M2 ;
      RECT 47.727 0.000 47.745 0.270 ;
    END
  END w0_wd_in[421]
  PIN w0_wd_in[422]
    DIRECTION INPUT ;
    USE SIGNAL ;
    SHAPE ABUTMENT ;
    PORT
      LAYER M2 ;
      RECT 48.015 0.000 48.033 0.270 ;
    END
  END w0_wd_in[422]
  PIN w0_wd_in[423]
    DIRECTION INPUT ;
    USE SIGNAL ;
    SHAPE ABUTMENT ;
    PORT
      LAYER M2 ;
      RECT 48.303 0.000 48.321 0.270 ;
    END
  END w0_wd_in[423]
  PIN w0_wd_in[424]
    DIRECTION INPUT ;
    USE SIGNAL ;
    SHAPE ABUTMENT ;
    PORT
      LAYER M2 ;
      RECT 48.591 0.000 48.609 0.270 ;
    END
  END w0_wd_in[424]
  PIN w0_wd_in[425]
    DIRECTION INPUT ;
    USE SIGNAL ;
    SHAPE ABUTMENT ;
    PORT
      LAYER M2 ;
      RECT 48.879 0.000 48.897 0.270 ;
    END
  END w0_wd_in[425]
  PIN w0_wd_in[426]
    DIRECTION INPUT ;
    USE SIGNAL ;
    SHAPE ABUTMENT ;
    PORT
      LAYER M2 ;
      RECT 49.167 0.000 49.185 0.270 ;
    END
  END w0_wd_in[426]
  PIN w0_wd_in[427]
    DIRECTION INPUT ;
    USE SIGNAL ;
    SHAPE ABUTMENT ;
    PORT
      LAYER M2 ;
      RECT 49.455 0.000 49.473 0.270 ;
    END
  END w0_wd_in[427]
  PIN w0_wd_in[428]
    DIRECTION INPUT ;
    USE SIGNAL ;
    SHAPE ABUTMENT ;
    PORT
      LAYER M2 ;
      RECT 49.743 0.000 49.761 0.270 ;
    END
  END w0_wd_in[428]
  PIN w0_wd_in[429]
    DIRECTION INPUT ;
    USE SIGNAL ;
    SHAPE ABUTMENT ;
    PORT
      LAYER M2 ;
      RECT 50.031 0.000 50.049 0.270 ;
    END
  END w0_wd_in[429]
  PIN w0_wd_in[430]
    DIRECTION INPUT ;
    USE SIGNAL ;
    SHAPE ABUTMENT ;
    PORT
      LAYER M2 ;
      RECT 50.319 0.000 50.337 0.270 ;
    END
  END w0_wd_in[430]
  PIN w0_wd_in[431]
    DIRECTION INPUT ;
    USE SIGNAL ;
    SHAPE ABUTMENT ;
    PORT
      LAYER M2 ;
      RECT 50.607 0.000 50.625 0.270 ;
    END
  END w0_wd_in[431]
  PIN w0_wd_in[432]
    DIRECTION INPUT ;
    USE SIGNAL ;
    SHAPE ABUTMENT ;
    PORT
      LAYER M2 ;
      RECT 50.895 0.000 50.913 0.270 ;
    END
  END w0_wd_in[432]
  PIN w0_wd_in[433]
    DIRECTION INPUT ;
    USE SIGNAL ;
    SHAPE ABUTMENT ;
    PORT
      LAYER M2 ;
      RECT 51.183 0.000 51.201 0.270 ;
    END
  END w0_wd_in[433]
  PIN w0_wd_in[434]
    DIRECTION INPUT ;
    USE SIGNAL ;
    SHAPE ABUTMENT ;
    PORT
      LAYER M2 ;
      RECT 51.471 0.000 51.489 0.270 ;
    END
  END w0_wd_in[434]
  PIN w0_wd_in[435]
    DIRECTION INPUT ;
    USE SIGNAL ;
    SHAPE ABUTMENT ;
    PORT
      LAYER M2 ;
      RECT 51.759 0.000 51.777 0.270 ;
    END
  END w0_wd_in[435]
  PIN w0_wd_in[436]
    DIRECTION INPUT ;
    USE SIGNAL ;
    SHAPE ABUTMENT ;
    PORT
      LAYER M2 ;
      RECT 52.047 0.000 52.065 0.270 ;
    END
  END w0_wd_in[436]
  PIN w0_wd_in[437]
    DIRECTION INPUT ;
    USE SIGNAL ;
    SHAPE ABUTMENT ;
    PORT
      LAYER M2 ;
      RECT 52.335 0.000 52.353 0.270 ;
    END
  END w0_wd_in[437]
  PIN w0_wd_in[438]
    DIRECTION INPUT ;
    USE SIGNAL ;
    SHAPE ABUTMENT ;
    PORT
      LAYER M2 ;
      RECT 52.623 0.000 52.641 0.270 ;
    END
  END w0_wd_in[438]
  PIN w0_wd_in[439]
    DIRECTION INPUT ;
    USE SIGNAL ;
    SHAPE ABUTMENT ;
    PORT
      LAYER M2 ;
      RECT 52.911 0.000 52.929 0.270 ;
    END
  END w0_wd_in[439]
  PIN w0_wd_in[440]
    DIRECTION INPUT ;
    USE SIGNAL ;
    SHAPE ABUTMENT ;
    PORT
      LAYER M2 ;
      RECT 53.199 0.000 53.217 0.270 ;
    END
  END w0_wd_in[440]
  PIN w0_wd_in[441]
    DIRECTION INPUT ;
    USE SIGNAL ;
    SHAPE ABUTMENT ;
    PORT
      LAYER M2 ;
      RECT 53.487 0.000 53.505 0.270 ;
    END
  END w0_wd_in[441]
  PIN w0_wd_in[442]
    DIRECTION INPUT ;
    USE SIGNAL ;
    SHAPE ABUTMENT ;
    PORT
      LAYER M2 ;
      RECT 53.775 0.000 53.793 0.270 ;
    END
  END w0_wd_in[442]
  PIN w0_wd_in[443]
    DIRECTION INPUT ;
    USE SIGNAL ;
    SHAPE ABUTMENT ;
    PORT
      LAYER M2 ;
      RECT 54.063 0.000 54.081 0.270 ;
    END
  END w0_wd_in[443]
  PIN w0_wd_in[444]
    DIRECTION INPUT ;
    USE SIGNAL ;
    SHAPE ABUTMENT ;
    PORT
      LAYER M2 ;
      RECT 54.351 0.000 54.369 0.270 ;
    END
  END w0_wd_in[444]
  PIN w0_wd_in[445]
    DIRECTION INPUT ;
    USE SIGNAL ;
    SHAPE ABUTMENT ;
    PORT
      LAYER M2 ;
      RECT 54.639 0.000 54.657 0.270 ;
    END
  END w0_wd_in[445]
  PIN w0_wd_in[446]
    DIRECTION INPUT ;
    USE SIGNAL ;
    SHAPE ABUTMENT ;
    PORT
      LAYER M2 ;
      RECT 54.927 0.000 54.945 0.270 ;
    END
  END w0_wd_in[446]
  PIN w0_wd_in[447]
    DIRECTION INPUT ;
    USE SIGNAL ;
    SHAPE ABUTMENT ;
    PORT
      LAYER M2 ;
      RECT 55.215 0.000 55.233 0.270 ;
    END
  END w0_wd_in[447]
  PIN w0_wd_in[448]
    DIRECTION INPUT ;
    USE SIGNAL ;
    SHAPE ABUTMENT ;
    PORT
      LAYER M2 ;
      RECT 55.503 0.000 55.521 0.270 ;
    END
  END w0_wd_in[448]
  PIN w0_wd_in[449]
    DIRECTION INPUT ;
    USE SIGNAL ;
    SHAPE ABUTMENT ;
    PORT
      LAYER M2 ;
      RECT 55.791 0.000 55.809 0.270 ;
    END
  END w0_wd_in[449]
  PIN w0_wd_in[450]
    DIRECTION INPUT ;
    USE SIGNAL ;
    SHAPE ABUTMENT ;
    PORT
      LAYER M2 ;
      RECT 56.079 0.000 56.097 0.270 ;
    END
  END w0_wd_in[450]
  PIN w0_wd_in[451]
    DIRECTION INPUT ;
    USE SIGNAL ;
    SHAPE ABUTMENT ;
    PORT
      LAYER M2 ;
      RECT 56.367 0.000 56.385 0.270 ;
    END
  END w0_wd_in[451]
  PIN w0_wd_in[452]
    DIRECTION INPUT ;
    USE SIGNAL ;
    SHAPE ABUTMENT ;
    PORT
      LAYER M2 ;
      RECT 56.655 0.000 56.673 0.270 ;
    END
  END w0_wd_in[452]
  PIN w0_wd_in[453]
    DIRECTION INPUT ;
    USE SIGNAL ;
    SHAPE ABUTMENT ;
    PORT
      LAYER M2 ;
      RECT 56.943 0.000 56.961 0.270 ;
    END
  END w0_wd_in[453]
  PIN w0_wd_in[454]
    DIRECTION INPUT ;
    USE SIGNAL ;
    SHAPE ABUTMENT ;
    PORT
      LAYER M2 ;
      RECT 57.231 0.000 57.249 0.270 ;
    END
  END w0_wd_in[454]
  PIN w0_wd_in[455]
    DIRECTION INPUT ;
    USE SIGNAL ;
    SHAPE ABUTMENT ;
    PORT
      LAYER M2 ;
      RECT 57.519 0.000 57.537 0.270 ;
    END
  END w0_wd_in[455]
  PIN w0_wd_in[456]
    DIRECTION INPUT ;
    USE SIGNAL ;
    SHAPE ABUTMENT ;
    PORT
      LAYER M2 ;
      RECT 57.807 0.000 57.825 0.270 ;
    END
  END w0_wd_in[456]
  PIN w0_wd_in[457]
    DIRECTION INPUT ;
    USE SIGNAL ;
    SHAPE ABUTMENT ;
    PORT
      LAYER M2 ;
      RECT 58.095 0.000 58.113 0.270 ;
    END
  END w0_wd_in[457]
  PIN w0_wd_in[458]
    DIRECTION INPUT ;
    USE SIGNAL ;
    SHAPE ABUTMENT ;
    PORT
      LAYER M2 ;
      RECT 58.383 0.000 58.401 0.270 ;
    END
  END w0_wd_in[458]
  PIN w0_wd_in[459]
    DIRECTION INPUT ;
    USE SIGNAL ;
    SHAPE ABUTMENT ;
    PORT
      LAYER M2 ;
      RECT 58.671 0.000 58.689 0.270 ;
    END
  END w0_wd_in[459]
  PIN w0_wd_in[460]
    DIRECTION INPUT ;
    USE SIGNAL ;
    SHAPE ABUTMENT ;
    PORT
      LAYER M2 ;
      RECT 58.959 0.000 58.977 0.270 ;
    END
  END w0_wd_in[460]
  PIN w0_wd_in[461]
    DIRECTION INPUT ;
    USE SIGNAL ;
    SHAPE ABUTMENT ;
    PORT
      LAYER M2 ;
      RECT 59.247 0.000 59.265 0.270 ;
    END
  END w0_wd_in[461]
  PIN w0_wd_in[462]
    DIRECTION INPUT ;
    USE SIGNAL ;
    SHAPE ABUTMENT ;
    PORT
      LAYER M2 ;
      RECT 59.535 0.000 59.553 0.270 ;
    END
  END w0_wd_in[462]
  PIN w0_wd_in[463]
    DIRECTION INPUT ;
    USE SIGNAL ;
    SHAPE ABUTMENT ;
    PORT
      LAYER M2 ;
      RECT 59.823 0.000 59.841 0.270 ;
    END
  END w0_wd_in[463]
  PIN w0_wd_in[464]
    DIRECTION INPUT ;
    USE SIGNAL ;
    SHAPE ABUTMENT ;
    PORT
      LAYER M2 ;
      RECT 60.111 0.000 60.129 0.270 ;
    END
  END w0_wd_in[464]
  PIN w0_wd_in[465]
    DIRECTION INPUT ;
    USE SIGNAL ;
    SHAPE ABUTMENT ;
    PORT
      LAYER M2 ;
      RECT 60.399 0.000 60.417 0.270 ;
    END
  END w0_wd_in[465]
  PIN w0_wd_in[466]
    DIRECTION INPUT ;
    USE SIGNAL ;
    SHAPE ABUTMENT ;
    PORT
      LAYER M2 ;
      RECT 60.687 0.000 60.705 0.270 ;
    END
  END w0_wd_in[466]
  PIN w0_wd_in[467]
    DIRECTION INPUT ;
    USE SIGNAL ;
    SHAPE ABUTMENT ;
    PORT
      LAYER M2 ;
      RECT 60.975 0.000 60.993 0.270 ;
    END
  END w0_wd_in[467]
  PIN w0_wd_in[468]
    DIRECTION INPUT ;
    USE SIGNAL ;
    SHAPE ABUTMENT ;
    PORT
      LAYER M2 ;
      RECT 61.263 0.000 61.281 0.270 ;
    END
  END w0_wd_in[468]
  PIN w0_wd_in[469]
    DIRECTION INPUT ;
    USE SIGNAL ;
    SHAPE ABUTMENT ;
    PORT
      LAYER M2 ;
      RECT 61.551 0.000 61.569 0.270 ;
    END
  END w0_wd_in[469]
  PIN w0_wd_in[470]
    DIRECTION INPUT ;
    USE SIGNAL ;
    SHAPE ABUTMENT ;
    PORT
      LAYER M2 ;
      RECT 61.839 0.000 61.857 0.270 ;
    END
  END w0_wd_in[470]
  PIN w0_wd_in[471]
    DIRECTION INPUT ;
    USE SIGNAL ;
    SHAPE ABUTMENT ;
    PORT
      LAYER M2 ;
      RECT 62.127 0.000 62.145 0.270 ;
    END
  END w0_wd_in[471]
  PIN w0_wd_in[472]
    DIRECTION INPUT ;
    USE SIGNAL ;
    SHAPE ABUTMENT ;
    PORT
      LAYER M2 ;
      RECT 62.415 0.000 62.433 0.270 ;
    END
  END w0_wd_in[472]
  PIN w0_wd_in[473]
    DIRECTION INPUT ;
    USE SIGNAL ;
    SHAPE ABUTMENT ;
    PORT
      LAYER M2 ;
      RECT 62.703 0.000 62.721 0.270 ;
    END
  END w0_wd_in[473]
  PIN w0_wd_in[474]
    DIRECTION INPUT ;
    USE SIGNAL ;
    SHAPE ABUTMENT ;
    PORT
      LAYER M2 ;
      RECT 62.991 0.000 63.009 0.270 ;
    END
  END w0_wd_in[474]
  PIN w0_wd_in[475]
    DIRECTION INPUT ;
    USE SIGNAL ;
    SHAPE ABUTMENT ;
    PORT
      LAYER M2 ;
      RECT 63.279 0.000 63.297 0.270 ;
    END
  END w0_wd_in[475]
  PIN w0_wd_in[476]
    DIRECTION INPUT ;
    USE SIGNAL ;
    SHAPE ABUTMENT ;
    PORT
      LAYER M2 ;
      RECT 63.567 0.000 63.585 0.270 ;
    END
  END w0_wd_in[476]
  PIN w0_wd_in[477]
    DIRECTION INPUT ;
    USE SIGNAL ;
    SHAPE ABUTMENT ;
    PORT
      LAYER M2 ;
      RECT 63.855 0.000 63.873 0.270 ;
    END
  END w0_wd_in[477]
  PIN w0_wd_in[478]
    DIRECTION INPUT ;
    USE SIGNAL ;
    SHAPE ABUTMENT ;
    PORT
      LAYER M2 ;
      RECT 64.143 0.000 64.161 0.270 ;
    END
  END w0_wd_in[478]
  PIN w0_wd_in[479]
    DIRECTION INPUT ;
    USE SIGNAL ;
    SHAPE ABUTMENT ;
    PORT
      LAYER M2 ;
      RECT 64.431 0.000 64.449 0.270 ;
    END
  END w0_wd_in[479]
  PIN w0_wd_in[480]
    DIRECTION INPUT ;
    USE SIGNAL ;
    SHAPE ABUTMENT ;
    PORT
      LAYER M2 ;
      RECT 64.719 0.000 64.737 0.270 ;
    END
  END w0_wd_in[480]
  PIN w0_wd_in[481]
    DIRECTION INPUT ;
    USE SIGNAL ;
    SHAPE ABUTMENT ;
    PORT
      LAYER M2 ;
      RECT 65.007 0.000 65.025 0.270 ;
    END
  END w0_wd_in[481]
  PIN w0_wd_in[482]
    DIRECTION INPUT ;
    USE SIGNAL ;
    SHAPE ABUTMENT ;
    PORT
      LAYER M2 ;
      RECT 65.295 0.000 65.313 0.270 ;
    END
  END w0_wd_in[482]
  PIN w0_wd_in[483]
    DIRECTION INPUT ;
    USE SIGNAL ;
    SHAPE ABUTMENT ;
    PORT
      LAYER M2 ;
      RECT 65.583 0.000 65.601 0.270 ;
    END
  END w0_wd_in[483]
  PIN w0_wd_in[484]
    DIRECTION INPUT ;
    USE SIGNAL ;
    SHAPE ABUTMENT ;
    PORT
      LAYER M2 ;
      RECT 65.871 0.000 65.889 0.270 ;
    END
  END w0_wd_in[484]
  PIN w0_wd_in[485]
    DIRECTION INPUT ;
    USE SIGNAL ;
    SHAPE ABUTMENT ;
    PORT
      LAYER M2 ;
      RECT 66.159 0.000 66.177 0.270 ;
    END
  END w0_wd_in[485]
  PIN w0_wd_in[486]
    DIRECTION INPUT ;
    USE SIGNAL ;
    SHAPE ABUTMENT ;
    PORT
      LAYER M2 ;
      RECT 66.447 0.000 66.465 0.270 ;
    END
  END w0_wd_in[486]
  PIN w0_wd_in[487]
    DIRECTION INPUT ;
    USE SIGNAL ;
    SHAPE ABUTMENT ;
    PORT
      LAYER M2 ;
      RECT 66.735 0.000 66.753 0.270 ;
    END
  END w0_wd_in[487]
  PIN w0_wd_in[488]
    DIRECTION INPUT ;
    USE SIGNAL ;
    SHAPE ABUTMENT ;
    PORT
      LAYER M2 ;
      RECT 67.023 0.000 67.041 0.270 ;
    END
  END w0_wd_in[488]
  PIN w0_wd_in[489]
    DIRECTION INPUT ;
    USE SIGNAL ;
    SHAPE ABUTMENT ;
    PORT
      LAYER M2 ;
      RECT 67.311 0.000 67.329 0.270 ;
    END
  END w0_wd_in[489]
  PIN w0_wd_in[490]
    DIRECTION INPUT ;
    USE SIGNAL ;
    SHAPE ABUTMENT ;
    PORT
      LAYER M2 ;
      RECT 67.599 0.000 67.617 0.270 ;
    END
  END w0_wd_in[490]
  PIN w0_wd_in[491]
    DIRECTION INPUT ;
    USE SIGNAL ;
    SHAPE ABUTMENT ;
    PORT
      LAYER M2 ;
      RECT 67.887 0.000 67.905 0.270 ;
    END
  END w0_wd_in[491]
  PIN w0_wd_in[492]
    DIRECTION INPUT ;
    USE SIGNAL ;
    SHAPE ABUTMENT ;
    PORT
      LAYER M2 ;
      RECT 68.175 0.000 68.193 0.270 ;
    END
  END w0_wd_in[492]
  PIN w0_wd_in[493]
    DIRECTION INPUT ;
    USE SIGNAL ;
    SHAPE ABUTMENT ;
    PORT
      LAYER M2 ;
      RECT 68.463 0.000 68.481 0.270 ;
    END
  END w0_wd_in[493]
  PIN w0_wd_in[494]
    DIRECTION INPUT ;
    USE SIGNAL ;
    SHAPE ABUTMENT ;
    PORT
      LAYER M2 ;
      RECT 68.751 0.000 68.769 0.270 ;
    END
  END w0_wd_in[494]
  PIN w0_wd_in[495]
    DIRECTION INPUT ;
    USE SIGNAL ;
    SHAPE ABUTMENT ;
    PORT
      LAYER M2 ;
      RECT 69.039 0.000 69.057 0.270 ;
    END
  END w0_wd_in[495]
  PIN w0_wd_in[496]
    DIRECTION INPUT ;
    USE SIGNAL ;
    SHAPE ABUTMENT ;
    PORT
      LAYER M2 ;
      RECT 69.327 0.000 69.345 0.270 ;
    END
  END w0_wd_in[496]
  PIN w0_wd_in[497]
    DIRECTION INPUT ;
    USE SIGNAL ;
    SHAPE ABUTMENT ;
    PORT
      LAYER M2 ;
      RECT 69.615 0.000 69.633 0.270 ;
    END
  END w0_wd_in[497]
  PIN w0_wd_in[498]
    DIRECTION INPUT ;
    USE SIGNAL ;
    SHAPE ABUTMENT ;
    PORT
      LAYER M2 ;
      RECT 69.903 0.000 69.921 0.270 ;
    END
  END w0_wd_in[498]
  PIN w0_wd_in[499]
    DIRECTION INPUT ;
    USE SIGNAL ;
    SHAPE ABUTMENT ;
    PORT
      LAYER M2 ;
      RECT 70.191 0.000 70.209 0.270 ;
    END
  END w0_wd_in[499]
  PIN w0_wd_in[500]
    DIRECTION INPUT ;
    USE SIGNAL ;
    SHAPE ABUTMENT ;
    PORT
      LAYER M2 ;
      RECT 70.479 0.000 70.497 0.270 ;
    END
  END w0_wd_in[500]
  PIN w0_wd_in[501]
    DIRECTION INPUT ;
    USE SIGNAL ;
    SHAPE ABUTMENT ;
    PORT
      LAYER M2 ;
      RECT 70.767 0.000 70.785 0.270 ;
    END
  END w0_wd_in[501]
  PIN w0_wd_in[502]
    DIRECTION INPUT ;
    USE SIGNAL ;
    SHAPE ABUTMENT ;
    PORT
      LAYER M2 ;
      RECT 71.055 0.000 71.073 0.270 ;
    END
  END w0_wd_in[502]
  PIN w0_wd_in[503]
    DIRECTION INPUT ;
    USE SIGNAL ;
    SHAPE ABUTMENT ;
    PORT
      LAYER M2 ;
      RECT 71.343 0.000 71.361 0.270 ;
    END
  END w0_wd_in[503]
  PIN w0_wd_in[504]
    DIRECTION INPUT ;
    USE SIGNAL ;
    SHAPE ABUTMENT ;
    PORT
      LAYER M2 ;
      RECT 71.631 0.000 71.649 0.270 ;
    END
  END w0_wd_in[504]
  PIN w0_wd_in[505]
    DIRECTION INPUT ;
    USE SIGNAL ;
    SHAPE ABUTMENT ;
    PORT
      LAYER M2 ;
      RECT 71.919 0.000 71.937 0.270 ;
    END
  END w0_wd_in[505]
  PIN w0_wd_in[506]
    DIRECTION INPUT ;
    USE SIGNAL ;
    SHAPE ABUTMENT ;
    PORT
      LAYER M2 ;
      RECT 72.207 0.000 72.225 0.270 ;
    END
  END w0_wd_in[506]
  PIN w0_wd_in[507]
    DIRECTION INPUT ;
    USE SIGNAL ;
    SHAPE ABUTMENT ;
    PORT
      LAYER M2 ;
      RECT 72.495 0.000 72.513 0.270 ;
    END
  END w0_wd_in[507]
  PIN w0_wd_in[508]
    DIRECTION INPUT ;
    USE SIGNAL ;
    SHAPE ABUTMENT ;
    PORT
      LAYER M2 ;
      RECT 72.783 0.000 72.801 0.270 ;
    END
  END w0_wd_in[508]
  PIN w0_wd_in[509]
    DIRECTION INPUT ;
    USE SIGNAL ;
    SHAPE ABUTMENT ;
    PORT
      LAYER M2 ;
      RECT 73.071 0.000 73.089 0.270 ;
    END
  END w0_wd_in[509]
  PIN w0_wd_in[510]
    DIRECTION INPUT ;
    USE SIGNAL ;
    SHAPE ABUTMENT ;
    PORT
      LAYER M2 ;
      RECT 73.359 0.000 73.377 0.270 ;
    END
  END w0_wd_in[510]
  PIN w0_wd_in[511]
    DIRECTION INPUT ;
    USE SIGNAL ;
    SHAPE ABUTMENT ;
    PORT
      LAYER M2 ;
      RECT 73.647 0.000 73.665 0.270 ;
    END
  END w0_wd_in[511]
  PIN r0_rd_out[0]
    DIRECTION OUTPUT ;
    USE SIGNAL ;
    SHAPE ABUTMENT ;
    PORT
      LAYER M2 ;
      RECT 73.935 0.000 73.953 0.270 ;
    END
  END r0_rd_out[0]
  PIN r0_rd_out[1]
    DIRECTION OUTPUT ;
    USE SIGNAL ;
    SHAPE ABUTMENT ;
    PORT
      LAYER M2 ;
      RECT 74.223 0.000 74.241 0.270 ;
    END
  END r0_rd_out[1]
  PIN r0_rd_out[2]
    DIRECTION OUTPUT ;
    USE SIGNAL ;
    SHAPE ABUTMENT ;
    PORT
      LAYER M2 ;
      RECT 74.511 0.000 74.529 0.270 ;
    END
  END r0_rd_out[2]
  PIN r0_rd_out[3]
    DIRECTION OUTPUT ;
    USE SIGNAL ;
    SHAPE ABUTMENT ;
    PORT
      LAYER M2 ;
      RECT 74.799 0.000 74.817 0.270 ;
    END
  END r0_rd_out[3]
  PIN r0_rd_out[4]
    DIRECTION OUTPUT ;
    USE SIGNAL ;
    SHAPE ABUTMENT ;
    PORT
      LAYER M2 ;
      RECT 75.087 0.000 75.105 0.270 ;
    END
  END r0_rd_out[4]
  PIN r0_rd_out[5]
    DIRECTION OUTPUT ;
    USE SIGNAL ;
    SHAPE ABUTMENT ;
    PORT
      LAYER M2 ;
      RECT 75.375 0.000 75.393 0.270 ;
    END
  END r0_rd_out[5]
  PIN r0_rd_out[6]
    DIRECTION OUTPUT ;
    USE SIGNAL ;
    SHAPE ABUTMENT ;
    PORT
      LAYER M2 ;
      RECT 75.663 0.000 75.681 0.270 ;
    END
  END r0_rd_out[6]
  PIN r0_rd_out[7]
    DIRECTION OUTPUT ;
    USE SIGNAL ;
    SHAPE ABUTMENT ;
    PORT
      LAYER M2 ;
      RECT 75.951 0.000 75.969 0.270 ;
    END
  END r0_rd_out[7]
  PIN r0_rd_out[8]
    DIRECTION OUTPUT ;
    USE SIGNAL ;
    SHAPE ABUTMENT ;
    PORT
      LAYER M2 ;
      RECT 76.239 0.000 76.257 0.270 ;
    END
  END r0_rd_out[8]
  PIN r0_rd_out[9]
    DIRECTION OUTPUT ;
    USE SIGNAL ;
    SHAPE ABUTMENT ;
    PORT
      LAYER M2 ;
      RECT 76.527 0.000 76.545 0.270 ;
    END
  END r0_rd_out[9]
  PIN r0_rd_out[10]
    DIRECTION OUTPUT ;
    USE SIGNAL ;
    SHAPE ABUTMENT ;
    PORT
      LAYER M2 ;
      RECT 76.815 0.000 76.833 0.270 ;
    END
  END r0_rd_out[10]
  PIN r0_rd_out[11]
    DIRECTION OUTPUT ;
    USE SIGNAL ;
    SHAPE ABUTMENT ;
    PORT
      LAYER M2 ;
      RECT 77.103 0.000 77.121 0.270 ;
    END
  END r0_rd_out[11]
  PIN r0_rd_out[12]
    DIRECTION OUTPUT ;
    USE SIGNAL ;
    SHAPE ABUTMENT ;
    PORT
      LAYER M2 ;
      RECT 77.391 0.000 77.409 0.270 ;
    END
  END r0_rd_out[12]
  PIN r0_rd_out[13]
    DIRECTION OUTPUT ;
    USE SIGNAL ;
    SHAPE ABUTMENT ;
    PORT
      LAYER M2 ;
      RECT 77.679 0.000 77.697 0.270 ;
    END
  END r0_rd_out[13]
  PIN r0_rd_out[14]
    DIRECTION OUTPUT ;
    USE SIGNAL ;
    SHAPE ABUTMENT ;
    PORT
      LAYER M2 ;
      RECT 77.967 0.000 77.985 0.270 ;
    END
  END r0_rd_out[14]
  PIN r0_rd_out[15]
    DIRECTION OUTPUT ;
    USE SIGNAL ;
    SHAPE ABUTMENT ;
    PORT
      LAYER M2 ;
      RECT 78.255 0.000 78.273 0.270 ;
    END
  END r0_rd_out[15]
  PIN r0_rd_out[16]
    DIRECTION OUTPUT ;
    USE SIGNAL ;
    SHAPE ABUTMENT ;
    PORT
      LAYER M2 ;
      RECT 78.543 0.000 78.561 0.270 ;
    END
  END r0_rd_out[16]
  PIN r0_rd_out[17]
    DIRECTION OUTPUT ;
    USE SIGNAL ;
    SHAPE ABUTMENT ;
    PORT
      LAYER M2 ;
      RECT 78.831 0.000 78.849 0.270 ;
    END
  END r0_rd_out[17]
  PIN r0_rd_out[18]
    DIRECTION OUTPUT ;
    USE SIGNAL ;
    SHAPE ABUTMENT ;
    PORT
      LAYER M2 ;
      RECT 79.119 0.000 79.137 0.270 ;
    END
  END r0_rd_out[18]
  PIN r0_rd_out[19]
    DIRECTION OUTPUT ;
    USE SIGNAL ;
    SHAPE ABUTMENT ;
    PORT
      LAYER M2 ;
      RECT 79.407 0.000 79.425 0.270 ;
    END
  END r0_rd_out[19]
  PIN r0_rd_out[20]
    DIRECTION OUTPUT ;
    USE SIGNAL ;
    SHAPE ABUTMENT ;
    PORT
      LAYER M2 ;
      RECT 79.695 0.000 79.713 0.270 ;
    END
  END r0_rd_out[20]
  PIN r0_rd_out[21]
    DIRECTION OUTPUT ;
    USE SIGNAL ;
    SHAPE ABUTMENT ;
    PORT
      LAYER M2 ;
      RECT 79.983 0.000 80.001 0.270 ;
    END
  END r0_rd_out[21]
  PIN r0_rd_out[22]
    DIRECTION OUTPUT ;
    USE SIGNAL ;
    SHAPE ABUTMENT ;
    PORT
      LAYER M2 ;
      RECT 80.271 0.000 80.289 0.270 ;
    END
  END r0_rd_out[22]
  PIN r0_rd_out[23]
    DIRECTION OUTPUT ;
    USE SIGNAL ;
    SHAPE ABUTMENT ;
    PORT
      LAYER M2 ;
      RECT 80.559 0.000 80.577 0.270 ;
    END
  END r0_rd_out[23]
  PIN r0_rd_out[24]
    DIRECTION OUTPUT ;
    USE SIGNAL ;
    SHAPE ABUTMENT ;
    PORT
      LAYER M2 ;
      RECT 80.847 0.000 80.865 0.270 ;
    END
  END r0_rd_out[24]
  PIN r0_rd_out[25]
    DIRECTION OUTPUT ;
    USE SIGNAL ;
    SHAPE ABUTMENT ;
    PORT
      LAYER M2 ;
      RECT 81.135 0.000 81.153 0.270 ;
    END
  END r0_rd_out[25]
  PIN r0_rd_out[26]
    DIRECTION OUTPUT ;
    USE SIGNAL ;
    SHAPE ABUTMENT ;
    PORT
      LAYER M2 ;
      RECT 81.423 0.000 81.441 0.270 ;
    END
  END r0_rd_out[26]
  PIN r0_rd_out[27]
    DIRECTION OUTPUT ;
    USE SIGNAL ;
    SHAPE ABUTMENT ;
    PORT
      LAYER M2 ;
      RECT 81.711 0.000 81.729 0.270 ;
    END
  END r0_rd_out[27]
  PIN r0_rd_out[28]
    DIRECTION OUTPUT ;
    USE SIGNAL ;
    SHAPE ABUTMENT ;
    PORT
      LAYER M2 ;
      RECT 81.999 0.000 82.017 0.270 ;
    END
  END r0_rd_out[28]
  PIN r0_rd_out[29]
    DIRECTION OUTPUT ;
    USE SIGNAL ;
    SHAPE ABUTMENT ;
    PORT
      LAYER M2 ;
      RECT 82.287 0.000 82.305 0.270 ;
    END
  END r0_rd_out[29]
  PIN r0_rd_out[30]
    DIRECTION OUTPUT ;
    USE SIGNAL ;
    SHAPE ABUTMENT ;
    PORT
      LAYER M2 ;
      RECT 82.575 0.000 82.593 0.270 ;
    END
  END r0_rd_out[30]
  PIN r0_rd_out[31]
    DIRECTION OUTPUT ;
    USE SIGNAL ;
    SHAPE ABUTMENT ;
    PORT
      LAYER M2 ;
      RECT 82.863 0.000 82.881 0.270 ;
    END
  END r0_rd_out[31]
  PIN r0_rd_out[32]
    DIRECTION OUTPUT ;
    USE SIGNAL ;
    SHAPE ABUTMENT ;
    PORT
      LAYER M2 ;
      RECT 83.151 0.000 83.169 0.270 ;
    END
  END r0_rd_out[32]
  PIN r0_rd_out[33]
    DIRECTION OUTPUT ;
    USE SIGNAL ;
    SHAPE ABUTMENT ;
    PORT
      LAYER M2 ;
      RECT 83.439 0.000 83.457 0.270 ;
    END
  END r0_rd_out[33]
  PIN r0_rd_out[34]
    DIRECTION OUTPUT ;
    USE SIGNAL ;
    SHAPE ABUTMENT ;
    PORT
      LAYER M2 ;
      RECT 83.727 0.000 83.745 0.270 ;
    END
  END r0_rd_out[34]
  PIN r0_rd_out[35]
    DIRECTION OUTPUT ;
    USE SIGNAL ;
    SHAPE ABUTMENT ;
    PORT
      LAYER M2 ;
      RECT 84.015 0.000 84.033 0.270 ;
    END
  END r0_rd_out[35]
  PIN r0_rd_out[36]
    DIRECTION OUTPUT ;
    USE SIGNAL ;
    SHAPE ABUTMENT ;
    PORT
      LAYER M2 ;
      RECT 84.303 0.000 84.321 0.270 ;
    END
  END r0_rd_out[36]
  PIN r0_rd_out[37]
    DIRECTION OUTPUT ;
    USE SIGNAL ;
    SHAPE ABUTMENT ;
    PORT
      LAYER M2 ;
      RECT 84.591 0.000 84.609 0.270 ;
    END
  END r0_rd_out[37]
  PIN r0_rd_out[38]
    DIRECTION OUTPUT ;
    USE SIGNAL ;
    SHAPE ABUTMENT ;
    PORT
      LAYER M2 ;
      RECT 84.879 0.000 84.897 0.270 ;
    END
  END r0_rd_out[38]
  PIN r0_rd_out[39]
    DIRECTION OUTPUT ;
    USE SIGNAL ;
    SHAPE ABUTMENT ;
    PORT
      LAYER M2 ;
      RECT 85.167 0.000 85.185 0.270 ;
    END
  END r0_rd_out[39]
  PIN r0_rd_out[40]
    DIRECTION OUTPUT ;
    USE SIGNAL ;
    SHAPE ABUTMENT ;
    PORT
      LAYER M2 ;
      RECT 85.455 0.000 85.473 0.270 ;
    END
  END r0_rd_out[40]
  PIN r0_rd_out[41]
    DIRECTION OUTPUT ;
    USE SIGNAL ;
    SHAPE ABUTMENT ;
    PORT
      LAYER M2 ;
      RECT 85.743 0.000 85.761 0.270 ;
    END
  END r0_rd_out[41]
  PIN r0_rd_out[42]
    DIRECTION OUTPUT ;
    USE SIGNAL ;
    SHAPE ABUTMENT ;
    PORT
      LAYER M2 ;
      RECT 86.031 0.000 86.049 0.270 ;
    END
  END r0_rd_out[42]
  PIN r0_rd_out[43]
    DIRECTION OUTPUT ;
    USE SIGNAL ;
    SHAPE ABUTMENT ;
    PORT
      LAYER M2 ;
      RECT 86.319 0.000 86.337 0.270 ;
    END
  END r0_rd_out[43]
  PIN r0_rd_out[44]
    DIRECTION OUTPUT ;
    USE SIGNAL ;
    SHAPE ABUTMENT ;
    PORT
      LAYER M2 ;
      RECT 86.607 0.000 86.625 0.270 ;
    END
  END r0_rd_out[44]
  PIN r0_rd_out[45]
    DIRECTION OUTPUT ;
    USE SIGNAL ;
    SHAPE ABUTMENT ;
    PORT
      LAYER M2 ;
      RECT 86.895 0.000 86.913 0.270 ;
    END
  END r0_rd_out[45]
  PIN r0_rd_out[46]
    DIRECTION OUTPUT ;
    USE SIGNAL ;
    SHAPE ABUTMENT ;
    PORT
      LAYER M2 ;
      RECT 87.183 0.000 87.201 0.270 ;
    END
  END r0_rd_out[46]
  PIN r0_rd_out[47]
    DIRECTION OUTPUT ;
    USE SIGNAL ;
    SHAPE ABUTMENT ;
    PORT
      LAYER M2 ;
      RECT 87.471 0.000 87.489 0.270 ;
    END
  END r0_rd_out[47]
  PIN r0_rd_out[48]
    DIRECTION OUTPUT ;
    USE SIGNAL ;
    SHAPE ABUTMENT ;
    PORT
      LAYER M2 ;
      RECT 87.759 0.000 87.777 0.270 ;
    END
  END r0_rd_out[48]
  PIN r0_rd_out[49]
    DIRECTION OUTPUT ;
    USE SIGNAL ;
    SHAPE ABUTMENT ;
    PORT
      LAYER M2 ;
      RECT 88.047 0.000 88.065 0.270 ;
    END
  END r0_rd_out[49]
  PIN r0_rd_out[50]
    DIRECTION OUTPUT ;
    USE SIGNAL ;
    SHAPE ABUTMENT ;
    PORT
      LAYER M2 ;
      RECT 88.335 0.000 88.353 0.270 ;
    END
  END r0_rd_out[50]
  PIN r0_rd_out[51]
    DIRECTION OUTPUT ;
    USE SIGNAL ;
    SHAPE ABUTMENT ;
    PORT
      LAYER M2 ;
      RECT 88.623 0.000 88.641 0.270 ;
    END
  END r0_rd_out[51]
  PIN r0_rd_out[52]
    DIRECTION OUTPUT ;
    USE SIGNAL ;
    SHAPE ABUTMENT ;
    PORT
      LAYER M2 ;
      RECT 88.911 0.000 88.929 0.270 ;
    END
  END r0_rd_out[52]
  PIN r0_rd_out[53]
    DIRECTION OUTPUT ;
    USE SIGNAL ;
    SHAPE ABUTMENT ;
    PORT
      LAYER M2 ;
      RECT 89.199 0.000 89.217 0.270 ;
    END
  END r0_rd_out[53]
  PIN r0_rd_out[54]
    DIRECTION OUTPUT ;
    USE SIGNAL ;
    SHAPE ABUTMENT ;
    PORT
      LAYER M2 ;
      RECT 89.487 0.000 89.505 0.270 ;
    END
  END r0_rd_out[54]
  PIN r0_rd_out[55]
    DIRECTION OUTPUT ;
    USE SIGNAL ;
    SHAPE ABUTMENT ;
    PORT
      LAYER M2 ;
      RECT 89.775 0.000 89.793 0.270 ;
    END
  END r0_rd_out[55]
  PIN r0_rd_out[56]
    DIRECTION OUTPUT ;
    USE SIGNAL ;
    SHAPE ABUTMENT ;
    PORT
      LAYER M2 ;
      RECT 90.063 0.000 90.081 0.270 ;
    END
  END r0_rd_out[56]
  PIN r0_rd_out[57]
    DIRECTION OUTPUT ;
    USE SIGNAL ;
    SHAPE ABUTMENT ;
    PORT
      LAYER M2 ;
      RECT 90.351 0.000 90.369 0.270 ;
    END
  END r0_rd_out[57]
  PIN r0_rd_out[58]
    DIRECTION OUTPUT ;
    USE SIGNAL ;
    SHAPE ABUTMENT ;
    PORT
      LAYER M2 ;
      RECT 90.639 0.000 90.657 0.270 ;
    END
  END r0_rd_out[58]
  PIN r0_rd_out[59]
    DIRECTION OUTPUT ;
    USE SIGNAL ;
    SHAPE ABUTMENT ;
    PORT
      LAYER M2 ;
      RECT 90.927 0.000 90.945 0.270 ;
    END
  END r0_rd_out[59]
  PIN r0_rd_out[60]
    DIRECTION OUTPUT ;
    USE SIGNAL ;
    SHAPE ABUTMENT ;
    PORT
      LAYER M2 ;
      RECT 91.215 0.000 91.233 0.270 ;
    END
  END r0_rd_out[60]
  PIN r0_rd_out[61]
    DIRECTION OUTPUT ;
    USE SIGNAL ;
    SHAPE ABUTMENT ;
    PORT
      LAYER M2 ;
      RECT 91.503 0.000 91.521 0.270 ;
    END
  END r0_rd_out[61]
  PIN r0_rd_out[62]
    DIRECTION OUTPUT ;
    USE SIGNAL ;
    SHAPE ABUTMENT ;
    PORT
      LAYER M2 ;
      RECT 91.791 0.000 91.809 0.270 ;
    END
  END r0_rd_out[62]
  PIN r0_rd_out[63]
    DIRECTION OUTPUT ;
    USE SIGNAL ;
    SHAPE ABUTMENT ;
    PORT
      LAYER M2 ;
      RECT 92.079 0.000 92.097 0.270 ;
    END
  END r0_rd_out[63]
  PIN r0_rd_out[64]
    DIRECTION OUTPUT ;
    USE SIGNAL ;
    SHAPE ABUTMENT ;
    PORT
      LAYER M2 ;
      RECT 92.367 0.000 92.385 0.270 ;
    END
  END r0_rd_out[64]
  PIN r0_rd_out[65]
    DIRECTION OUTPUT ;
    USE SIGNAL ;
    SHAPE ABUTMENT ;
    PORT
      LAYER M2 ;
      RECT 92.655 0.000 92.673 0.270 ;
    END
  END r0_rd_out[65]
  PIN r0_rd_out[66]
    DIRECTION OUTPUT ;
    USE SIGNAL ;
    SHAPE ABUTMENT ;
    PORT
      LAYER M2 ;
      RECT 92.943 0.000 92.961 0.270 ;
    END
  END r0_rd_out[66]
  PIN r0_rd_out[67]
    DIRECTION OUTPUT ;
    USE SIGNAL ;
    SHAPE ABUTMENT ;
    PORT
      LAYER M2 ;
      RECT 93.231 0.000 93.249 0.270 ;
    END
  END r0_rd_out[67]
  PIN r0_rd_out[68]
    DIRECTION OUTPUT ;
    USE SIGNAL ;
    SHAPE ABUTMENT ;
    PORT
      LAYER M2 ;
      RECT 93.519 0.000 93.537 0.270 ;
    END
  END r0_rd_out[68]
  PIN r0_rd_out[69]
    DIRECTION OUTPUT ;
    USE SIGNAL ;
    SHAPE ABUTMENT ;
    PORT
      LAYER M2 ;
      RECT 93.807 0.000 93.825 0.270 ;
    END
  END r0_rd_out[69]
  PIN r0_rd_out[70]
    DIRECTION OUTPUT ;
    USE SIGNAL ;
    SHAPE ABUTMENT ;
    PORT
      LAYER M2 ;
      RECT 94.095 0.000 94.113 0.270 ;
    END
  END r0_rd_out[70]
  PIN r0_rd_out[71]
    DIRECTION OUTPUT ;
    USE SIGNAL ;
    SHAPE ABUTMENT ;
    PORT
      LAYER M2 ;
      RECT 94.383 0.000 94.401 0.270 ;
    END
  END r0_rd_out[71]
  PIN r0_rd_out[72]
    DIRECTION OUTPUT ;
    USE SIGNAL ;
    SHAPE ABUTMENT ;
    PORT
      LAYER M2 ;
      RECT 94.671 0.000 94.689 0.270 ;
    END
  END r0_rd_out[72]
  PIN r0_rd_out[73]
    DIRECTION OUTPUT ;
    USE SIGNAL ;
    SHAPE ABUTMENT ;
    PORT
      LAYER M2 ;
      RECT 94.959 0.000 94.977 0.270 ;
    END
  END r0_rd_out[73]
  PIN r0_rd_out[74]
    DIRECTION OUTPUT ;
    USE SIGNAL ;
    SHAPE ABUTMENT ;
    PORT
      LAYER M2 ;
      RECT 95.247 0.000 95.265 0.270 ;
    END
  END r0_rd_out[74]
  PIN r0_rd_out[75]
    DIRECTION OUTPUT ;
    USE SIGNAL ;
    SHAPE ABUTMENT ;
    PORT
      LAYER M2 ;
      RECT 95.535 0.000 95.553 0.270 ;
    END
  END r0_rd_out[75]
  PIN r0_rd_out[76]
    DIRECTION OUTPUT ;
    USE SIGNAL ;
    SHAPE ABUTMENT ;
    PORT
      LAYER M2 ;
      RECT 95.823 0.000 95.841 0.270 ;
    END
  END r0_rd_out[76]
  PIN r0_rd_out[77]
    DIRECTION OUTPUT ;
    USE SIGNAL ;
    SHAPE ABUTMENT ;
    PORT
      LAYER M2 ;
      RECT 96.111 0.000 96.129 0.270 ;
    END
  END r0_rd_out[77]
  PIN r0_rd_out[78]
    DIRECTION OUTPUT ;
    USE SIGNAL ;
    SHAPE ABUTMENT ;
    PORT
      LAYER M2 ;
      RECT 96.399 0.000 96.417 0.270 ;
    END
  END r0_rd_out[78]
  PIN r0_rd_out[79]
    DIRECTION OUTPUT ;
    USE SIGNAL ;
    SHAPE ABUTMENT ;
    PORT
      LAYER M2 ;
      RECT 96.687 0.000 96.705 0.270 ;
    END
  END r0_rd_out[79]
  PIN r0_rd_out[80]
    DIRECTION OUTPUT ;
    USE SIGNAL ;
    SHAPE ABUTMENT ;
    PORT
      LAYER M2 ;
      RECT 96.975 0.000 96.993 0.270 ;
    END
  END r0_rd_out[80]
  PIN r0_rd_out[81]
    DIRECTION OUTPUT ;
    USE SIGNAL ;
    SHAPE ABUTMENT ;
    PORT
      LAYER M2 ;
      RECT 97.263 0.000 97.281 0.270 ;
    END
  END r0_rd_out[81]
  PIN r0_rd_out[82]
    DIRECTION OUTPUT ;
    USE SIGNAL ;
    SHAPE ABUTMENT ;
    PORT
      LAYER M2 ;
      RECT 97.551 0.000 97.569 0.270 ;
    END
  END r0_rd_out[82]
  PIN r0_rd_out[83]
    DIRECTION OUTPUT ;
    USE SIGNAL ;
    SHAPE ABUTMENT ;
    PORT
      LAYER M2 ;
      RECT 97.839 0.000 97.857 0.270 ;
    END
  END r0_rd_out[83]
  PIN r0_rd_out[84]
    DIRECTION OUTPUT ;
    USE SIGNAL ;
    SHAPE ABUTMENT ;
    PORT
      LAYER M2 ;
      RECT 98.127 0.000 98.145 0.270 ;
    END
  END r0_rd_out[84]
  PIN r0_rd_out[85]
    DIRECTION OUTPUT ;
    USE SIGNAL ;
    SHAPE ABUTMENT ;
    PORT
      LAYER M2 ;
      RECT 98.415 0.000 98.433 0.270 ;
    END
  END r0_rd_out[85]
  PIN r0_rd_out[86]
    DIRECTION OUTPUT ;
    USE SIGNAL ;
    SHAPE ABUTMENT ;
    PORT
      LAYER M2 ;
      RECT 98.703 0.000 98.721 0.270 ;
    END
  END r0_rd_out[86]
  PIN r0_rd_out[87]
    DIRECTION OUTPUT ;
    USE SIGNAL ;
    SHAPE ABUTMENT ;
    PORT
      LAYER M2 ;
      RECT 98.991 0.000 99.009 0.270 ;
    END
  END r0_rd_out[87]
  PIN r0_rd_out[88]
    DIRECTION OUTPUT ;
    USE SIGNAL ;
    SHAPE ABUTMENT ;
    PORT
      LAYER M2 ;
      RECT 99.279 0.000 99.297 0.270 ;
    END
  END r0_rd_out[88]
  PIN r0_rd_out[89]
    DIRECTION OUTPUT ;
    USE SIGNAL ;
    SHAPE ABUTMENT ;
    PORT
      LAYER M2 ;
      RECT 99.567 0.000 99.585 0.270 ;
    END
  END r0_rd_out[89]
  PIN r0_rd_out[90]
    DIRECTION OUTPUT ;
    USE SIGNAL ;
    SHAPE ABUTMENT ;
    PORT
      LAYER M2 ;
      RECT 99.855 0.000 99.873 0.270 ;
    END
  END r0_rd_out[90]
  PIN r0_rd_out[91]
    DIRECTION OUTPUT ;
    USE SIGNAL ;
    SHAPE ABUTMENT ;
    PORT
      LAYER M2 ;
      RECT 100.143 0.000 100.161 0.270 ;
    END
  END r0_rd_out[91]
  PIN r0_rd_out[92]
    DIRECTION OUTPUT ;
    USE SIGNAL ;
    SHAPE ABUTMENT ;
    PORT
      LAYER M2 ;
      RECT 100.431 0.000 100.449 0.270 ;
    END
  END r0_rd_out[92]
  PIN r0_rd_out[93]
    DIRECTION OUTPUT ;
    USE SIGNAL ;
    SHAPE ABUTMENT ;
    PORT
      LAYER M2 ;
      RECT 100.719 0.000 100.737 0.270 ;
    END
  END r0_rd_out[93]
  PIN r0_rd_out[94]
    DIRECTION OUTPUT ;
    USE SIGNAL ;
    SHAPE ABUTMENT ;
    PORT
      LAYER M2 ;
      RECT 101.007 0.000 101.025 0.270 ;
    END
  END r0_rd_out[94]
  PIN r0_rd_out[95]
    DIRECTION OUTPUT ;
    USE SIGNAL ;
    SHAPE ABUTMENT ;
    PORT
      LAYER M2 ;
      RECT 101.295 0.000 101.313 0.270 ;
    END
  END r0_rd_out[95]
  PIN r0_rd_out[96]
    DIRECTION OUTPUT ;
    USE SIGNAL ;
    SHAPE ABUTMENT ;
    PORT
      LAYER M2 ;
      RECT 101.583 0.000 101.601 0.270 ;
    END
  END r0_rd_out[96]
  PIN r0_rd_out[97]
    DIRECTION OUTPUT ;
    USE SIGNAL ;
    SHAPE ABUTMENT ;
    PORT
      LAYER M2 ;
      RECT 101.871 0.000 101.889 0.270 ;
    END
  END r0_rd_out[97]
  PIN r0_rd_out[98]
    DIRECTION OUTPUT ;
    USE SIGNAL ;
    SHAPE ABUTMENT ;
    PORT
      LAYER M2 ;
      RECT 102.159 0.000 102.177 0.270 ;
    END
  END r0_rd_out[98]
  PIN r0_rd_out[99]
    DIRECTION OUTPUT ;
    USE SIGNAL ;
    SHAPE ABUTMENT ;
    PORT
      LAYER M2 ;
      RECT 102.447 0.000 102.465 0.270 ;
    END
  END r0_rd_out[99]
  PIN r0_rd_out[100]
    DIRECTION OUTPUT ;
    USE SIGNAL ;
    SHAPE ABUTMENT ;
    PORT
      LAYER M2 ;
      RECT 102.735 0.000 102.753 0.270 ;
    END
  END r0_rd_out[100]
  PIN r0_rd_out[101]
    DIRECTION OUTPUT ;
    USE SIGNAL ;
    SHAPE ABUTMENT ;
    PORT
      LAYER M2 ;
      RECT 103.023 0.000 103.041 0.270 ;
    END
  END r0_rd_out[101]
  PIN r0_rd_out[102]
    DIRECTION OUTPUT ;
    USE SIGNAL ;
    SHAPE ABUTMENT ;
    PORT
      LAYER M2 ;
      RECT 103.311 0.000 103.329 0.270 ;
    END
  END r0_rd_out[102]
  PIN r0_rd_out[103]
    DIRECTION OUTPUT ;
    USE SIGNAL ;
    SHAPE ABUTMENT ;
    PORT
      LAYER M2 ;
      RECT 103.599 0.000 103.617 0.270 ;
    END
  END r0_rd_out[103]
  PIN r0_rd_out[104]
    DIRECTION OUTPUT ;
    USE SIGNAL ;
    SHAPE ABUTMENT ;
    PORT
      LAYER M2 ;
      RECT 103.887 0.000 103.905 0.270 ;
    END
  END r0_rd_out[104]
  PIN r0_rd_out[105]
    DIRECTION OUTPUT ;
    USE SIGNAL ;
    SHAPE ABUTMENT ;
    PORT
      LAYER M2 ;
      RECT 104.175 0.000 104.193 0.270 ;
    END
  END r0_rd_out[105]
  PIN r0_rd_out[106]
    DIRECTION OUTPUT ;
    USE SIGNAL ;
    SHAPE ABUTMENT ;
    PORT
      LAYER M2 ;
      RECT 104.463 0.000 104.481 0.270 ;
    END
  END r0_rd_out[106]
  PIN r0_rd_out[107]
    DIRECTION OUTPUT ;
    USE SIGNAL ;
    SHAPE ABUTMENT ;
    PORT
      LAYER M2 ;
      RECT 104.751 0.000 104.769 0.270 ;
    END
  END r0_rd_out[107]
  PIN r0_rd_out[108]
    DIRECTION OUTPUT ;
    USE SIGNAL ;
    SHAPE ABUTMENT ;
    PORT
      LAYER M2 ;
      RECT 105.039 0.000 105.057 0.270 ;
    END
  END r0_rd_out[108]
  PIN r0_rd_out[109]
    DIRECTION OUTPUT ;
    USE SIGNAL ;
    SHAPE ABUTMENT ;
    PORT
      LAYER M2 ;
      RECT 105.327 0.000 105.345 0.270 ;
    END
  END r0_rd_out[109]
  PIN r0_rd_out[110]
    DIRECTION OUTPUT ;
    USE SIGNAL ;
    SHAPE ABUTMENT ;
    PORT
      LAYER M2 ;
      RECT 105.615 0.000 105.633 0.270 ;
    END
  END r0_rd_out[110]
  PIN r0_rd_out[111]
    DIRECTION OUTPUT ;
    USE SIGNAL ;
    SHAPE ABUTMENT ;
    PORT
      LAYER M2 ;
      RECT 105.903 0.000 105.921 0.270 ;
    END
  END r0_rd_out[111]
  PIN r0_rd_out[112]
    DIRECTION OUTPUT ;
    USE SIGNAL ;
    SHAPE ABUTMENT ;
    PORT
      LAYER M2 ;
      RECT 106.191 0.000 106.209 0.270 ;
    END
  END r0_rd_out[112]
  PIN r0_rd_out[113]
    DIRECTION OUTPUT ;
    USE SIGNAL ;
    SHAPE ABUTMENT ;
    PORT
      LAYER M2 ;
      RECT 106.479 0.000 106.497 0.270 ;
    END
  END r0_rd_out[113]
  PIN r0_rd_out[114]
    DIRECTION OUTPUT ;
    USE SIGNAL ;
    SHAPE ABUTMENT ;
    PORT
      LAYER M2 ;
      RECT 106.767 0.000 106.785 0.270 ;
    END
  END r0_rd_out[114]
  PIN r0_rd_out[115]
    DIRECTION OUTPUT ;
    USE SIGNAL ;
    SHAPE ABUTMENT ;
    PORT
      LAYER M2 ;
      RECT 107.055 0.000 107.073 0.270 ;
    END
  END r0_rd_out[115]
  PIN r0_rd_out[116]
    DIRECTION OUTPUT ;
    USE SIGNAL ;
    SHAPE ABUTMENT ;
    PORT
      LAYER M2 ;
      RECT 107.343 0.000 107.361 0.270 ;
    END
  END r0_rd_out[116]
  PIN r0_rd_out[117]
    DIRECTION OUTPUT ;
    USE SIGNAL ;
    SHAPE ABUTMENT ;
    PORT
      LAYER M2 ;
      RECT 107.631 0.000 107.649 0.270 ;
    END
  END r0_rd_out[117]
  PIN r0_rd_out[118]
    DIRECTION OUTPUT ;
    USE SIGNAL ;
    SHAPE ABUTMENT ;
    PORT
      LAYER M2 ;
      RECT 107.919 0.000 107.937 0.270 ;
    END
  END r0_rd_out[118]
  PIN r0_rd_out[119]
    DIRECTION OUTPUT ;
    USE SIGNAL ;
    SHAPE ABUTMENT ;
    PORT
      LAYER M2 ;
      RECT 108.207 0.000 108.225 0.270 ;
    END
  END r0_rd_out[119]
  PIN r0_rd_out[120]
    DIRECTION OUTPUT ;
    USE SIGNAL ;
    SHAPE ABUTMENT ;
    PORT
      LAYER M2 ;
      RECT 108.495 0.000 108.513 0.270 ;
    END
  END r0_rd_out[120]
  PIN r0_rd_out[121]
    DIRECTION OUTPUT ;
    USE SIGNAL ;
    SHAPE ABUTMENT ;
    PORT
      LAYER M2 ;
      RECT 108.783 0.000 108.801 0.270 ;
    END
  END r0_rd_out[121]
  PIN r0_rd_out[122]
    DIRECTION OUTPUT ;
    USE SIGNAL ;
    SHAPE ABUTMENT ;
    PORT
      LAYER M2 ;
      RECT 109.071 0.000 109.089 0.270 ;
    END
  END r0_rd_out[122]
  PIN r0_rd_out[123]
    DIRECTION OUTPUT ;
    USE SIGNAL ;
    SHAPE ABUTMENT ;
    PORT
      LAYER M2 ;
      RECT 109.359 0.000 109.377 0.270 ;
    END
  END r0_rd_out[123]
  PIN r0_rd_out[124]
    DIRECTION OUTPUT ;
    USE SIGNAL ;
    SHAPE ABUTMENT ;
    PORT
      LAYER M2 ;
      RECT 109.647 0.000 109.665 0.270 ;
    END
  END r0_rd_out[124]
  PIN r0_rd_out[125]
    DIRECTION OUTPUT ;
    USE SIGNAL ;
    SHAPE ABUTMENT ;
    PORT
      LAYER M2 ;
      RECT 109.935 0.000 109.953 0.270 ;
    END
  END r0_rd_out[125]
  PIN r0_rd_out[126]
    DIRECTION OUTPUT ;
    USE SIGNAL ;
    SHAPE ABUTMENT ;
    PORT
      LAYER M2 ;
      RECT 110.223 0.000 110.241 0.270 ;
    END
  END r0_rd_out[126]
  PIN r0_rd_out[127]
    DIRECTION OUTPUT ;
    USE SIGNAL ;
    SHAPE ABUTMENT ;
    PORT
      LAYER M2 ;
      RECT 110.511 0.000 110.529 0.270 ;
    END
  END r0_rd_out[127]
  PIN r0_rd_out[128]
    DIRECTION OUTPUT ;
    USE SIGNAL ;
    SHAPE ABUTMENT ;
    PORT
      LAYER M2 ;
      RECT 110.799 0.000 110.817 0.270 ;
    END
  END r0_rd_out[128]
  PIN r0_rd_out[129]
    DIRECTION OUTPUT ;
    USE SIGNAL ;
    SHAPE ABUTMENT ;
    PORT
      LAYER M2 ;
      RECT 111.087 0.000 111.105 0.270 ;
    END
  END r0_rd_out[129]
  PIN r0_rd_out[130]
    DIRECTION OUTPUT ;
    USE SIGNAL ;
    SHAPE ABUTMENT ;
    PORT
      LAYER M2 ;
      RECT 111.375 0.000 111.393 0.270 ;
    END
  END r0_rd_out[130]
  PIN r0_rd_out[131]
    DIRECTION OUTPUT ;
    USE SIGNAL ;
    SHAPE ABUTMENT ;
    PORT
      LAYER M2 ;
      RECT 111.663 0.000 111.681 0.270 ;
    END
  END r0_rd_out[131]
  PIN r0_rd_out[132]
    DIRECTION OUTPUT ;
    USE SIGNAL ;
    SHAPE ABUTMENT ;
    PORT
      LAYER M2 ;
      RECT 111.951 0.000 111.969 0.270 ;
    END
  END r0_rd_out[132]
  PIN r0_rd_out[133]
    DIRECTION OUTPUT ;
    USE SIGNAL ;
    SHAPE ABUTMENT ;
    PORT
      LAYER M2 ;
      RECT 112.239 0.000 112.257 0.270 ;
    END
  END r0_rd_out[133]
  PIN r0_rd_out[134]
    DIRECTION OUTPUT ;
    USE SIGNAL ;
    SHAPE ABUTMENT ;
    PORT
      LAYER M2 ;
      RECT 112.527 0.000 112.545 0.270 ;
    END
  END r0_rd_out[134]
  PIN r0_rd_out[135]
    DIRECTION OUTPUT ;
    USE SIGNAL ;
    SHAPE ABUTMENT ;
    PORT
      LAYER M2 ;
      RECT 112.815 0.000 112.833 0.270 ;
    END
  END r0_rd_out[135]
  PIN r0_rd_out[136]
    DIRECTION OUTPUT ;
    USE SIGNAL ;
    SHAPE ABUTMENT ;
    PORT
      LAYER M2 ;
      RECT 113.103 0.000 113.121 0.270 ;
    END
  END r0_rd_out[136]
  PIN r0_rd_out[137]
    DIRECTION OUTPUT ;
    USE SIGNAL ;
    SHAPE ABUTMENT ;
    PORT
      LAYER M2 ;
      RECT 113.391 0.000 113.409 0.270 ;
    END
  END r0_rd_out[137]
  PIN r0_rd_out[138]
    DIRECTION OUTPUT ;
    USE SIGNAL ;
    SHAPE ABUTMENT ;
    PORT
      LAYER M2 ;
      RECT 113.679 0.000 113.697 0.270 ;
    END
  END r0_rd_out[138]
  PIN r0_rd_out[139]
    DIRECTION OUTPUT ;
    USE SIGNAL ;
    SHAPE ABUTMENT ;
    PORT
      LAYER M2 ;
      RECT 113.967 0.000 113.985 0.270 ;
    END
  END r0_rd_out[139]
  PIN r0_rd_out[140]
    DIRECTION OUTPUT ;
    USE SIGNAL ;
    SHAPE ABUTMENT ;
    PORT
      LAYER M2 ;
      RECT 114.255 0.000 114.273 0.270 ;
    END
  END r0_rd_out[140]
  PIN r0_rd_out[141]
    DIRECTION OUTPUT ;
    USE SIGNAL ;
    SHAPE ABUTMENT ;
    PORT
      LAYER M2 ;
      RECT 114.543 0.000 114.561 0.270 ;
    END
  END r0_rd_out[141]
  PIN r0_rd_out[142]
    DIRECTION OUTPUT ;
    USE SIGNAL ;
    SHAPE ABUTMENT ;
    PORT
      LAYER M2 ;
      RECT 114.831 0.000 114.849 0.270 ;
    END
  END r0_rd_out[142]
  PIN r0_rd_out[143]
    DIRECTION OUTPUT ;
    USE SIGNAL ;
    SHAPE ABUTMENT ;
    PORT
      LAYER M2 ;
      RECT 115.119 0.000 115.137 0.270 ;
    END
  END r0_rd_out[143]
  PIN r0_rd_out[144]
    DIRECTION OUTPUT ;
    USE SIGNAL ;
    SHAPE ABUTMENT ;
    PORT
      LAYER M2 ;
      RECT 115.407 0.000 115.425 0.270 ;
    END
  END r0_rd_out[144]
  PIN r0_rd_out[145]
    DIRECTION OUTPUT ;
    USE SIGNAL ;
    SHAPE ABUTMENT ;
    PORT
      LAYER M2 ;
      RECT 115.695 0.000 115.713 0.270 ;
    END
  END r0_rd_out[145]
  PIN r0_rd_out[146]
    DIRECTION OUTPUT ;
    USE SIGNAL ;
    SHAPE ABUTMENT ;
    PORT
      LAYER M2 ;
      RECT 115.983 0.000 116.001 0.270 ;
    END
  END r0_rd_out[146]
  PIN r0_rd_out[147]
    DIRECTION OUTPUT ;
    USE SIGNAL ;
    SHAPE ABUTMENT ;
    PORT
      LAYER M2 ;
      RECT 116.271 0.000 116.289 0.270 ;
    END
  END r0_rd_out[147]
  PIN r0_rd_out[148]
    DIRECTION OUTPUT ;
    USE SIGNAL ;
    SHAPE ABUTMENT ;
    PORT
      LAYER M2 ;
      RECT 116.559 0.000 116.577 0.270 ;
    END
  END r0_rd_out[148]
  PIN r0_rd_out[149]
    DIRECTION OUTPUT ;
    USE SIGNAL ;
    SHAPE ABUTMENT ;
    PORT
      LAYER M2 ;
      RECT 116.847 0.000 116.865 0.270 ;
    END
  END r0_rd_out[149]
  PIN r0_rd_out[150]
    DIRECTION OUTPUT ;
    USE SIGNAL ;
    SHAPE ABUTMENT ;
    PORT
      LAYER M2 ;
      RECT 117.135 0.000 117.153 0.270 ;
    END
  END r0_rd_out[150]
  PIN r0_rd_out[151]
    DIRECTION OUTPUT ;
    USE SIGNAL ;
    SHAPE ABUTMENT ;
    PORT
      LAYER M2 ;
      RECT 117.423 0.000 117.441 0.270 ;
    END
  END r0_rd_out[151]
  PIN r0_rd_out[152]
    DIRECTION OUTPUT ;
    USE SIGNAL ;
    SHAPE ABUTMENT ;
    PORT
      LAYER M2 ;
      RECT 117.711 0.000 117.729 0.270 ;
    END
  END r0_rd_out[152]
  PIN r0_rd_out[153]
    DIRECTION OUTPUT ;
    USE SIGNAL ;
    SHAPE ABUTMENT ;
    PORT
      LAYER M2 ;
      RECT 117.999 0.000 118.017 0.270 ;
    END
  END r0_rd_out[153]
  PIN r0_rd_out[154]
    DIRECTION OUTPUT ;
    USE SIGNAL ;
    SHAPE ABUTMENT ;
    PORT
      LAYER M2 ;
      RECT 118.287 0.000 118.305 0.270 ;
    END
  END r0_rd_out[154]
  PIN r0_rd_out[155]
    DIRECTION OUTPUT ;
    USE SIGNAL ;
    SHAPE ABUTMENT ;
    PORT
      LAYER M2 ;
      RECT 118.575 0.000 118.593 0.270 ;
    END
  END r0_rd_out[155]
  PIN r0_rd_out[156]
    DIRECTION OUTPUT ;
    USE SIGNAL ;
    SHAPE ABUTMENT ;
    PORT
      LAYER M2 ;
      RECT 118.863 0.000 118.881 0.270 ;
    END
  END r0_rd_out[156]
  PIN r0_rd_out[157]
    DIRECTION OUTPUT ;
    USE SIGNAL ;
    SHAPE ABUTMENT ;
    PORT
      LAYER M2 ;
      RECT 119.151 0.000 119.169 0.270 ;
    END
  END r0_rd_out[157]
  PIN r0_rd_out[158]
    DIRECTION OUTPUT ;
    USE SIGNAL ;
    SHAPE ABUTMENT ;
    PORT
      LAYER M2 ;
      RECT 119.439 0.000 119.457 0.270 ;
    END
  END r0_rd_out[158]
  PIN r0_rd_out[159]
    DIRECTION OUTPUT ;
    USE SIGNAL ;
    SHAPE ABUTMENT ;
    PORT
      LAYER M2 ;
      RECT 119.727 0.000 119.745 0.270 ;
    END
  END r0_rd_out[159]
  PIN r0_rd_out[160]
    DIRECTION OUTPUT ;
    USE SIGNAL ;
    SHAPE ABUTMENT ;
    PORT
      LAYER M2 ;
      RECT 120.015 0.000 120.033 0.270 ;
    END
  END r0_rd_out[160]
  PIN r0_rd_out[161]
    DIRECTION OUTPUT ;
    USE SIGNAL ;
    SHAPE ABUTMENT ;
    PORT
      LAYER M2 ;
      RECT 120.303 0.000 120.321 0.270 ;
    END
  END r0_rd_out[161]
  PIN r0_rd_out[162]
    DIRECTION OUTPUT ;
    USE SIGNAL ;
    SHAPE ABUTMENT ;
    PORT
      LAYER M2 ;
      RECT 120.591 0.000 120.609 0.270 ;
    END
  END r0_rd_out[162]
  PIN r0_rd_out[163]
    DIRECTION OUTPUT ;
    USE SIGNAL ;
    SHAPE ABUTMENT ;
    PORT
      LAYER M2 ;
      RECT 120.879 0.000 120.897 0.270 ;
    END
  END r0_rd_out[163]
  PIN r0_rd_out[164]
    DIRECTION OUTPUT ;
    USE SIGNAL ;
    SHAPE ABUTMENT ;
    PORT
      LAYER M2 ;
      RECT 121.167 0.000 121.185 0.270 ;
    END
  END r0_rd_out[164]
  PIN r0_rd_out[165]
    DIRECTION OUTPUT ;
    USE SIGNAL ;
    SHAPE ABUTMENT ;
    PORT
      LAYER M2 ;
      RECT 121.455 0.000 121.473 0.270 ;
    END
  END r0_rd_out[165]
  PIN r0_rd_out[166]
    DIRECTION OUTPUT ;
    USE SIGNAL ;
    SHAPE ABUTMENT ;
    PORT
      LAYER M2 ;
      RECT 121.743 0.000 121.761 0.270 ;
    END
  END r0_rd_out[166]
  PIN r0_rd_out[167]
    DIRECTION OUTPUT ;
    USE SIGNAL ;
    SHAPE ABUTMENT ;
    PORT
      LAYER M2 ;
      RECT 122.031 0.000 122.049 0.270 ;
    END
  END r0_rd_out[167]
  PIN r0_rd_out[168]
    DIRECTION OUTPUT ;
    USE SIGNAL ;
    SHAPE ABUTMENT ;
    PORT
      LAYER M2 ;
      RECT 122.319 0.000 122.337 0.270 ;
    END
  END r0_rd_out[168]
  PIN r0_rd_out[169]
    DIRECTION OUTPUT ;
    USE SIGNAL ;
    SHAPE ABUTMENT ;
    PORT
      LAYER M2 ;
      RECT 122.607 0.000 122.625 0.270 ;
    END
  END r0_rd_out[169]
  PIN r0_rd_out[170]
    DIRECTION OUTPUT ;
    USE SIGNAL ;
    SHAPE ABUTMENT ;
    PORT
      LAYER M2 ;
      RECT 122.895 0.000 122.913 0.270 ;
    END
  END r0_rd_out[170]
  PIN r0_rd_out[171]
    DIRECTION OUTPUT ;
    USE SIGNAL ;
    SHAPE ABUTMENT ;
    PORT
      LAYER M2 ;
      RECT 123.183 0.000 123.201 0.270 ;
    END
  END r0_rd_out[171]
  PIN r0_rd_out[172]
    DIRECTION OUTPUT ;
    USE SIGNAL ;
    SHAPE ABUTMENT ;
    PORT
      LAYER M2 ;
      RECT 123.471 0.000 123.489 0.270 ;
    END
  END r0_rd_out[172]
  PIN r0_rd_out[173]
    DIRECTION OUTPUT ;
    USE SIGNAL ;
    SHAPE ABUTMENT ;
    PORT
      LAYER M2 ;
      RECT 123.759 0.000 123.777 0.270 ;
    END
  END r0_rd_out[173]
  PIN r0_rd_out[174]
    DIRECTION OUTPUT ;
    USE SIGNAL ;
    SHAPE ABUTMENT ;
    PORT
      LAYER M2 ;
      RECT 124.047 0.000 124.065 0.270 ;
    END
  END r0_rd_out[174]
  PIN r0_rd_out[175]
    DIRECTION OUTPUT ;
    USE SIGNAL ;
    SHAPE ABUTMENT ;
    PORT
      LAYER M2 ;
      RECT 124.335 0.000 124.353 0.270 ;
    END
  END r0_rd_out[175]
  PIN r0_rd_out[176]
    DIRECTION OUTPUT ;
    USE SIGNAL ;
    SHAPE ABUTMENT ;
    PORT
      LAYER M2 ;
      RECT 124.623 0.000 124.641 0.270 ;
    END
  END r0_rd_out[176]
  PIN r0_rd_out[177]
    DIRECTION OUTPUT ;
    USE SIGNAL ;
    SHAPE ABUTMENT ;
    PORT
      LAYER M2 ;
      RECT 124.911 0.000 124.929 0.270 ;
    END
  END r0_rd_out[177]
  PIN r0_rd_out[178]
    DIRECTION OUTPUT ;
    USE SIGNAL ;
    SHAPE ABUTMENT ;
    PORT
      LAYER M2 ;
      RECT 125.199 0.000 125.217 0.270 ;
    END
  END r0_rd_out[178]
  PIN r0_rd_out[179]
    DIRECTION OUTPUT ;
    USE SIGNAL ;
    SHAPE ABUTMENT ;
    PORT
      LAYER M2 ;
      RECT 125.487 0.000 125.505 0.270 ;
    END
  END r0_rd_out[179]
  PIN r0_rd_out[180]
    DIRECTION OUTPUT ;
    USE SIGNAL ;
    SHAPE ABUTMENT ;
    PORT
      LAYER M2 ;
      RECT 125.775 0.000 125.793 0.270 ;
    END
  END r0_rd_out[180]
  PIN r0_rd_out[181]
    DIRECTION OUTPUT ;
    USE SIGNAL ;
    SHAPE ABUTMENT ;
    PORT
      LAYER M2 ;
      RECT 126.063 0.000 126.081 0.270 ;
    END
  END r0_rd_out[181]
  PIN r0_rd_out[182]
    DIRECTION OUTPUT ;
    USE SIGNAL ;
    SHAPE ABUTMENT ;
    PORT
      LAYER M2 ;
      RECT 126.351 0.000 126.369 0.270 ;
    END
  END r0_rd_out[182]
  PIN r0_rd_out[183]
    DIRECTION OUTPUT ;
    USE SIGNAL ;
    SHAPE ABUTMENT ;
    PORT
      LAYER M2 ;
      RECT 126.639 0.000 126.657 0.270 ;
    END
  END r0_rd_out[183]
  PIN r0_rd_out[184]
    DIRECTION OUTPUT ;
    USE SIGNAL ;
    SHAPE ABUTMENT ;
    PORT
      LAYER M2 ;
      RECT 126.927 0.000 126.945 0.270 ;
    END
  END r0_rd_out[184]
  PIN r0_rd_out[185]
    DIRECTION OUTPUT ;
    USE SIGNAL ;
    SHAPE ABUTMENT ;
    PORT
      LAYER M2 ;
      RECT 127.215 0.000 127.233 0.270 ;
    END
  END r0_rd_out[185]
  PIN r0_rd_out[186]
    DIRECTION OUTPUT ;
    USE SIGNAL ;
    SHAPE ABUTMENT ;
    PORT
      LAYER M2 ;
      RECT 127.503 0.000 127.521 0.270 ;
    END
  END r0_rd_out[186]
  PIN r0_rd_out[187]
    DIRECTION OUTPUT ;
    USE SIGNAL ;
    SHAPE ABUTMENT ;
    PORT
      LAYER M2 ;
      RECT 127.791 0.000 127.809 0.270 ;
    END
  END r0_rd_out[187]
  PIN r0_rd_out[188]
    DIRECTION OUTPUT ;
    USE SIGNAL ;
    SHAPE ABUTMENT ;
    PORT
      LAYER M2 ;
      RECT 128.079 0.000 128.097 0.270 ;
    END
  END r0_rd_out[188]
  PIN r0_rd_out[189]
    DIRECTION OUTPUT ;
    USE SIGNAL ;
    SHAPE ABUTMENT ;
    PORT
      LAYER M2 ;
      RECT 128.367 0.000 128.385 0.270 ;
    END
  END r0_rd_out[189]
  PIN r0_rd_out[190]
    DIRECTION OUTPUT ;
    USE SIGNAL ;
    SHAPE ABUTMENT ;
    PORT
      LAYER M2 ;
      RECT 128.655 0.000 128.673 0.270 ;
    END
  END r0_rd_out[190]
  PIN r0_rd_out[191]
    DIRECTION OUTPUT ;
    USE SIGNAL ;
    SHAPE ABUTMENT ;
    PORT
      LAYER M2 ;
      RECT 128.943 0.000 128.961 0.270 ;
    END
  END r0_rd_out[191]
  PIN r0_rd_out[192]
    DIRECTION OUTPUT ;
    USE SIGNAL ;
    SHAPE ABUTMENT ;
    PORT
      LAYER M2 ;
      RECT 129.231 0.000 129.249 0.270 ;
    END
  END r0_rd_out[192]
  PIN r0_rd_out[193]
    DIRECTION OUTPUT ;
    USE SIGNAL ;
    SHAPE ABUTMENT ;
    PORT
      LAYER M2 ;
      RECT 129.519 0.000 129.537 0.270 ;
    END
  END r0_rd_out[193]
  PIN r0_rd_out[194]
    DIRECTION OUTPUT ;
    USE SIGNAL ;
    SHAPE ABUTMENT ;
    PORT
      LAYER M2 ;
      RECT 129.807 0.000 129.825 0.270 ;
    END
  END r0_rd_out[194]
  PIN r0_rd_out[195]
    DIRECTION OUTPUT ;
    USE SIGNAL ;
    SHAPE ABUTMENT ;
    PORT
      LAYER M2 ;
      RECT 130.095 0.000 130.113 0.270 ;
    END
  END r0_rd_out[195]
  PIN r0_rd_out[196]
    DIRECTION OUTPUT ;
    USE SIGNAL ;
    SHAPE ABUTMENT ;
    PORT
      LAYER M2 ;
      RECT 130.383 0.000 130.401 0.270 ;
    END
  END r0_rd_out[196]
  PIN r0_rd_out[197]
    DIRECTION OUTPUT ;
    USE SIGNAL ;
    SHAPE ABUTMENT ;
    PORT
      LAYER M2 ;
      RECT 130.671 0.000 130.689 0.270 ;
    END
  END r0_rd_out[197]
  PIN r0_rd_out[198]
    DIRECTION OUTPUT ;
    USE SIGNAL ;
    SHAPE ABUTMENT ;
    PORT
      LAYER M2 ;
      RECT 130.959 0.000 130.977 0.270 ;
    END
  END r0_rd_out[198]
  PIN r0_rd_out[199]
    DIRECTION OUTPUT ;
    USE SIGNAL ;
    SHAPE ABUTMENT ;
    PORT
      LAYER M2 ;
      RECT 131.247 0.000 131.265 0.270 ;
    END
  END r0_rd_out[199]
  PIN r0_rd_out[200]
    DIRECTION OUTPUT ;
    USE SIGNAL ;
    SHAPE ABUTMENT ;
    PORT
      LAYER M2 ;
      RECT 131.535 0.000 131.553 0.270 ;
    END
  END r0_rd_out[200]
  PIN r0_rd_out[201]
    DIRECTION OUTPUT ;
    USE SIGNAL ;
    SHAPE ABUTMENT ;
    PORT
      LAYER M2 ;
      RECT 131.823 0.000 131.841 0.270 ;
    END
  END r0_rd_out[201]
  PIN r0_rd_out[202]
    DIRECTION OUTPUT ;
    USE SIGNAL ;
    SHAPE ABUTMENT ;
    PORT
      LAYER M2 ;
      RECT 132.111 0.000 132.129 0.270 ;
    END
  END r0_rd_out[202]
  PIN r0_rd_out[203]
    DIRECTION OUTPUT ;
    USE SIGNAL ;
    SHAPE ABUTMENT ;
    PORT
      LAYER M2 ;
      RECT 132.399 0.000 132.417 0.270 ;
    END
  END r0_rd_out[203]
  PIN r0_rd_out[204]
    DIRECTION OUTPUT ;
    USE SIGNAL ;
    SHAPE ABUTMENT ;
    PORT
      LAYER M2 ;
      RECT 132.687 0.000 132.705 0.270 ;
    END
  END r0_rd_out[204]
  PIN r0_rd_out[205]
    DIRECTION OUTPUT ;
    USE SIGNAL ;
    SHAPE ABUTMENT ;
    PORT
      LAYER M2 ;
      RECT 132.975 0.000 132.993 0.270 ;
    END
  END r0_rd_out[205]
  PIN r0_rd_out[206]
    DIRECTION OUTPUT ;
    USE SIGNAL ;
    SHAPE ABUTMENT ;
    PORT
      LAYER M2 ;
      RECT 133.263 0.000 133.281 0.270 ;
    END
  END r0_rd_out[206]
  PIN r0_rd_out[207]
    DIRECTION OUTPUT ;
    USE SIGNAL ;
    SHAPE ABUTMENT ;
    PORT
      LAYER M2 ;
      RECT 133.551 0.000 133.569 0.270 ;
    END
  END r0_rd_out[207]
  PIN r0_rd_out[208]
    DIRECTION OUTPUT ;
    USE SIGNAL ;
    SHAPE ABUTMENT ;
    PORT
      LAYER M2 ;
      RECT 133.839 0.000 133.857 0.270 ;
    END
  END r0_rd_out[208]
  PIN r0_rd_out[209]
    DIRECTION OUTPUT ;
    USE SIGNAL ;
    SHAPE ABUTMENT ;
    PORT
      LAYER M2 ;
      RECT 134.127 0.000 134.145 0.270 ;
    END
  END r0_rd_out[209]
  PIN r0_rd_out[210]
    DIRECTION OUTPUT ;
    USE SIGNAL ;
    SHAPE ABUTMENT ;
    PORT
      LAYER M2 ;
      RECT 134.415 0.000 134.433 0.270 ;
    END
  END r0_rd_out[210]
  PIN r0_rd_out[211]
    DIRECTION OUTPUT ;
    USE SIGNAL ;
    SHAPE ABUTMENT ;
    PORT
      LAYER M2 ;
      RECT 134.703 0.000 134.721 0.270 ;
    END
  END r0_rd_out[211]
  PIN r0_rd_out[212]
    DIRECTION OUTPUT ;
    USE SIGNAL ;
    SHAPE ABUTMENT ;
    PORT
      LAYER M2 ;
      RECT 134.991 0.000 135.009 0.270 ;
    END
  END r0_rd_out[212]
  PIN r0_rd_out[213]
    DIRECTION OUTPUT ;
    USE SIGNAL ;
    SHAPE ABUTMENT ;
    PORT
      LAYER M2 ;
      RECT 135.279 0.000 135.297 0.270 ;
    END
  END r0_rd_out[213]
  PIN r0_rd_out[214]
    DIRECTION OUTPUT ;
    USE SIGNAL ;
    SHAPE ABUTMENT ;
    PORT
      LAYER M2 ;
      RECT 135.567 0.000 135.585 0.270 ;
    END
  END r0_rd_out[214]
  PIN r0_rd_out[215]
    DIRECTION OUTPUT ;
    USE SIGNAL ;
    SHAPE ABUTMENT ;
    PORT
      LAYER M2 ;
      RECT 135.855 0.000 135.873 0.270 ;
    END
  END r0_rd_out[215]
  PIN r0_rd_out[216]
    DIRECTION OUTPUT ;
    USE SIGNAL ;
    SHAPE ABUTMENT ;
    PORT
      LAYER M2 ;
      RECT 136.143 0.000 136.161 0.270 ;
    END
  END r0_rd_out[216]
  PIN r0_rd_out[217]
    DIRECTION OUTPUT ;
    USE SIGNAL ;
    SHAPE ABUTMENT ;
    PORT
      LAYER M2 ;
      RECT 136.431 0.000 136.449 0.270 ;
    END
  END r0_rd_out[217]
  PIN r0_rd_out[218]
    DIRECTION OUTPUT ;
    USE SIGNAL ;
    SHAPE ABUTMENT ;
    PORT
      LAYER M2 ;
      RECT 136.719 0.000 136.737 0.270 ;
    END
  END r0_rd_out[218]
  PIN r0_rd_out[219]
    DIRECTION OUTPUT ;
    USE SIGNAL ;
    SHAPE ABUTMENT ;
    PORT
      LAYER M2 ;
      RECT 137.007 0.000 137.025 0.270 ;
    END
  END r0_rd_out[219]
  PIN r0_rd_out[220]
    DIRECTION OUTPUT ;
    USE SIGNAL ;
    SHAPE ABUTMENT ;
    PORT
      LAYER M2 ;
      RECT 137.295 0.000 137.313 0.270 ;
    END
  END r0_rd_out[220]
  PIN r0_rd_out[221]
    DIRECTION OUTPUT ;
    USE SIGNAL ;
    SHAPE ABUTMENT ;
    PORT
      LAYER M2 ;
      RECT 137.583 0.000 137.601 0.270 ;
    END
  END r0_rd_out[221]
  PIN r0_rd_out[222]
    DIRECTION OUTPUT ;
    USE SIGNAL ;
    SHAPE ABUTMENT ;
    PORT
      LAYER M2 ;
      RECT 137.871 0.000 137.889 0.270 ;
    END
  END r0_rd_out[222]
  PIN r0_rd_out[223]
    DIRECTION OUTPUT ;
    USE SIGNAL ;
    SHAPE ABUTMENT ;
    PORT
      LAYER M2 ;
      RECT 138.159 0.000 138.177 0.270 ;
    END
  END r0_rd_out[223]
  PIN r0_rd_out[224]
    DIRECTION OUTPUT ;
    USE SIGNAL ;
    SHAPE ABUTMENT ;
    PORT
      LAYER M2 ;
      RECT 138.447 0.000 138.465 0.270 ;
    END
  END r0_rd_out[224]
  PIN r0_rd_out[225]
    DIRECTION OUTPUT ;
    USE SIGNAL ;
    SHAPE ABUTMENT ;
    PORT
      LAYER M2 ;
      RECT 138.735 0.000 138.753 0.270 ;
    END
  END r0_rd_out[225]
  PIN r0_rd_out[226]
    DIRECTION OUTPUT ;
    USE SIGNAL ;
    SHAPE ABUTMENT ;
    PORT
      LAYER M2 ;
      RECT 139.023 0.000 139.041 0.270 ;
    END
  END r0_rd_out[226]
  PIN r0_rd_out[227]
    DIRECTION OUTPUT ;
    USE SIGNAL ;
    SHAPE ABUTMENT ;
    PORT
      LAYER M2 ;
      RECT 139.311 0.000 139.329 0.270 ;
    END
  END r0_rd_out[227]
  PIN r0_rd_out[228]
    DIRECTION OUTPUT ;
    USE SIGNAL ;
    SHAPE ABUTMENT ;
    PORT
      LAYER M2 ;
      RECT 139.599 0.000 139.617 0.270 ;
    END
  END r0_rd_out[228]
  PIN r0_rd_out[229]
    DIRECTION OUTPUT ;
    USE SIGNAL ;
    SHAPE ABUTMENT ;
    PORT
      LAYER M2 ;
      RECT 139.887 0.000 139.905 0.270 ;
    END
  END r0_rd_out[229]
  PIN r0_rd_out[230]
    DIRECTION OUTPUT ;
    USE SIGNAL ;
    SHAPE ABUTMENT ;
    PORT
      LAYER M2 ;
      RECT 140.175 0.000 140.193 0.270 ;
    END
  END r0_rd_out[230]
  PIN r0_rd_out[231]
    DIRECTION OUTPUT ;
    USE SIGNAL ;
    SHAPE ABUTMENT ;
    PORT
      LAYER M2 ;
      RECT 140.463 0.000 140.481 0.270 ;
    END
  END r0_rd_out[231]
  PIN r0_rd_out[232]
    DIRECTION OUTPUT ;
    USE SIGNAL ;
    SHAPE ABUTMENT ;
    PORT
      LAYER M2 ;
      RECT 140.751 0.000 140.769 0.270 ;
    END
  END r0_rd_out[232]
  PIN r0_rd_out[233]
    DIRECTION OUTPUT ;
    USE SIGNAL ;
    SHAPE ABUTMENT ;
    PORT
      LAYER M2 ;
      RECT 141.039 0.000 141.057 0.270 ;
    END
  END r0_rd_out[233]
  PIN r0_rd_out[234]
    DIRECTION OUTPUT ;
    USE SIGNAL ;
    SHAPE ABUTMENT ;
    PORT
      LAYER M2 ;
      RECT 141.327 0.000 141.345 0.270 ;
    END
  END r0_rd_out[234]
  PIN r0_rd_out[235]
    DIRECTION OUTPUT ;
    USE SIGNAL ;
    SHAPE ABUTMENT ;
    PORT
      LAYER M2 ;
      RECT 141.615 0.000 141.633 0.270 ;
    END
  END r0_rd_out[235]
  PIN r0_rd_out[236]
    DIRECTION OUTPUT ;
    USE SIGNAL ;
    SHAPE ABUTMENT ;
    PORT
      LAYER M2 ;
      RECT 141.903 0.000 141.921 0.270 ;
    END
  END r0_rd_out[236]
  PIN r0_rd_out[237]
    DIRECTION OUTPUT ;
    USE SIGNAL ;
    SHAPE ABUTMENT ;
    PORT
      LAYER M2 ;
      RECT 142.191 0.000 142.209 0.270 ;
    END
  END r0_rd_out[237]
  PIN r0_rd_out[238]
    DIRECTION OUTPUT ;
    USE SIGNAL ;
    SHAPE ABUTMENT ;
    PORT
      LAYER M2 ;
      RECT 142.479 0.000 142.497 0.270 ;
    END
  END r0_rd_out[238]
  PIN r0_rd_out[239]
    DIRECTION OUTPUT ;
    USE SIGNAL ;
    SHAPE ABUTMENT ;
    PORT
      LAYER M2 ;
      RECT 142.767 0.000 142.785 0.270 ;
    END
  END r0_rd_out[239]
  PIN r0_rd_out[240]
    DIRECTION OUTPUT ;
    USE SIGNAL ;
    SHAPE ABUTMENT ;
    PORT
      LAYER M2 ;
      RECT 143.055 0.000 143.073 0.270 ;
    END
  END r0_rd_out[240]
  PIN r0_rd_out[241]
    DIRECTION OUTPUT ;
    USE SIGNAL ;
    SHAPE ABUTMENT ;
    PORT
      LAYER M2 ;
      RECT 143.343 0.000 143.361 0.270 ;
    END
  END r0_rd_out[241]
  PIN r0_rd_out[242]
    DIRECTION OUTPUT ;
    USE SIGNAL ;
    SHAPE ABUTMENT ;
    PORT
      LAYER M2 ;
      RECT 143.631 0.000 143.649 0.270 ;
    END
  END r0_rd_out[242]
  PIN r0_rd_out[243]
    DIRECTION OUTPUT ;
    USE SIGNAL ;
    SHAPE ABUTMENT ;
    PORT
      LAYER M2 ;
      RECT 143.919 0.000 143.937 0.270 ;
    END
  END r0_rd_out[243]
  PIN r0_rd_out[244]
    DIRECTION OUTPUT ;
    USE SIGNAL ;
    SHAPE ABUTMENT ;
    PORT
      LAYER M2 ;
      RECT 144.207 0.000 144.225 0.270 ;
    END
  END r0_rd_out[244]
  PIN r0_rd_out[245]
    DIRECTION OUTPUT ;
    USE SIGNAL ;
    SHAPE ABUTMENT ;
    PORT
      LAYER M2 ;
      RECT 144.495 0.000 144.513 0.270 ;
    END
  END r0_rd_out[245]
  PIN r0_rd_out[246]
    DIRECTION OUTPUT ;
    USE SIGNAL ;
    SHAPE ABUTMENT ;
    PORT
      LAYER M2 ;
      RECT 144.783 0.000 144.801 0.270 ;
    END
  END r0_rd_out[246]
  PIN r0_rd_out[247]
    DIRECTION OUTPUT ;
    USE SIGNAL ;
    SHAPE ABUTMENT ;
    PORT
      LAYER M2 ;
      RECT 145.071 0.000 145.089 0.270 ;
    END
  END r0_rd_out[247]
  PIN r0_rd_out[248]
    DIRECTION OUTPUT ;
    USE SIGNAL ;
    SHAPE ABUTMENT ;
    PORT
      LAYER M2 ;
      RECT 145.359 0.000 145.377 0.270 ;
    END
  END r0_rd_out[248]
  PIN r0_rd_out[249]
    DIRECTION OUTPUT ;
    USE SIGNAL ;
    SHAPE ABUTMENT ;
    PORT
      LAYER M2 ;
      RECT 145.647 0.000 145.665 0.270 ;
    END
  END r0_rd_out[249]
  PIN r0_rd_out[250]
    DIRECTION OUTPUT ;
    USE SIGNAL ;
    SHAPE ABUTMENT ;
    PORT
      LAYER M2 ;
      RECT 145.935 0.000 145.953 0.270 ;
    END
  END r0_rd_out[250]
  PIN r0_rd_out[251]
    DIRECTION OUTPUT ;
    USE SIGNAL ;
    SHAPE ABUTMENT ;
    PORT
      LAYER M2 ;
      RECT 146.223 0.000 146.241 0.270 ;
    END
  END r0_rd_out[251]
  PIN r0_rd_out[252]
    DIRECTION OUTPUT ;
    USE SIGNAL ;
    SHAPE ABUTMENT ;
    PORT
      LAYER M2 ;
      RECT 146.511 0.000 146.529 0.270 ;
    END
  END r0_rd_out[252]
  PIN r0_rd_out[253]
    DIRECTION OUTPUT ;
    USE SIGNAL ;
    SHAPE ABUTMENT ;
    PORT
      LAYER M2 ;
      RECT 146.799 0.000 146.817 0.270 ;
    END
  END r0_rd_out[253]
  PIN r0_rd_out[254]
    DIRECTION OUTPUT ;
    USE SIGNAL ;
    SHAPE ABUTMENT ;
    PORT
      LAYER M2 ;
      RECT 147.087 0.000 147.105 0.270 ;
    END
  END r0_rd_out[254]
  PIN r0_rd_out[255]
    DIRECTION OUTPUT ;
    USE SIGNAL ;
    SHAPE ABUTMENT ;
    PORT
      LAYER M2 ;
      RECT 147.375 0.000 147.393 0.270 ;
    END
  END r0_rd_out[255]
  PIN r0_rd_out[256]
    DIRECTION OUTPUT ;
    USE SIGNAL ;
    SHAPE ABUTMENT ;
    PORT
      LAYER M2 ;
      RECT 0.207 385.560 0.225 385.830 ;
    END
  END r0_rd_out[256]
  PIN r0_rd_out[257]
    DIRECTION OUTPUT ;
    USE SIGNAL ;
    SHAPE ABUTMENT ;
    PORT
      LAYER M2 ;
      RECT 0.783 385.560 0.801 385.830 ;
    END
  END r0_rd_out[257]
  PIN r0_rd_out[258]
    DIRECTION OUTPUT ;
    USE SIGNAL ;
    SHAPE ABUTMENT ;
    PORT
      LAYER M2 ;
      RECT 1.359 385.560 1.377 385.830 ;
    END
  END r0_rd_out[258]
  PIN r0_rd_out[259]
    DIRECTION OUTPUT ;
    USE SIGNAL ;
    SHAPE ABUTMENT ;
    PORT
      LAYER M2 ;
      RECT 1.935 385.560 1.953 385.830 ;
    END
  END r0_rd_out[259]
  PIN r0_rd_out[260]
    DIRECTION OUTPUT ;
    USE SIGNAL ;
    SHAPE ABUTMENT ;
    PORT
      LAYER M2 ;
      RECT 2.511 385.560 2.529 385.830 ;
    END
  END r0_rd_out[260]
  PIN r0_rd_out[261]
    DIRECTION OUTPUT ;
    USE SIGNAL ;
    SHAPE ABUTMENT ;
    PORT
      LAYER M2 ;
      RECT 3.087 385.560 3.105 385.830 ;
    END
  END r0_rd_out[261]
  PIN r0_rd_out[262]
    DIRECTION OUTPUT ;
    USE SIGNAL ;
    SHAPE ABUTMENT ;
    PORT
      LAYER M2 ;
      RECT 3.663 385.560 3.681 385.830 ;
    END
  END r0_rd_out[262]
  PIN r0_rd_out[263]
    DIRECTION OUTPUT ;
    USE SIGNAL ;
    SHAPE ABUTMENT ;
    PORT
      LAYER M2 ;
      RECT 4.239 385.560 4.257 385.830 ;
    END
  END r0_rd_out[263]
  PIN r0_rd_out[264]
    DIRECTION OUTPUT ;
    USE SIGNAL ;
    SHAPE ABUTMENT ;
    PORT
      LAYER M2 ;
      RECT 4.815 385.560 4.833 385.830 ;
    END
  END r0_rd_out[264]
  PIN r0_rd_out[265]
    DIRECTION OUTPUT ;
    USE SIGNAL ;
    SHAPE ABUTMENT ;
    PORT
      LAYER M2 ;
      RECT 5.391 385.560 5.409 385.830 ;
    END
  END r0_rd_out[265]
  PIN r0_rd_out[266]
    DIRECTION OUTPUT ;
    USE SIGNAL ;
    SHAPE ABUTMENT ;
    PORT
      LAYER M2 ;
      RECT 5.967 385.560 5.985 385.830 ;
    END
  END r0_rd_out[266]
  PIN r0_rd_out[267]
    DIRECTION OUTPUT ;
    USE SIGNAL ;
    SHAPE ABUTMENT ;
    PORT
      LAYER M2 ;
      RECT 6.543 385.560 6.561 385.830 ;
    END
  END r0_rd_out[267]
  PIN r0_rd_out[268]
    DIRECTION OUTPUT ;
    USE SIGNAL ;
    SHAPE ABUTMENT ;
    PORT
      LAYER M2 ;
      RECT 7.119 385.560 7.137 385.830 ;
    END
  END r0_rd_out[268]
  PIN r0_rd_out[269]
    DIRECTION OUTPUT ;
    USE SIGNAL ;
    SHAPE ABUTMENT ;
    PORT
      LAYER M2 ;
      RECT 7.695 385.560 7.713 385.830 ;
    END
  END r0_rd_out[269]
  PIN r0_rd_out[270]
    DIRECTION OUTPUT ;
    USE SIGNAL ;
    SHAPE ABUTMENT ;
    PORT
      LAYER M2 ;
      RECT 8.271 385.560 8.289 385.830 ;
    END
  END r0_rd_out[270]
  PIN r0_rd_out[271]
    DIRECTION OUTPUT ;
    USE SIGNAL ;
    SHAPE ABUTMENT ;
    PORT
      LAYER M2 ;
      RECT 8.847 385.560 8.865 385.830 ;
    END
  END r0_rd_out[271]
  PIN r0_rd_out[272]
    DIRECTION OUTPUT ;
    USE SIGNAL ;
    SHAPE ABUTMENT ;
    PORT
      LAYER M2 ;
      RECT 9.423 385.560 9.441 385.830 ;
    END
  END r0_rd_out[272]
  PIN r0_rd_out[273]
    DIRECTION OUTPUT ;
    USE SIGNAL ;
    SHAPE ABUTMENT ;
    PORT
      LAYER M2 ;
      RECT 9.999 385.560 10.017 385.830 ;
    END
  END r0_rd_out[273]
  PIN r0_rd_out[274]
    DIRECTION OUTPUT ;
    USE SIGNAL ;
    SHAPE ABUTMENT ;
    PORT
      LAYER M2 ;
      RECT 10.575 385.560 10.593 385.830 ;
    END
  END r0_rd_out[274]
  PIN r0_rd_out[275]
    DIRECTION OUTPUT ;
    USE SIGNAL ;
    SHAPE ABUTMENT ;
    PORT
      LAYER M2 ;
      RECT 11.151 385.560 11.169 385.830 ;
    END
  END r0_rd_out[275]
  PIN r0_rd_out[276]
    DIRECTION OUTPUT ;
    USE SIGNAL ;
    SHAPE ABUTMENT ;
    PORT
      LAYER M2 ;
      RECT 11.727 385.560 11.745 385.830 ;
    END
  END r0_rd_out[276]
  PIN r0_rd_out[277]
    DIRECTION OUTPUT ;
    USE SIGNAL ;
    SHAPE ABUTMENT ;
    PORT
      LAYER M2 ;
      RECT 12.303 385.560 12.321 385.830 ;
    END
  END r0_rd_out[277]
  PIN r0_rd_out[278]
    DIRECTION OUTPUT ;
    USE SIGNAL ;
    SHAPE ABUTMENT ;
    PORT
      LAYER M2 ;
      RECT 12.879 385.560 12.897 385.830 ;
    END
  END r0_rd_out[278]
  PIN r0_rd_out[279]
    DIRECTION OUTPUT ;
    USE SIGNAL ;
    SHAPE ABUTMENT ;
    PORT
      LAYER M2 ;
      RECT 13.455 385.560 13.473 385.830 ;
    END
  END r0_rd_out[279]
  PIN r0_rd_out[280]
    DIRECTION OUTPUT ;
    USE SIGNAL ;
    SHAPE ABUTMENT ;
    PORT
      LAYER M2 ;
      RECT 14.031 385.560 14.049 385.830 ;
    END
  END r0_rd_out[280]
  PIN r0_rd_out[281]
    DIRECTION OUTPUT ;
    USE SIGNAL ;
    SHAPE ABUTMENT ;
    PORT
      LAYER M2 ;
      RECT 14.607 385.560 14.625 385.830 ;
    END
  END r0_rd_out[281]
  PIN r0_rd_out[282]
    DIRECTION OUTPUT ;
    USE SIGNAL ;
    SHAPE ABUTMENT ;
    PORT
      LAYER M2 ;
      RECT 15.183 385.560 15.201 385.830 ;
    END
  END r0_rd_out[282]
  PIN r0_rd_out[283]
    DIRECTION OUTPUT ;
    USE SIGNAL ;
    SHAPE ABUTMENT ;
    PORT
      LAYER M2 ;
      RECT 15.759 385.560 15.777 385.830 ;
    END
  END r0_rd_out[283]
  PIN r0_rd_out[284]
    DIRECTION OUTPUT ;
    USE SIGNAL ;
    SHAPE ABUTMENT ;
    PORT
      LAYER M2 ;
      RECT 16.335 385.560 16.353 385.830 ;
    END
  END r0_rd_out[284]
  PIN r0_rd_out[285]
    DIRECTION OUTPUT ;
    USE SIGNAL ;
    SHAPE ABUTMENT ;
    PORT
      LAYER M2 ;
      RECT 16.911 385.560 16.929 385.830 ;
    END
  END r0_rd_out[285]
  PIN r0_rd_out[286]
    DIRECTION OUTPUT ;
    USE SIGNAL ;
    SHAPE ABUTMENT ;
    PORT
      LAYER M2 ;
      RECT 17.487 385.560 17.505 385.830 ;
    END
  END r0_rd_out[286]
  PIN r0_rd_out[287]
    DIRECTION OUTPUT ;
    USE SIGNAL ;
    SHAPE ABUTMENT ;
    PORT
      LAYER M2 ;
      RECT 18.063 385.560 18.081 385.830 ;
    END
  END r0_rd_out[287]
  PIN r0_rd_out[288]
    DIRECTION OUTPUT ;
    USE SIGNAL ;
    SHAPE ABUTMENT ;
    PORT
      LAYER M2 ;
      RECT 18.639 385.560 18.657 385.830 ;
    END
  END r0_rd_out[288]
  PIN r0_rd_out[289]
    DIRECTION OUTPUT ;
    USE SIGNAL ;
    SHAPE ABUTMENT ;
    PORT
      LAYER M2 ;
      RECT 19.215 385.560 19.233 385.830 ;
    END
  END r0_rd_out[289]
  PIN r0_rd_out[290]
    DIRECTION OUTPUT ;
    USE SIGNAL ;
    SHAPE ABUTMENT ;
    PORT
      LAYER M2 ;
      RECT 19.791 385.560 19.809 385.830 ;
    END
  END r0_rd_out[290]
  PIN r0_rd_out[291]
    DIRECTION OUTPUT ;
    USE SIGNAL ;
    SHAPE ABUTMENT ;
    PORT
      LAYER M2 ;
      RECT 20.367 385.560 20.385 385.830 ;
    END
  END r0_rd_out[291]
  PIN r0_rd_out[292]
    DIRECTION OUTPUT ;
    USE SIGNAL ;
    SHAPE ABUTMENT ;
    PORT
      LAYER M2 ;
      RECT 20.943 385.560 20.961 385.830 ;
    END
  END r0_rd_out[292]
  PIN r0_rd_out[293]
    DIRECTION OUTPUT ;
    USE SIGNAL ;
    SHAPE ABUTMENT ;
    PORT
      LAYER M2 ;
      RECT 21.519 385.560 21.537 385.830 ;
    END
  END r0_rd_out[293]
  PIN r0_rd_out[294]
    DIRECTION OUTPUT ;
    USE SIGNAL ;
    SHAPE ABUTMENT ;
    PORT
      LAYER M2 ;
      RECT 22.095 385.560 22.113 385.830 ;
    END
  END r0_rd_out[294]
  PIN r0_rd_out[295]
    DIRECTION OUTPUT ;
    USE SIGNAL ;
    SHAPE ABUTMENT ;
    PORT
      LAYER M2 ;
      RECT 22.671 385.560 22.689 385.830 ;
    END
  END r0_rd_out[295]
  PIN r0_rd_out[296]
    DIRECTION OUTPUT ;
    USE SIGNAL ;
    SHAPE ABUTMENT ;
    PORT
      LAYER M2 ;
      RECT 23.247 385.560 23.265 385.830 ;
    END
  END r0_rd_out[296]
  PIN r0_rd_out[297]
    DIRECTION OUTPUT ;
    USE SIGNAL ;
    SHAPE ABUTMENT ;
    PORT
      LAYER M2 ;
      RECT 23.823 385.560 23.841 385.830 ;
    END
  END r0_rd_out[297]
  PIN r0_rd_out[298]
    DIRECTION OUTPUT ;
    USE SIGNAL ;
    SHAPE ABUTMENT ;
    PORT
      LAYER M2 ;
      RECT 24.399 385.560 24.417 385.830 ;
    END
  END r0_rd_out[298]
  PIN r0_rd_out[299]
    DIRECTION OUTPUT ;
    USE SIGNAL ;
    SHAPE ABUTMENT ;
    PORT
      LAYER M2 ;
      RECT 24.975 385.560 24.993 385.830 ;
    END
  END r0_rd_out[299]
  PIN r0_rd_out[300]
    DIRECTION OUTPUT ;
    USE SIGNAL ;
    SHAPE ABUTMENT ;
    PORT
      LAYER M2 ;
      RECT 25.551 385.560 25.569 385.830 ;
    END
  END r0_rd_out[300]
  PIN r0_rd_out[301]
    DIRECTION OUTPUT ;
    USE SIGNAL ;
    SHAPE ABUTMENT ;
    PORT
      LAYER M2 ;
      RECT 26.127 385.560 26.145 385.830 ;
    END
  END r0_rd_out[301]
  PIN r0_rd_out[302]
    DIRECTION OUTPUT ;
    USE SIGNAL ;
    SHAPE ABUTMENT ;
    PORT
      LAYER M2 ;
      RECT 26.703 385.560 26.721 385.830 ;
    END
  END r0_rd_out[302]
  PIN r0_rd_out[303]
    DIRECTION OUTPUT ;
    USE SIGNAL ;
    SHAPE ABUTMENT ;
    PORT
      LAYER M2 ;
      RECT 27.279 385.560 27.297 385.830 ;
    END
  END r0_rd_out[303]
  PIN r0_rd_out[304]
    DIRECTION OUTPUT ;
    USE SIGNAL ;
    SHAPE ABUTMENT ;
    PORT
      LAYER M2 ;
      RECT 27.855 385.560 27.873 385.830 ;
    END
  END r0_rd_out[304]
  PIN r0_rd_out[305]
    DIRECTION OUTPUT ;
    USE SIGNAL ;
    SHAPE ABUTMENT ;
    PORT
      LAYER M2 ;
      RECT 28.431 385.560 28.449 385.830 ;
    END
  END r0_rd_out[305]
  PIN r0_rd_out[306]
    DIRECTION OUTPUT ;
    USE SIGNAL ;
    SHAPE ABUTMENT ;
    PORT
      LAYER M2 ;
      RECT 29.007 385.560 29.025 385.830 ;
    END
  END r0_rd_out[306]
  PIN r0_rd_out[307]
    DIRECTION OUTPUT ;
    USE SIGNAL ;
    SHAPE ABUTMENT ;
    PORT
      LAYER M2 ;
      RECT 29.583 385.560 29.601 385.830 ;
    END
  END r0_rd_out[307]
  PIN r0_rd_out[308]
    DIRECTION OUTPUT ;
    USE SIGNAL ;
    SHAPE ABUTMENT ;
    PORT
      LAYER M2 ;
      RECT 30.159 385.560 30.177 385.830 ;
    END
  END r0_rd_out[308]
  PIN r0_rd_out[309]
    DIRECTION OUTPUT ;
    USE SIGNAL ;
    SHAPE ABUTMENT ;
    PORT
      LAYER M2 ;
      RECT 30.735 385.560 30.753 385.830 ;
    END
  END r0_rd_out[309]
  PIN r0_rd_out[310]
    DIRECTION OUTPUT ;
    USE SIGNAL ;
    SHAPE ABUTMENT ;
    PORT
      LAYER M2 ;
      RECT 31.311 385.560 31.329 385.830 ;
    END
  END r0_rd_out[310]
  PIN r0_rd_out[311]
    DIRECTION OUTPUT ;
    USE SIGNAL ;
    SHAPE ABUTMENT ;
    PORT
      LAYER M2 ;
      RECT 31.887 385.560 31.905 385.830 ;
    END
  END r0_rd_out[311]
  PIN r0_rd_out[312]
    DIRECTION OUTPUT ;
    USE SIGNAL ;
    SHAPE ABUTMENT ;
    PORT
      LAYER M2 ;
      RECT 32.463 385.560 32.481 385.830 ;
    END
  END r0_rd_out[312]
  PIN r0_rd_out[313]
    DIRECTION OUTPUT ;
    USE SIGNAL ;
    SHAPE ABUTMENT ;
    PORT
      LAYER M2 ;
      RECT 33.039 385.560 33.057 385.830 ;
    END
  END r0_rd_out[313]
  PIN r0_rd_out[314]
    DIRECTION OUTPUT ;
    USE SIGNAL ;
    SHAPE ABUTMENT ;
    PORT
      LAYER M2 ;
      RECT 33.615 385.560 33.633 385.830 ;
    END
  END r0_rd_out[314]
  PIN r0_rd_out[315]
    DIRECTION OUTPUT ;
    USE SIGNAL ;
    SHAPE ABUTMENT ;
    PORT
      LAYER M2 ;
      RECT 34.191 385.560 34.209 385.830 ;
    END
  END r0_rd_out[315]
  PIN r0_rd_out[316]
    DIRECTION OUTPUT ;
    USE SIGNAL ;
    SHAPE ABUTMENT ;
    PORT
      LAYER M2 ;
      RECT 34.767 385.560 34.785 385.830 ;
    END
  END r0_rd_out[316]
  PIN r0_rd_out[317]
    DIRECTION OUTPUT ;
    USE SIGNAL ;
    SHAPE ABUTMENT ;
    PORT
      LAYER M2 ;
      RECT 35.343 385.560 35.361 385.830 ;
    END
  END r0_rd_out[317]
  PIN r0_rd_out[318]
    DIRECTION OUTPUT ;
    USE SIGNAL ;
    SHAPE ABUTMENT ;
    PORT
      LAYER M2 ;
      RECT 35.919 385.560 35.937 385.830 ;
    END
  END r0_rd_out[318]
  PIN r0_rd_out[319]
    DIRECTION OUTPUT ;
    USE SIGNAL ;
    SHAPE ABUTMENT ;
    PORT
      LAYER M2 ;
      RECT 36.495 385.560 36.513 385.830 ;
    END
  END r0_rd_out[319]
  PIN r0_rd_out[320]
    DIRECTION OUTPUT ;
    USE SIGNAL ;
    SHAPE ABUTMENT ;
    PORT
      LAYER M2 ;
      RECT 37.071 385.560 37.089 385.830 ;
    END
  END r0_rd_out[320]
  PIN r0_rd_out[321]
    DIRECTION OUTPUT ;
    USE SIGNAL ;
    SHAPE ABUTMENT ;
    PORT
      LAYER M2 ;
      RECT 37.647 385.560 37.665 385.830 ;
    END
  END r0_rd_out[321]
  PIN r0_rd_out[322]
    DIRECTION OUTPUT ;
    USE SIGNAL ;
    SHAPE ABUTMENT ;
    PORT
      LAYER M2 ;
      RECT 38.223 385.560 38.241 385.830 ;
    END
  END r0_rd_out[322]
  PIN r0_rd_out[323]
    DIRECTION OUTPUT ;
    USE SIGNAL ;
    SHAPE ABUTMENT ;
    PORT
      LAYER M2 ;
      RECT 38.799 385.560 38.817 385.830 ;
    END
  END r0_rd_out[323]
  PIN r0_rd_out[324]
    DIRECTION OUTPUT ;
    USE SIGNAL ;
    SHAPE ABUTMENT ;
    PORT
      LAYER M2 ;
      RECT 39.375 385.560 39.393 385.830 ;
    END
  END r0_rd_out[324]
  PIN r0_rd_out[325]
    DIRECTION OUTPUT ;
    USE SIGNAL ;
    SHAPE ABUTMENT ;
    PORT
      LAYER M2 ;
      RECT 39.951 385.560 39.969 385.830 ;
    END
  END r0_rd_out[325]
  PIN r0_rd_out[326]
    DIRECTION OUTPUT ;
    USE SIGNAL ;
    SHAPE ABUTMENT ;
    PORT
      LAYER M2 ;
      RECT 40.527 385.560 40.545 385.830 ;
    END
  END r0_rd_out[326]
  PIN r0_rd_out[327]
    DIRECTION OUTPUT ;
    USE SIGNAL ;
    SHAPE ABUTMENT ;
    PORT
      LAYER M2 ;
      RECT 41.103 385.560 41.121 385.830 ;
    END
  END r0_rd_out[327]
  PIN r0_rd_out[328]
    DIRECTION OUTPUT ;
    USE SIGNAL ;
    SHAPE ABUTMENT ;
    PORT
      LAYER M2 ;
      RECT 41.679 385.560 41.697 385.830 ;
    END
  END r0_rd_out[328]
  PIN r0_rd_out[329]
    DIRECTION OUTPUT ;
    USE SIGNAL ;
    SHAPE ABUTMENT ;
    PORT
      LAYER M2 ;
      RECT 42.255 385.560 42.273 385.830 ;
    END
  END r0_rd_out[329]
  PIN r0_rd_out[330]
    DIRECTION OUTPUT ;
    USE SIGNAL ;
    SHAPE ABUTMENT ;
    PORT
      LAYER M2 ;
      RECT 42.831 385.560 42.849 385.830 ;
    END
  END r0_rd_out[330]
  PIN r0_rd_out[331]
    DIRECTION OUTPUT ;
    USE SIGNAL ;
    SHAPE ABUTMENT ;
    PORT
      LAYER M2 ;
      RECT 43.407 385.560 43.425 385.830 ;
    END
  END r0_rd_out[331]
  PIN r0_rd_out[332]
    DIRECTION OUTPUT ;
    USE SIGNAL ;
    SHAPE ABUTMENT ;
    PORT
      LAYER M2 ;
      RECT 43.983 385.560 44.001 385.830 ;
    END
  END r0_rd_out[332]
  PIN r0_rd_out[333]
    DIRECTION OUTPUT ;
    USE SIGNAL ;
    SHAPE ABUTMENT ;
    PORT
      LAYER M2 ;
      RECT 44.559 385.560 44.577 385.830 ;
    END
  END r0_rd_out[333]
  PIN r0_rd_out[334]
    DIRECTION OUTPUT ;
    USE SIGNAL ;
    SHAPE ABUTMENT ;
    PORT
      LAYER M2 ;
      RECT 45.135 385.560 45.153 385.830 ;
    END
  END r0_rd_out[334]
  PIN r0_rd_out[335]
    DIRECTION OUTPUT ;
    USE SIGNAL ;
    SHAPE ABUTMENT ;
    PORT
      LAYER M2 ;
      RECT 45.711 385.560 45.729 385.830 ;
    END
  END r0_rd_out[335]
  PIN r0_rd_out[336]
    DIRECTION OUTPUT ;
    USE SIGNAL ;
    SHAPE ABUTMENT ;
    PORT
      LAYER M2 ;
      RECT 46.287 385.560 46.305 385.830 ;
    END
  END r0_rd_out[336]
  PIN r0_rd_out[337]
    DIRECTION OUTPUT ;
    USE SIGNAL ;
    SHAPE ABUTMENT ;
    PORT
      LAYER M2 ;
      RECT 46.863 385.560 46.881 385.830 ;
    END
  END r0_rd_out[337]
  PIN r0_rd_out[338]
    DIRECTION OUTPUT ;
    USE SIGNAL ;
    SHAPE ABUTMENT ;
    PORT
      LAYER M2 ;
      RECT 47.439 385.560 47.457 385.830 ;
    END
  END r0_rd_out[338]
  PIN r0_rd_out[339]
    DIRECTION OUTPUT ;
    USE SIGNAL ;
    SHAPE ABUTMENT ;
    PORT
      LAYER M2 ;
      RECT 48.015 385.560 48.033 385.830 ;
    END
  END r0_rd_out[339]
  PIN r0_rd_out[340]
    DIRECTION OUTPUT ;
    USE SIGNAL ;
    SHAPE ABUTMENT ;
    PORT
      LAYER M2 ;
      RECT 48.591 385.560 48.609 385.830 ;
    END
  END r0_rd_out[340]
  PIN r0_rd_out[341]
    DIRECTION OUTPUT ;
    USE SIGNAL ;
    SHAPE ABUTMENT ;
    PORT
      LAYER M2 ;
      RECT 49.167 385.560 49.185 385.830 ;
    END
  END r0_rd_out[341]
  PIN r0_rd_out[342]
    DIRECTION OUTPUT ;
    USE SIGNAL ;
    SHAPE ABUTMENT ;
    PORT
      LAYER M2 ;
      RECT 49.743 385.560 49.761 385.830 ;
    END
  END r0_rd_out[342]
  PIN r0_rd_out[343]
    DIRECTION OUTPUT ;
    USE SIGNAL ;
    SHAPE ABUTMENT ;
    PORT
      LAYER M2 ;
      RECT 50.319 385.560 50.337 385.830 ;
    END
  END r0_rd_out[343]
  PIN r0_rd_out[344]
    DIRECTION OUTPUT ;
    USE SIGNAL ;
    SHAPE ABUTMENT ;
    PORT
      LAYER M2 ;
      RECT 50.895 385.560 50.913 385.830 ;
    END
  END r0_rd_out[344]
  PIN r0_rd_out[345]
    DIRECTION OUTPUT ;
    USE SIGNAL ;
    SHAPE ABUTMENT ;
    PORT
      LAYER M2 ;
      RECT 51.471 385.560 51.489 385.830 ;
    END
  END r0_rd_out[345]
  PIN r0_rd_out[346]
    DIRECTION OUTPUT ;
    USE SIGNAL ;
    SHAPE ABUTMENT ;
    PORT
      LAYER M2 ;
      RECT 52.047 385.560 52.065 385.830 ;
    END
  END r0_rd_out[346]
  PIN r0_rd_out[347]
    DIRECTION OUTPUT ;
    USE SIGNAL ;
    SHAPE ABUTMENT ;
    PORT
      LAYER M2 ;
      RECT 52.623 385.560 52.641 385.830 ;
    END
  END r0_rd_out[347]
  PIN r0_rd_out[348]
    DIRECTION OUTPUT ;
    USE SIGNAL ;
    SHAPE ABUTMENT ;
    PORT
      LAYER M2 ;
      RECT 53.199 385.560 53.217 385.830 ;
    END
  END r0_rd_out[348]
  PIN r0_rd_out[349]
    DIRECTION OUTPUT ;
    USE SIGNAL ;
    SHAPE ABUTMENT ;
    PORT
      LAYER M2 ;
      RECT 53.775 385.560 53.793 385.830 ;
    END
  END r0_rd_out[349]
  PIN r0_rd_out[350]
    DIRECTION OUTPUT ;
    USE SIGNAL ;
    SHAPE ABUTMENT ;
    PORT
      LAYER M2 ;
      RECT 54.351 385.560 54.369 385.830 ;
    END
  END r0_rd_out[350]
  PIN r0_rd_out[351]
    DIRECTION OUTPUT ;
    USE SIGNAL ;
    SHAPE ABUTMENT ;
    PORT
      LAYER M2 ;
      RECT 54.927 385.560 54.945 385.830 ;
    END
  END r0_rd_out[351]
  PIN r0_rd_out[352]
    DIRECTION OUTPUT ;
    USE SIGNAL ;
    SHAPE ABUTMENT ;
    PORT
      LAYER M2 ;
      RECT 55.503 385.560 55.521 385.830 ;
    END
  END r0_rd_out[352]
  PIN r0_rd_out[353]
    DIRECTION OUTPUT ;
    USE SIGNAL ;
    SHAPE ABUTMENT ;
    PORT
      LAYER M2 ;
      RECT 56.079 385.560 56.097 385.830 ;
    END
  END r0_rd_out[353]
  PIN r0_rd_out[354]
    DIRECTION OUTPUT ;
    USE SIGNAL ;
    SHAPE ABUTMENT ;
    PORT
      LAYER M2 ;
      RECT 56.655 385.560 56.673 385.830 ;
    END
  END r0_rd_out[354]
  PIN r0_rd_out[355]
    DIRECTION OUTPUT ;
    USE SIGNAL ;
    SHAPE ABUTMENT ;
    PORT
      LAYER M2 ;
      RECT 57.231 385.560 57.249 385.830 ;
    END
  END r0_rd_out[355]
  PIN r0_rd_out[356]
    DIRECTION OUTPUT ;
    USE SIGNAL ;
    SHAPE ABUTMENT ;
    PORT
      LAYER M2 ;
      RECT 57.807 385.560 57.825 385.830 ;
    END
  END r0_rd_out[356]
  PIN r0_rd_out[357]
    DIRECTION OUTPUT ;
    USE SIGNAL ;
    SHAPE ABUTMENT ;
    PORT
      LAYER M2 ;
      RECT 58.383 385.560 58.401 385.830 ;
    END
  END r0_rd_out[357]
  PIN r0_rd_out[358]
    DIRECTION OUTPUT ;
    USE SIGNAL ;
    SHAPE ABUTMENT ;
    PORT
      LAYER M2 ;
      RECT 58.959 385.560 58.977 385.830 ;
    END
  END r0_rd_out[358]
  PIN r0_rd_out[359]
    DIRECTION OUTPUT ;
    USE SIGNAL ;
    SHAPE ABUTMENT ;
    PORT
      LAYER M2 ;
      RECT 59.535 385.560 59.553 385.830 ;
    END
  END r0_rd_out[359]
  PIN r0_rd_out[360]
    DIRECTION OUTPUT ;
    USE SIGNAL ;
    SHAPE ABUTMENT ;
    PORT
      LAYER M2 ;
      RECT 60.111 385.560 60.129 385.830 ;
    END
  END r0_rd_out[360]
  PIN r0_rd_out[361]
    DIRECTION OUTPUT ;
    USE SIGNAL ;
    SHAPE ABUTMENT ;
    PORT
      LAYER M2 ;
      RECT 60.687 385.560 60.705 385.830 ;
    END
  END r0_rd_out[361]
  PIN r0_rd_out[362]
    DIRECTION OUTPUT ;
    USE SIGNAL ;
    SHAPE ABUTMENT ;
    PORT
      LAYER M2 ;
      RECT 61.263 385.560 61.281 385.830 ;
    END
  END r0_rd_out[362]
  PIN r0_rd_out[363]
    DIRECTION OUTPUT ;
    USE SIGNAL ;
    SHAPE ABUTMENT ;
    PORT
      LAYER M2 ;
      RECT 61.839 385.560 61.857 385.830 ;
    END
  END r0_rd_out[363]
  PIN r0_rd_out[364]
    DIRECTION OUTPUT ;
    USE SIGNAL ;
    SHAPE ABUTMENT ;
    PORT
      LAYER M2 ;
      RECT 62.415 385.560 62.433 385.830 ;
    END
  END r0_rd_out[364]
  PIN r0_rd_out[365]
    DIRECTION OUTPUT ;
    USE SIGNAL ;
    SHAPE ABUTMENT ;
    PORT
      LAYER M2 ;
      RECT 62.991 385.560 63.009 385.830 ;
    END
  END r0_rd_out[365]
  PIN r0_rd_out[366]
    DIRECTION OUTPUT ;
    USE SIGNAL ;
    SHAPE ABUTMENT ;
    PORT
      LAYER M2 ;
      RECT 63.567 385.560 63.585 385.830 ;
    END
  END r0_rd_out[366]
  PIN r0_rd_out[367]
    DIRECTION OUTPUT ;
    USE SIGNAL ;
    SHAPE ABUTMENT ;
    PORT
      LAYER M2 ;
      RECT 64.143 385.560 64.161 385.830 ;
    END
  END r0_rd_out[367]
  PIN r0_rd_out[368]
    DIRECTION OUTPUT ;
    USE SIGNAL ;
    SHAPE ABUTMENT ;
    PORT
      LAYER M2 ;
      RECT 64.719 385.560 64.737 385.830 ;
    END
  END r0_rd_out[368]
  PIN r0_rd_out[369]
    DIRECTION OUTPUT ;
    USE SIGNAL ;
    SHAPE ABUTMENT ;
    PORT
      LAYER M2 ;
      RECT 65.295 385.560 65.313 385.830 ;
    END
  END r0_rd_out[369]
  PIN r0_rd_out[370]
    DIRECTION OUTPUT ;
    USE SIGNAL ;
    SHAPE ABUTMENT ;
    PORT
      LAYER M2 ;
      RECT 65.871 385.560 65.889 385.830 ;
    END
  END r0_rd_out[370]
  PIN r0_rd_out[371]
    DIRECTION OUTPUT ;
    USE SIGNAL ;
    SHAPE ABUTMENT ;
    PORT
      LAYER M2 ;
      RECT 66.447 385.560 66.465 385.830 ;
    END
  END r0_rd_out[371]
  PIN r0_rd_out[372]
    DIRECTION OUTPUT ;
    USE SIGNAL ;
    SHAPE ABUTMENT ;
    PORT
      LAYER M2 ;
      RECT 67.023 385.560 67.041 385.830 ;
    END
  END r0_rd_out[372]
  PIN r0_rd_out[373]
    DIRECTION OUTPUT ;
    USE SIGNAL ;
    SHAPE ABUTMENT ;
    PORT
      LAYER M2 ;
      RECT 67.599 385.560 67.617 385.830 ;
    END
  END r0_rd_out[373]
  PIN r0_rd_out[374]
    DIRECTION OUTPUT ;
    USE SIGNAL ;
    SHAPE ABUTMENT ;
    PORT
      LAYER M2 ;
      RECT 68.175 385.560 68.193 385.830 ;
    END
  END r0_rd_out[374]
  PIN r0_rd_out[375]
    DIRECTION OUTPUT ;
    USE SIGNAL ;
    SHAPE ABUTMENT ;
    PORT
      LAYER M2 ;
      RECT 68.751 385.560 68.769 385.830 ;
    END
  END r0_rd_out[375]
  PIN r0_rd_out[376]
    DIRECTION OUTPUT ;
    USE SIGNAL ;
    SHAPE ABUTMENT ;
    PORT
      LAYER M2 ;
      RECT 69.327 385.560 69.345 385.830 ;
    END
  END r0_rd_out[376]
  PIN r0_rd_out[377]
    DIRECTION OUTPUT ;
    USE SIGNAL ;
    SHAPE ABUTMENT ;
    PORT
      LAYER M2 ;
      RECT 69.903 385.560 69.921 385.830 ;
    END
  END r0_rd_out[377]
  PIN r0_rd_out[378]
    DIRECTION OUTPUT ;
    USE SIGNAL ;
    SHAPE ABUTMENT ;
    PORT
      LAYER M2 ;
      RECT 70.479 385.560 70.497 385.830 ;
    END
  END r0_rd_out[378]
  PIN r0_rd_out[379]
    DIRECTION OUTPUT ;
    USE SIGNAL ;
    SHAPE ABUTMENT ;
    PORT
      LAYER M2 ;
      RECT 71.055 385.560 71.073 385.830 ;
    END
  END r0_rd_out[379]
  PIN r0_rd_out[380]
    DIRECTION OUTPUT ;
    USE SIGNAL ;
    SHAPE ABUTMENT ;
    PORT
      LAYER M2 ;
      RECT 71.631 385.560 71.649 385.830 ;
    END
  END r0_rd_out[380]
  PIN r0_rd_out[381]
    DIRECTION OUTPUT ;
    USE SIGNAL ;
    SHAPE ABUTMENT ;
    PORT
      LAYER M2 ;
      RECT 72.207 385.560 72.225 385.830 ;
    END
  END r0_rd_out[381]
  PIN r0_rd_out[382]
    DIRECTION OUTPUT ;
    USE SIGNAL ;
    SHAPE ABUTMENT ;
    PORT
      LAYER M2 ;
      RECT 72.783 385.560 72.801 385.830 ;
    END
  END r0_rd_out[382]
  PIN r0_rd_out[383]
    DIRECTION OUTPUT ;
    USE SIGNAL ;
    SHAPE ABUTMENT ;
    PORT
      LAYER M2 ;
      RECT 73.359 385.560 73.377 385.830 ;
    END
  END r0_rd_out[383]
  PIN r0_rd_out[384]
    DIRECTION OUTPUT ;
    USE SIGNAL ;
    SHAPE ABUTMENT ;
    PORT
      LAYER M2 ;
      RECT 73.935 385.560 73.953 385.830 ;
    END
  END r0_rd_out[384]
  PIN r0_rd_out[385]
    DIRECTION OUTPUT ;
    USE SIGNAL ;
    SHAPE ABUTMENT ;
    PORT
      LAYER M2 ;
      RECT 74.511 385.560 74.529 385.830 ;
    END
  END r0_rd_out[385]
  PIN r0_rd_out[386]
    DIRECTION OUTPUT ;
    USE SIGNAL ;
    SHAPE ABUTMENT ;
    PORT
      LAYER M2 ;
      RECT 75.087 385.560 75.105 385.830 ;
    END
  END r0_rd_out[386]
  PIN r0_rd_out[387]
    DIRECTION OUTPUT ;
    USE SIGNAL ;
    SHAPE ABUTMENT ;
    PORT
      LAYER M2 ;
      RECT 75.663 385.560 75.681 385.830 ;
    END
  END r0_rd_out[387]
  PIN r0_rd_out[388]
    DIRECTION OUTPUT ;
    USE SIGNAL ;
    SHAPE ABUTMENT ;
    PORT
      LAYER M2 ;
      RECT 76.239 385.560 76.257 385.830 ;
    END
  END r0_rd_out[388]
  PIN r0_rd_out[389]
    DIRECTION OUTPUT ;
    USE SIGNAL ;
    SHAPE ABUTMENT ;
    PORT
      LAYER M2 ;
      RECT 76.815 385.560 76.833 385.830 ;
    END
  END r0_rd_out[389]
  PIN r0_rd_out[390]
    DIRECTION OUTPUT ;
    USE SIGNAL ;
    SHAPE ABUTMENT ;
    PORT
      LAYER M2 ;
      RECT 77.391 385.560 77.409 385.830 ;
    END
  END r0_rd_out[390]
  PIN r0_rd_out[391]
    DIRECTION OUTPUT ;
    USE SIGNAL ;
    SHAPE ABUTMENT ;
    PORT
      LAYER M2 ;
      RECT 77.967 385.560 77.985 385.830 ;
    END
  END r0_rd_out[391]
  PIN r0_rd_out[392]
    DIRECTION OUTPUT ;
    USE SIGNAL ;
    SHAPE ABUTMENT ;
    PORT
      LAYER M2 ;
      RECT 78.543 385.560 78.561 385.830 ;
    END
  END r0_rd_out[392]
  PIN r0_rd_out[393]
    DIRECTION OUTPUT ;
    USE SIGNAL ;
    SHAPE ABUTMENT ;
    PORT
      LAYER M2 ;
      RECT 79.119 385.560 79.137 385.830 ;
    END
  END r0_rd_out[393]
  PIN r0_rd_out[394]
    DIRECTION OUTPUT ;
    USE SIGNAL ;
    SHAPE ABUTMENT ;
    PORT
      LAYER M2 ;
      RECT 79.695 385.560 79.713 385.830 ;
    END
  END r0_rd_out[394]
  PIN r0_rd_out[395]
    DIRECTION OUTPUT ;
    USE SIGNAL ;
    SHAPE ABUTMENT ;
    PORT
      LAYER M2 ;
      RECT 80.271 385.560 80.289 385.830 ;
    END
  END r0_rd_out[395]
  PIN r0_rd_out[396]
    DIRECTION OUTPUT ;
    USE SIGNAL ;
    SHAPE ABUTMENT ;
    PORT
      LAYER M2 ;
      RECT 80.847 385.560 80.865 385.830 ;
    END
  END r0_rd_out[396]
  PIN r0_rd_out[397]
    DIRECTION OUTPUT ;
    USE SIGNAL ;
    SHAPE ABUTMENT ;
    PORT
      LAYER M2 ;
      RECT 81.423 385.560 81.441 385.830 ;
    END
  END r0_rd_out[397]
  PIN r0_rd_out[398]
    DIRECTION OUTPUT ;
    USE SIGNAL ;
    SHAPE ABUTMENT ;
    PORT
      LAYER M2 ;
      RECT 81.999 385.560 82.017 385.830 ;
    END
  END r0_rd_out[398]
  PIN r0_rd_out[399]
    DIRECTION OUTPUT ;
    USE SIGNAL ;
    SHAPE ABUTMENT ;
    PORT
      LAYER M2 ;
      RECT 82.575 385.560 82.593 385.830 ;
    END
  END r0_rd_out[399]
  PIN r0_rd_out[400]
    DIRECTION OUTPUT ;
    USE SIGNAL ;
    SHAPE ABUTMENT ;
    PORT
      LAYER M2 ;
      RECT 83.151 385.560 83.169 385.830 ;
    END
  END r0_rd_out[400]
  PIN r0_rd_out[401]
    DIRECTION OUTPUT ;
    USE SIGNAL ;
    SHAPE ABUTMENT ;
    PORT
      LAYER M2 ;
      RECT 83.727 385.560 83.745 385.830 ;
    END
  END r0_rd_out[401]
  PIN r0_rd_out[402]
    DIRECTION OUTPUT ;
    USE SIGNAL ;
    SHAPE ABUTMENT ;
    PORT
      LAYER M2 ;
      RECT 84.303 385.560 84.321 385.830 ;
    END
  END r0_rd_out[402]
  PIN r0_rd_out[403]
    DIRECTION OUTPUT ;
    USE SIGNAL ;
    SHAPE ABUTMENT ;
    PORT
      LAYER M2 ;
      RECT 84.879 385.560 84.897 385.830 ;
    END
  END r0_rd_out[403]
  PIN r0_rd_out[404]
    DIRECTION OUTPUT ;
    USE SIGNAL ;
    SHAPE ABUTMENT ;
    PORT
      LAYER M2 ;
      RECT 85.455 385.560 85.473 385.830 ;
    END
  END r0_rd_out[404]
  PIN r0_rd_out[405]
    DIRECTION OUTPUT ;
    USE SIGNAL ;
    SHAPE ABUTMENT ;
    PORT
      LAYER M2 ;
      RECT 86.031 385.560 86.049 385.830 ;
    END
  END r0_rd_out[405]
  PIN r0_rd_out[406]
    DIRECTION OUTPUT ;
    USE SIGNAL ;
    SHAPE ABUTMENT ;
    PORT
      LAYER M2 ;
      RECT 86.607 385.560 86.625 385.830 ;
    END
  END r0_rd_out[406]
  PIN r0_rd_out[407]
    DIRECTION OUTPUT ;
    USE SIGNAL ;
    SHAPE ABUTMENT ;
    PORT
      LAYER M2 ;
      RECT 87.183 385.560 87.201 385.830 ;
    END
  END r0_rd_out[407]
  PIN r0_rd_out[408]
    DIRECTION OUTPUT ;
    USE SIGNAL ;
    SHAPE ABUTMENT ;
    PORT
      LAYER M2 ;
      RECT 87.759 385.560 87.777 385.830 ;
    END
  END r0_rd_out[408]
  PIN r0_rd_out[409]
    DIRECTION OUTPUT ;
    USE SIGNAL ;
    SHAPE ABUTMENT ;
    PORT
      LAYER M2 ;
      RECT 88.335 385.560 88.353 385.830 ;
    END
  END r0_rd_out[409]
  PIN r0_rd_out[410]
    DIRECTION OUTPUT ;
    USE SIGNAL ;
    SHAPE ABUTMENT ;
    PORT
      LAYER M2 ;
      RECT 88.911 385.560 88.929 385.830 ;
    END
  END r0_rd_out[410]
  PIN r0_rd_out[411]
    DIRECTION OUTPUT ;
    USE SIGNAL ;
    SHAPE ABUTMENT ;
    PORT
      LAYER M2 ;
      RECT 89.487 385.560 89.505 385.830 ;
    END
  END r0_rd_out[411]
  PIN r0_rd_out[412]
    DIRECTION OUTPUT ;
    USE SIGNAL ;
    SHAPE ABUTMENT ;
    PORT
      LAYER M2 ;
      RECT 90.063 385.560 90.081 385.830 ;
    END
  END r0_rd_out[412]
  PIN r0_rd_out[413]
    DIRECTION OUTPUT ;
    USE SIGNAL ;
    SHAPE ABUTMENT ;
    PORT
      LAYER M2 ;
      RECT 90.639 385.560 90.657 385.830 ;
    END
  END r0_rd_out[413]
  PIN r0_rd_out[414]
    DIRECTION OUTPUT ;
    USE SIGNAL ;
    SHAPE ABUTMENT ;
    PORT
      LAYER M2 ;
      RECT 91.215 385.560 91.233 385.830 ;
    END
  END r0_rd_out[414]
  PIN r0_rd_out[415]
    DIRECTION OUTPUT ;
    USE SIGNAL ;
    SHAPE ABUTMENT ;
    PORT
      LAYER M2 ;
      RECT 91.791 385.560 91.809 385.830 ;
    END
  END r0_rd_out[415]
  PIN r0_rd_out[416]
    DIRECTION OUTPUT ;
    USE SIGNAL ;
    SHAPE ABUTMENT ;
    PORT
      LAYER M2 ;
      RECT 92.367 385.560 92.385 385.830 ;
    END
  END r0_rd_out[416]
  PIN r0_rd_out[417]
    DIRECTION OUTPUT ;
    USE SIGNAL ;
    SHAPE ABUTMENT ;
    PORT
      LAYER M2 ;
      RECT 92.943 385.560 92.961 385.830 ;
    END
  END r0_rd_out[417]
  PIN r0_rd_out[418]
    DIRECTION OUTPUT ;
    USE SIGNAL ;
    SHAPE ABUTMENT ;
    PORT
      LAYER M2 ;
      RECT 93.519 385.560 93.537 385.830 ;
    END
  END r0_rd_out[418]
  PIN r0_rd_out[419]
    DIRECTION OUTPUT ;
    USE SIGNAL ;
    SHAPE ABUTMENT ;
    PORT
      LAYER M2 ;
      RECT 94.095 385.560 94.113 385.830 ;
    END
  END r0_rd_out[419]
  PIN r0_rd_out[420]
    DIRECTION OUTPUT ;
    USE SIGNAL ;
    SHAPE ABUTMENT ;
    PORT
      LAYER M2 ;
      RECT 94.671 385.560 94.689 385.830 ;
    END
  END r0_rd_out[420]
  PIN r0_rd_out[421]
    DIRECTION OUTPUT ;
    USE SIGNAL ;
    SHAPE ABUTMENT ;
    PORT
      LAYER M2 ;
      RECT 95.247 385.560 95.265 385.830 ;
    END
  END r0_rd_out[421]
  PIN r0_rd_out[422]
    DIRECTION OUTPUT ;
    USE SIGNAL ;
    SHAPE ABUTMENT ;
    PORT
      LAYER M2 ;
      RECT 95.823 385.560 95.841 385.830 ;
    END
  END r0_rd_out[422]
  PIN r0_rd_out[423]
    DIRECTION OUTPUT ;
    USE SIGNAL ;
    SHAPE ABUTMENT ;
    PORT
      LAYER M2 ;
      RECT 96.399 385.560 96.417 385.830 ;
    END
  END r0_rd_out[423]
  PIN r0_rd_out[424]
    DIRECTION OUTPUT ;
    USE SIGNAL ;
    SHAPE ABUTMENT ;
    PORT
      LAYER M2 ;
      RECT 96.975 385.560 96.993 385.830 ;
    END
  END r0_rd_out[424]
  PIN r0_rd_out[425]
    DIRECTION OUTPUT ;
    USE SIGNAL ;
    SHAPE ABUTMENT ;
    PORT
      LAYER M2 ;
      RECT 97.551 385.560 97.569 385.830 ;
    END
  END r0_rd_out[425]
  PIN r0_rd_out[426]
    DIRECTION OUTPUT ;
    USE SIGNAL ;
    SHAPE ABUTMENT ;
    PORT
      LAYER M2 ;
      RECT 98.127 385.560 98.145 385.830 ;
    END
  END r0_rd_out[426]
  PIN r0_rd_out[427]
    DIRECTION OUTPUT ;
    USE SIGNAL ;
    SHAPE ABUTMENT ;
    PORT
      LAYER M2 ;
      RECT 98.703 385.560 98.721 385.830 ;
    END
  END r0_rd_out[427]
  PIN r0_rd_out[428]
    DIRECTION OUTPUT ;
    USE SIGNAL ;
    SHAPE ABUTMENT ;
    PORT
      LAYER M2 ;
      RECT 99.279 385.560 99.297 385.830 ;
    END
  END r0_rd_out[428]
  PIN r0_rd_out[429]
    DIRECTION OUTPUT ;
    USE SIGNAL ;
    SHAPE ABUTMENT ;
    PORT
      LAYER M2 ;
      RECT 99.855 385.560 99.873 385.830 ;
    END
  END r0_rd_out[429]
  PIN r0_rd_out[430]
    DIRECTION OUTPUT ;
    USE SIGNAL ;
    SHAPE ABUTMENT ;
    PORT
      LAYER M2 ;
      RECT 100.431 385.560 100.449 385.830 ;
    END
  END r0_rd_out[430]
  PIN r0_rd_out[431]
    DIRECTION OUTPUT ;
    USE SIGNAL ;
    SHAPE ABUTMENT ;
    PORT
      LAYER M2 ;
      RECT 101.007 385.560 101.025 385.830 ;
    END
  END r0_rd_out[431]
  PIN r0_rd_out[432]
    DIRECTION OUTPUT ;
    USE SIGNAL ;
    SHAPE ABUTMENT ;
    PORT
      LAYER M2 ;
      RECT 101.583 385.560 101.601 385.830 ;
    END
  END r0_rd_out[432]
  PIN r0_rd_out[433]
    DIRECTION OUTPUT ;
    USE SIGNAL ;
    SHAPE ABUTMENT ;
    PORT
      LAYER M2 ;
      RECT 102.159 385.560 102.177 385.830 ;
    END
  END r0_rd_out[433]
  PIN r0_rd_out[434]
    DIRECTION OUTPUT ;
    USE SIGNAL ;
    SHAPE ABUTMENT ;
    PORT
      LAYER M2 ;
      RECT 102.735 385.560 102.753 385.830 ;
    END
  END r0_rd_out[434]
  PIN r0_rd_out[435]
    DIRECTION OUTPUT ;
    USE SIGNAL ;
    SHAPE ABUTMENT ;
    PORT
      LAYER M2 ;
      RECT 103.311 385.560 103.329 385.830 ;
    END
  END r0_rd_out[435]
  PIN r0_rd_out[436]
    DIRECTION OUTPUT ;
    USE SIGNAL ;
    SHAPE ABUTMENT ;
    PORT
      LAYER M2 ;
      RECT 103.887 385.560 103.905 385.830 ;
    END
  END r0_rd_out[436]
  PIN r0_rd_out[437]
    DIRECTION OUTPUT ;
    USE SIGNAL ;
    SHAPE ABUTMENT ;
    PORT
      LAYER M2 ;
      RECT 104.463 385.560 104.481 385.830 ;
    END
  END r0_rd_out[437]
  PIN r0_rd_out[438]
    DIRECTION OUTPUT ;
    USE SIGNAL ;
    SHAPE ABUTMENT ;
    PORT
      LAYER M2 ;
      RECT 105.039 385.560 105.057 385.830 ;
    END
  END r0_rd_out[438]
  PIN r0_rd_out[439]
    DIRECTION OUTPUT ;
    USE SIGNAL ;
    SHAPE ABUTMENT ;
    PORT
      LAYER M2 ;
      RECT 105.615 385.560 105.633 385.830 ;
    END
  END r0_rd_out[439]
  PIN r0_rd_out[440]
    DIRECTION OUTPUT ;
    USE SIGNAL ;
    SHAPE ABUTMENT ;
    PORT
      LAYER M2 ;
      RECT 106.191 385.560 106.209 385.830 ;
    END
  END r0_rd_out[440]
  PIN r0_rd_out[441]
    DIRECTION OUTPUT ;
    USE SIGNAL ;
    SHAPE ABUTMENT ;
    PORT
      LAYER M2 ;
      RECT 106.767 385.560 106.785 385.830 ;
    END
  END r0_rd_out[441]
  PIN r0_rd_out[442]
    DIRECTION OUTPUT ;
    USE SIGNAL ;
    SHAPE ABUTMENT ;
    PORT
      LAYER M2 ;
      RECT 107.343 385.560 107.361 385.830 ;
    END
  END r0_rd_out[442]
  PIN r0_rd_out[443]
    DIRECTION OUTPUT ;
    USE SIGNAL ;
    SHAPE ABUTMENT ;
    PORT
      LAYER M2 ;
      RECT 107.919 385.560 107.937 385.830 ;
    END
  END r0_rd_out[443]
  PIN r0_rd_out[444]
    DIRECTION OUTPUT ;
    USE SIGNAL ;
    SHAPE ABUTMENT ;
    PORT
      LAYER M2 ;
      RECT 108.495 385.560 108.513 385.830 ;
    END
  END r0_rd_out[444]
  PIN r0_rd_out[445]
    DIRECTION OUTPUT ;
    USE SIGNAL ;
    SHAPE ABUTMENT ;
    PORT
      LAYER M2 ;
      RECT 109.071 385.560 109.089 385.830 ;
    END
  END r0_rd_out[445]
  PIN r0_rd_out[446]
    DIRECTION OUTPUT ;
    USE SIGNAL ;
    SHAPE ABUTMENT ;
    PORT
      LAYER M2 ;
      RECT 109.647 385.560 109.665 385.830 ;
    END
  END r0_rd_out[446]
  PIN r0_rd_out[447]
    DIRECTION OUTPUT ;
    USE SIGNAL ;
    SHAPE ABUTMENT ;
    PORT
      LAYER M2 ;
      RECT 110.223 385.560 110.241 385.830 ;
    END
  END r0_rd_out[447]
  PIN r0_rd_out[448]
    DIRECTION OUTPUT ;
    USE SIGNAL ;
    SHAPE ABUTMENT ;
    PORT
      LAYER M2 ;
      RECT 110.799 385.560 110.817 385.830 ;
    END
  END r0_rd_out[448]
  PIN r0_rd_out[449]
    DIRECTION OUTPUT ;
    USE SIGNAL ;
    SHAPE ABUTMENT ;
    PORT
      LAYER M2 ;
      RECT 111.375 385.560 111.393 385.830 ;
    END
  END r0_rd_out[449]
  PIN r0_rd_out[450]
    DIRECTION OUTPUT ;
    USE SIGNAL ;
    SHAPE ABUTMENT ;
    PORT
      LAYER M2 ;
      RECT 111.951 385.560 111.969 385.830 ;
    END
  END r0_rd_out[450]
  PIN r0_rd_out[451]
    DIRECTION OUTPUT ;
    USE SIGNAL ;
    SHAPE ABUTMENT ;
    PORT
      LAYER M2 ;
      RECT 112.527 385.560 112.545 385.830 ;
    END
  END r0_rd_out[451]
  PIN r0_rd_out[452]
    DIRECTION OUTPUT ;
    USE SIGNAL ;
    SHAPE ABUTMENT ;
    PORT
      LAYER M2 ;
      RECT 113.103 385.560 113.121 385.830 ;
    END
  END r0_rd_out[452]
  PIN r0_rd_out[453]
    DIRECTION OUTPUT ;
    USE SIGNAL ;
    SHAPE ABUTMENT ;
    PORT
      LAYER M2 ;
      RECT 113.679 385.560 113.697 385.830 ;
    END
  END r0_rd_out[453]
  PIN r0_rd_out[454]
    DIRECTION OUTPUT ;
    USE SIGNAL ;
    SHAPE ABUTMENT ;
    PORT
      LAYER M2 ;
      RECT 114.255 385.560 114.273 385.830 ;
    END
  END r0_rd_out[454]
  PIN r0_rd_out[455]
    DIRECTION OUTPUT ;
    USE SIGNAL ;
    SHAPE ABUTMENT ;
    PORT
      LAYER M2 ;
      RECT 114.831 385.560 114.849 385.830 ;
    END
  END r0_rd_out[455]
  PIN r0_rd_out[456]
    DIRECTION OUTPUT ;
    USE SIGNAL ;
    SHAPE ABUTMENT ;
    PORT
      LAYER M2 ;
      RECT 115.407 385.560 115.425 385.830 ;
    END
  END r0_rd_out[456]
  PIN r0_rd_out[457]
    DIRECTION OUTPUT ;
    USE SIGNAL ;
    SHAPE ABUTMENT ;
    PORT
      LAYER M2 ;
      RECT 115.983 385.560 116.001 385.830 ;
    END
  END r0_rd_out[457]
  PIN r0_rd_out[458]
    DIRECTION OUTPUT ;
    USE SIGNAL ;
    SHAPE ABUTMENT ;
    PORT
      LAYER M2 ;
      RECT 116.559 385.560 116.577 385.830 ;
    END
  END r0_rd_out[458]
  PIN r0_rd_out[459]
    DIRECTION OUTPUT ;
    USE SIGNAL ;
    SHAPE ABUTMENT ;
    PORT
      LAYER M2 ;
      RECT 117.135 385.560 117.153 385.830 ;
    END
  END r0_rd_out[459]
  PIN r0_rd_out[460]
    DIRECTION OUTPUT ;
    USE SIGNAL ;
    SHAPE ABUTMENT ;
    PORT
      LAYER M2 ;
      RECT 117.711 385.560 117.729 385.830 ;
    END
  END r0_rd_out[460]
  PIN r0_rd_out[461]
    DIRECTION OUTPUT ;
    USE SIGNAL ;
    SHAPE ABUTMENT ;
    PORT
      LAYER M2 ;
      RECT 118.287 385.560 118.305 385.830 ;
    END
  END r0_rd_out[461]
  PIN r0_rd_out[462]
    DIRECTION OUTPUT ;
    USE SIGNAL ;
    SHAPE ABUTMENT ;
    PORT
      LAYER M2 ;
      RECT 118.863 385.560 118.881 385.830 ;
    END
  END r0_rd_out[462]
  PIN r0_rd_out[463]
    DIRECTION OUTPUT ;
    USE SIGNAL ;
    SHAPE ABUTMENT ;
    PORT
      LAYER M2 ;
      RECT 119.439 385.560 119.457 385.830 ;
    END
  END r0_rd_out[463]
  PIN r0_rd_out[464]
    DIRECTION OUTPUT ;
    USE SIGNAL ;
    SHAPE ABUTMENT ;
    PORT
      LAYER M2 ;
      RECT 120.015 385.560 120.033 385.830 ;
    END
  END r0_rd_out[464]
  PIN r0_rd_out[465]
    DIRECTION OUTPUT ;
    USE SIGNAL ;
    SHAPE ABUTMENT ;
    PORT
      LAYER M2 ;
      RECT 120.591 385.560 120.609 385.830 ;
    END
  END r0_rd_out[465]
  PIN r0_rd_out[466]
    DIRECTION OUTPUT ;
    USE SIGNAL ;
    SHAPE ABUTMENT ;
    PORT
      LAYER M2 ;
      RECT 121.167 385.560 121.185 385.830 ;
    END
  END r0_rd_out[466]
  PIN r0_rd_out[467]
    DIRECTION OUTPUT ;
    USE SIGNAL ;
    SHAPE ABUTMENT ;
    PORT
      LAYER M2 ;
      RECT 121.743 385.560 121.761 385.830 ;
    END
  END r0_rd_out[467]
  PIN r0_rd_out[468]
    DIRECTION OUTPUT ;
    USE SIGNAL ;
    SHAPE ABUTMENT ;
    PORT
      LAYER M2 ;
      RECT 122.319 385.560 122.337 385.830 ;
    END
  END r0_rd_out[468]
  PIN r0_rd_out[469]
    DIRECTION OUTPUT ;
    USE SIGNAL ;
    SHAPE ABUTMENT ;
    PORT
      LAYER M2 ;
      RECT 122.895 385.560 122.913 385.830 ;
    END
  END r0_rd_out[469]
  PIN r0_rd_out[470]
    DIRECTION OUTPUT ;
    USE SIGNAL ;
    SHAPE ABUTMENT ;
    PORT
      LAYER M2 ;
      RECT 123.471 385.560 123.489 385.830 ;
    END
  END r0_rd_out[470]
  PIN r0_rd_out[471]
    DIRECTION OUTPUT ;
    USE SIGNAL ;
    SHAPE ABUTMENT ;
    PORT
      LAYER M2 ;
      RECT 124.047 385.560 124.065 385.830 ;
    END
  END r0_rd_out[471]
  PIN r0_rd_out[472]
    DIRECTION OUTPUT ;
    USE SIGNAL ;
    SHAPE ABUTMENT ;
    PORT
      LAYER M2 ;
      RECT 124.623 385.560 124.641 385.830 ;
    END
  END r0_rd_out[472]
  PIN r0_rd_out[473]
    DIRECTION OUTPUT ;
    USE SIGNAL ;
    SHAPE ABUTMENT ;
    PORT
      LAYER M2 ;
      RECT 125.199 385.560 125.217 385.830 ;
    END
  END r0_rd_out[473]
  PIN r0_rd_out[474]
    DIRECTION OUTPUT ;
    USE SIGNAL ;
    SHAPE ABUTMENT ;
    PORT
      LAYER M2 ;
      RECT 125.775 385.560 125.793 385.830 ;
    END
  END r0_rd_out[474]
  PIN r0_rd_out[475]
    DIRECTION OUTPUT ;
    USE SIGNAL ;
    SHAPE ABUTMENT ;
    PORT
      LAYER M2 ;
      RECT 126.351 385.560 126.369 385.830 ;
    END
  END r0_rd_out[475]
  PIN r0_rd_out[476]
    DIRECTION OUTPUT ;
    USE SIGNAL ;
    SHAPE ABUTMENT ;
    PORT
      LAYER M2 ;
      RECT 126.927 385.560 126.945 385.830 ;
    END
  END r0_rd_out[476]
  PIN r0_rd_out[477]
    DIRECTION OUTPUT ;
    USE SIGNAL ;
    SHAPE ABUTMENT ;
    PORT
      LAYER M2 ;
      RECT 127.503 385.560 127.521 385.830 ;
    END
  END r0_rd_out[477]
  PIN r0_rd_out[478]
    DIRECTION OUTPUT ;
    USE SIGNAL ;
    SHAPE ABUTMENT ;
    PORT
      LAYER M2 ;
      RECT 128.079 385.560 128.097 385.830 ;
    END
  END r0_rd_out[478]
  PIN r0_rd_out[479]
    DIRECTION OUTPUT ;
    USE SIGNAL ;
    SHAPE ABUTMENT ;
    PORT
      LAYER M2 ;
      RECT 128.655 385.560 128.673 385.830 ;
    END
  END r0_rd_out[479]
  PIN r0_rd_out[480]
    DIRECTION OUTPUT ;
    USE SIGNAL ;
    SHAPE ABUTMENT ;
    PORT
      LAYER M2 ;
      RECT 129.231 385.560 129.249 385.830 ;
    END
  END r0_rd_out[480]
  PIN r0_rd_out[481]
    DIRECTION OUTPUT ;
    USE SIGNAL ;
    SHAPE ABUTMENT ;
    PORT
      LAYER M2 ;
      RECT 129.807 385.560 129.825 385.830 ;
    END
  END r0_rd_out[481]
  PIN r0_rd_out[482]
    DIRECTION OUTPUT ;
    USE SIGNAL ;
    SHAPE ABUTMENT ;
    PORT
      LAYER M2 ;
      RECT 130.383 385.560 130.401 385.830 ;
    END
  END r0_rd_out[482]
  PIN r0_rd_out[483]
    DIRECTION OUTPUT ;
    USE SIGNAL ;
    SHAPE ABUTMENT ;
    PORT
      LAYER M2 ;
      RECT 130.959 385.560 130.977 385.830 ;
    END
  END r0_rd_out[483]
  PIN r0_rd_out[484]
    DIRECTION OUTPUT ;
    USE SIGNAL ;
    SHAPE ABUTMENT ;
    PORT
      LAYER M2 ;
      RECT 131.535 385.560 131.553 385.830 ;
    END
  END r0_rd_out[484]
  PIN r0_rd_out[485]
    DIRECTION OUTPUT ;
    USE SIGNAL ;
    SHAPE ABUTMENT ;
    PORT
      LAYER M2 ;
      RECT 132.111 385.560 132.129 385.830 ;
    END
  END r0_rd_out[485]
  PIN r0_rd_out[486]
    DIRECTION OUTPUT ;
    USE SIGNAL ;
    SHAPE ABUTMENT ;
    PORT
      LAYER M2 ;
      RECT 132.687 385.560 132.705 385.830 ;
    END
  END r0_rd_out[486]
  PIN r0_rd_out[487]
    DIRECTION OUTPUT ;
    USE SIGNAL ;
    SHAPE ABUTMENT ;
    PORT
      LAYER M2 ;
      RECT 133.263 385.560 133.281 385.830 ;
    END
  END r0_rd_out[487]
  PIN r0_rd_out[488]
    DIRECTION OUTPUT ;
    USE SIGNAL ;
    SHAPE ABUTMENT ;
    PORT
      LAYER M2 ;
      RECT 133.839 385.560 133.857 385.830 ;
    END
  END r0_rd_out[488]
  PIN r0_rd_out[489]
    DIRECTION OUTPUT ;
    USE SIGNAL ;
    SHAPE ABUTMENT ;
    PORT
      LAYER M2 ;
      RECT 134.415 385.560 134.433 385.830 ;
    END
  END r0_rd_out[489]
  PIN r0_rd_out[490]
    DIRECTION OUTPUT ;
    USE SIGNAL ;
    SHAPE ABUTMENT ;
    PORT
      LAYER M2 ;
      RECT 134.991 385.560 135.009 385.830 ;
    END
  END r0_rd_out[490]
  PIN r0_rd_out[491]
    DIRECTION OUTPUT ;
    USE SIGNAL ;
    SHAPE ABUTMENT ;
    PORT
      LAYER M2 ;
      RECT 135.567 385.560 135.585 385.830 ;
    END
  END r0_rd_out[491]
  PIN r0_rd_out[492]
    DIRECTION OUTPUT ;
    USE SIGNAL ;
    SHAPE ABUTMENT ;
    PORT
      LAYER M2 ;
      RECT 136.143 385.560 136.161 385.830 ;
    END
  END r0_rd_out[492]
  PIN r0_rd_out[493]
    DIRECTION OUTPUT ;
    USE SIGNAL ;
    SHAPE ABUTMENT ;
    PORT
      LAYER M2 ;
      RECT 136.719 385.560 136.737 385.830 ;
    END
  END r0_rd_out[493]
  PIN r0_rd_out[494]
    DIRECTION OUTPUT ;
    USE SIGNAL ;
    SHAPE ABUTMENT ;
    PORT
      LAYER M2 ;
      RECT 137.295 385.560 137.313 385.830 ;
    END
  END r0_rd_out[494]
  PIN r0_rd_out[495]
    DIRECTION OUTPUT ;
    USE SIGNAL ;
    SHAPE ABUTMENT ;
    PORT
      LAYER M2 ;
      RECT 137.871 385.560 137.889 385.830 ;
    END
  END r0_rd_out[495]
  PIN r0_rd_out[496]
    DIRECTION OUTPUT ;
    USE SIGNAL ;
    SHAPE ABUTMENT ;
    PORT
      LAYER M2 ;
      RECT 138.447 385.560 138.465 385.830 ;
    END
  END r0_rd_out[496]
  PIN r0_rd_out[497]
    DIRECTION OUTPUT ;
    USE SIGNAL ;
    SHAPE ABUTMENT ;
    PORT
      LAYER M2 ;
      RECT 139.023 385.560 139.041 385.830 ;
    END
  END r0_rd_out[497]
  PIN r0_rd_out[498]
    DIRECTION OUTPUT ;
    USE SIGNAL ;
    SHAPE ABUTMENT ;
    PORT
      LAYER M2 ;
      RECT 139.599 385.560 139.617 385.830 ;
    END
  END r0_rd_out[498]
  PIN r0_rd_out[499]
    DIRECTION OUTPUT ;
    USE SIGNAL ;
    SHAPE ABUTMENT ;
    PORT
      LAYER M2 ;
      RECT 140.175 385.560 140.193 385.830 ;
    END
  END r0_rd_out[499]
  PIN r0_rd_out[500]
    DIRECTION OUTPUT ;
    USE SIGNAL ;
    SHAPE ABUTMENT ;
    PORT
      LAYER M2 ;
      RECT 140.751 385.560 140.769 385.830 ;
    END
  END r0_rd_out[500]
  PIN r0_rd_out[501]
    DIRECTION OUTPUT ;
    USE SIGNAL ;
    SHAPE ABUTMENT ;
    PORT
      LAYER M2 ;
      RECT 141.327 385.560 141.345 385.830 ;
    END
  END r0_rd_out[501]
  PIN r0_rd_out[502]
    DIRECTION OUTPUT ;
    USE SIGNAL ;
    SHAPE ABUTMENT ;
    PORT
      LAYER M2 ;
      RECT 141.903 385.560 141.921 385.830 ;
    END
  END r0_rd_out[502]
  PIN r0_rd_out[503]
    DIRECTION OUTPUT ;
    USE SIGNAL ;
    SHAPE ABUTMENT ;
    PORT
      LAYER M2 ;
      RECT 142.479 385.560 142.497 385.830 ;
    END
  END r0_rd_out[503]
  PIN r0_rd_out[504]
    DIRECTION OUTPUT ;
    USE SIGNAL ;
    SHAPE ABUTMENT ;
    PORT
      LAYER M2 ;
      RECT 143.055 385.560 143.073 385.830 ;
    END
  END r0_rd_out[504]
  PIN r0_rd_out[505]
    DIRECTION OUTPUT ;
    USE SIGNAL ;
    SHAPE ABUTMENT ;
    PORT
      LAYER M2 ;
      RECT 143.631 385.560 143.649 385.830 ;
    END
  END r0_rd_out[505]
  PIN r0_rd_out[506]
    DIRECTION OUTPUT ;
    USE SIGNAL ;
    SHAPE ABUTMENT ;
    PORT
      LAYER M2 ;
      RECT 144.207 385.560 144.225 385.830 ;
    END
  END r0_rd_out[506]
  PIN r0_rd_out[507]
    DIRECTION OUTPUT ;
    USE SIGNAL ;
    SHAPE ABUTMENT ;
    PORT
      LAYER M2 ;
      RECT 144.783 385.560 144.801 385.830 ;
    END
  END r0_rd_out[507]
  PIN r0_rd_out[508]
    DIRECTION OUTPUT ;
    USE SIGNAL ;
    SHAPE ABUTMENT ;
    PORT
      LAYER M2 ;
      RECT 145.359 385.560 145.377 385.830 ;
    END
  END r0_rd_out[508]
  PIN r0_rd_out[509]
    DIRECTION OUTPUT ;
    USE SIGNAL ;
    SHAPE ABUTMENT ;
    PORT
      LAYER M2 ;
      RECT 145.935 385.560 145.953 385.830 ;
    END
  END r0_rd_out[509]
  PIN r0_rd_out[510]
    DIRECTION OUTPUT ;
    USE SIGNAL ;
    SHAPE ABUTMENT ;
    PORT
      LAYER M2 ;
      RECT 146.511 385.560 146.529 385.830 ;
    END
  END r0_rd_out[510]
  PIN r0_rd_out[511]
    DIRECTION OUTPUT ;
    USE SIGNAL ;
    SHAPE ABUTMENT ;
    PORT
      LAYER M2 ;
      RECT 147.087 385.560 147.105 385.830 ;
    END
  END r0_rd_out[511]
  PIN w0_addr_in[0]
    DIRECTION INPUT ;
    USE SIGNAL ;
    SHAPE ABUTMENT ;
    PORT
      LAYER M3 ;
      RECT 0.000 350.484 0.072 350.508 ;
    END
  END w0_addr_in[0]
  PIN w0_addr_in[1]
    DIRECTION INPUT ;
    USE SIGNAL ;
    SHAPE ABUTMENT ;
    PORT
      LAYER M3 ;
      RECT 0.000 353.220 0.072 353.244 ;
    END
  END w0_addr_in[1]
  PIN w0_addr_in[2]
    DIRECTION INPUT ;
    USE SIGNAL ;
    SHAPE ABUTMENT ;
    PORT
      LAYER M3 ;
      RECT 0.000 355.956 0.072 355.980 ;
    END
  END w0_addr_in[2]
  PIN w0_addr_in[3]
    DIRECTION INPUT ;
    USE SIGNAL ;
    SHAPE ABUTMENT ;
    PORT
      LAYER M3 ;
      RECT 0.000 358.692 0.072 358.716 ;
    END
  END w0_addr_in[3]
  PIN w0_addr_in[4]
    DIRECTION INPUT ;
    USE SIGNAL ;
    SHAPE ABUTMENT ;
    PORT
      LAYER M3 ;
      RECT 0.000 361.428 0.072 361.452 ;
    END
  END w0_addr_in[4]
  PIN w0_addr_in[5]
    DIRECTION INPUT ;
    USE SIGNAL ;
    SHAPE ABUTMENT ;
    PORT
      LAYER M3 ;
      RECT 0.000 364.164 0.072 364.188 ;
    END
  END w0_addr_in[5]
  PIN w0_addr_in[6]
    DIRECTION INPUT ;
    USE SIGNAL ;
    SHAPE ABUTMENT ;
    PORT
      LAYER M3 ;
      RECT 154.224 350.484 154.296 350.508 ;
    END
  END w0_addr_in[6]
  PIN w0_addr_in[7]
    DIRECTION INPUT ;
    USE SIGNAL ;
    SHAPE ABUTMENT ;
    PORT
      LAYER M3 ;
      RECT 154.224 353.220 154.296 353.244 ;
    END
  END w0_addr_in[7]
  PIN w0_addr_in[8]
    DIRECTION INPUT ;
    USE SIGNAL ;
    SHAPE ABUTMENT ;
    PORT
      LAYER M3 ;
      RECT 154.224 355.956 154.296 355.980 ;
    END
  END w0_addr_in[8]
  PIN w0_addr_in[9]
    DIRECTION INPUT ;
    USE SIGNAL ;
    SHAPE ABUTMENT ;
    PORT
      LAYER M3 ;
      RECT 154.224 358.692 154.296 358.716 ;
    END
  END w0_addr_in[9]
  PIN w0_addr_in[10]
    DIRECTION INPUT ;
    USE SIGNAL ;
    SHAPE ABUTMENT ;
    PORT
      LAYER M3 ;
      RECT 154.224 361.428 154.296 361.452 ;
    END
  END w0_addr_in[10]
  PIN r0_addr_in[0]
    DIRECTION INPUT ;
    USE SIGNAL ;
    SHAPE ABUTMENT ;
    PORT
      LAYER M3 ;
      RECT 0.000 366.900 0.072 366.924 ;
    END
  END r0_addr_in[0]
  PIN r0_addr_in[1]
    DIRECTION INPUT ;
    USE SIGNAL ;
    SHAPE ABUTMENT ;
    PORT
      LAYER M3 ;
      RECT 0.000 369.636 0.072 369.660 ;
    END
  END r0_addr_in[1]
  PIN r0_addr_in[2]
    DIRECTION INPUT ;
    USE SIGNAL ;
    SHAPE ABUTMENT ;
    PORT
      LAYER M3 ;
      RECT 0.000 372.372 0.072 372.396 ;
    END
  END r0_addr_in[2]
  PIN r0_addr_in[3]
    DIRECTION INPUT ;
    USE SIGNAL ;
    SHAPE ABUTMENT ;
    PORT
      LAYER M3 ;
      RECT 0.000 375.108 0.072 375.132 ;
    END
  END r0_addr_in[3]
  PIN r0_addr_in[4]
    DIRECTION INPUT ;
    USE SIGNAL ;
    SHAPE ABUTMENT ;
    PORT
      LAYER M3 ;
      RECT 0.000 377.844 0.072 377.868 ;
    END
  END r0_addr_in[4]
  PIN r0_addr_in[5]
    DIRECTION INPUT ;
    USE SIGNAL ;
    SHAPE ABUTMENT ;
    PORT
      LAYER M3 ;
      RECT 0.000 380.580 0.072 380.604 ;
    END
  END r0_addr_in[5]
  PIN r0_addr_in[6]
    DIRECTION INPUT ;
    USE SIGNAL ;
    SHAPE ABUTMENT ;
    PORT
      LAYER M3 ;
      RECT 154.224 364.164 154.296 364.188 ;
    END
  END r0_addr_in[6]
  PIN r0_addr_in[7]
    DIRECTION INPUT ;
    USE SIGNAL ;
    SHAPE ABUTMENT ;
    PORT
      LAYER M3 ;
      RECT 154.224 366.900 154.296 366.924 ;
    END
  END r0_addr_in[7]
  PIN r0_addr_in[8]
    DIRECTION INPUT ;
    USE SIGNAL ;
    SHAPE ABUTMENT ;
    PORT
      LAYER M3 ;
      RECT 154.224 369.636 154.296 369.660 ;
    END
  END r0_addr_in[8]
  PIN r0_addr_in[9]
    DIRECTION INPUT ;
    USE SIGNAL ;
    SHAPE ABUTMENT ;
    PORT
      LAYER M3 ;
      RECT 154.224 372.372 154.296 372.396 ;
    END
  END r0_addr_in[9]
  PIN r0_addr_in[10]
    DIRECTION INPUT ;
    USE SIGNAL ;
    SHAPE ABUTMENT ;
    PORT
      LAYER M3 ;
      RECT 154.224 375.108 154.296 375.132 ;
    END
  END r0_addr_in[10]
  PIN w0_we_in
    DIRECTION INPUT ;
    USE SIGNAL ;
    SHAPE ABUTMENT ;
    PORT
      LAYER M2 ;
      RECT 147.663 385.560 147.681 385.830 ;
    END
  END w0_we_in
  PIN w0_ce_in
    DIRECTION INPUT ;
    USE SIGNAL ;
    SHAPE ABUTMENT ;
    PORT
      LAYER M2 ;
      RECT 148.239 385.560 148.257 385.830 ;
    END
  END w0_ce_in
  PIN w0_clk
    DIRECTION INPUT ;
    USE SIGNAL ;
    SHAPE ABUTMENT ;
    PORT
      LAYER M2 ;
      RECT 148.815 385.560 148.833 385.830 ;
    END
  END w0_clk
  PIN r0_ce_in
    DIRECTION INPUT ;
    USE SIGNAL ;
    SHAPE ABUTMENT ;
    PORT
      LAYER M2 ;
      RECT 149.391 385.560 149.409 385.830 ;
    END
  END r0_ce_in
  PIN r0_clk
    DIRECTION INPUT ;
    USE SIGNAL ;
    SHAPE ABUTMENT ;
    PORT
      LAYER M2 ;
      RECT 149.967 385.560 149.985 385.830 ;
    END
  END r0_clk
  PIN VSS
    DIRECTION INOUT ;
    USE GROUND ;
    PORT
      LAYER M4 ;
      RECT 0.216 0.228 154.080 0.348 ;
      RECT 0.216 0.996 154.080 1.116 ;
      RECT 0.216 1.764 154.080 1.884 ;
      RECT 0.216 2.532 154.080 2.652 ;
      RECT 0.216 3.300 154.080 3.420 ;
      RECT 0.216 4.068 154.080 4.188 ;
      RECT 0.216 4.836 154.080 4.956 ;
      RECT 0.216 5.604 154.080 5.724 ;
      RECT 0.216 6.372 154.080 6.492 ;
      RECT 0.216 7.140 154.080 7.260 ;
      RECT 0.216 7.908 154.080 8.028 ;
      RECT 0.216 8.676 154.080 8.796 ;
      RECT 0.216 9.444 154.080 9.564 ;
      RECT 0.216 10.212 154.080 10.332 ;
      RECT 0.216 10.980 154.080 11.100 ;
      RECT 0.216 11.748 154.080 11.868 ;
      RECT 0.216 12.516 154.080 12.636 ;
      RECT 0.216 13.284 154.080 13.404 ;
      RECT 0.216 14.052 154.080 14.172 ;
      RECT 0.216 14.820 154.080 14.940 ;
      RECT 0.216 15.588 154.080 15.708 ;
      RECT 0.216 16.356 154.080 16.476 ;
      RECT 0.216 17.124 154.080 17.244 ;
      RECT 0.216 17.892 154.080 18.012 ;
      RECT 0.216 18.660 154.080 18.780 ;
      RECT 0.216 19.428 154.080 19.548 ;
      RECT 0.216 20.196 154.080 20.316 ;
      RECT 0.216 20.964 154.080 21.084 ;
      RECT 0.216 21.732 154.080 21.852 ;
      RECT 0.216 22.500 154.080 22.620 ;
      RECT 0.216 23.268 154.080 23.388 ;
      RECT 0.216 24.036 154.080 24.156 ;
      RECT 0.216 24.804 154.080 24.924 ;
      RECT 0.216 25.572 154.080 25.692 ;
      RECT 0.216 26.340 154.080 26.460 ;
      RECT 0.216 27.108 154.080 27.228 ;
      RECT 0.216 27.876 154.080 27.996 ;
      RECT 0.216 28.644 154.080 28.764 ;
      RECT 0.216 29.412 154.080 29.532 ;
      RECT 0.216 30.180 154.080 30.300 ;
      RECT 0.216 30.948 154.080 31.068 ;
      RECT 0.216 31.716 154.080 31.836 ;
      RECT 0.216 32.484 154.080 32.604 ;
      RECT 0.216 33.252 154.080 33.372 ;
      RECT 0.216 34.020 154.080 34.140 ;
      RECT 0.216 34.788 154.080 34.908 ;
      RECT 0.216 35.556 154.080 35.676 ;
      RECT 0.216 36.324 154.080 36.444 ;
      RECT 0.216 37.092 154.080 37.212 ;
      RECT 0.216 37.860 154.080 37.980 ;
      RECT 0.216 38.628 154.080 38.748 ;
      RECT 0.216 39.396 154.080 39.516 ;
      RECT 0.216 40.164 154.080 40.284 ;
      RECT 0.216 40.932 154.080 41.052 ;
      RECT 0.216 41.700 154.080 41.820 ;
      RECT 0.216 42.468 154.080 42.588 ;
      RECT 0.216 43.236 154.080 43.356 ;
      RECT 0.216 44.004 154.080 44.124 ;
      RECT 0.216 44.772 154.080 44.892 ;
      RECT 0.216 45.540 154.080 45.660 ;
      RECT 0.216 46.308 154.080 46.428 ;
      RECT 0.216 47.076 154.080 47.196 ;
      RECT 0.216 47.844 154.080 47.964 ;
      RECT 0.216 48.612 154.080 48.732 ;
      RECT 0.216 49.380 154.080 49.500 ;
      RECT 0.216 50.148 154.080 50.268 ;
      RECT 0.216 50.916 154.080 51.036 ;
      RECT 0.216 51.684 154.080 51.804 ;
      RECT 0.216 52.452 154.080 52.572 ;
      RECT 0.216 53.220 154.080 53.340 ;
      RECT 0.216 53.988 154.080 54.108 ;
      RECT 0.216 54.756 154.080 54.876 ;
      RECT 0.216 55.524 154.080 55.644 ;
      RECT 0.216 56.292 154.080 56.412 ;
      RECT 0.216 57.060 154.080 57.180 ;
      RECT 0.216 57.828 154.080 57.948 ;
      RECT 0.216 58.596 154.080 58.716 ;
      RECT 0.216 59.364 154.080 59.484 ;
      RECT 0.216 60.132 154.080 60.252 ;
      RECT 0.216 60.900 154.080 61.020 ;
      RECT 0.216 61.668 154.080 61.788 ;
      RECT 0.216 62.436 154.080 62.556 ;
      RECT 0.216 63.204 154.080 63.324 ;
      RECT 0.216 63.972 154.080 64.092 ;
      RECT 0.216 64.740 154.080 64.860 ;
      RECT 0.216 65.508 154.080 65.628 ;
      RECT 0.216 66.276 154.080 66.396 ;
      RECT 0.216 67.044 154.080 67.164 ;
      RECT 0.216 67.812 154.080 67.932 ;
      RECT 0.216 68.580 154.080 68.700 ;
      RECT 0.216 69.348 154.080 69.468 ;
      RECT 0.216 70.116 154.080 70.236 ;
      RECT 0.216 70.884 154.080 71.004 ;
      RECT 0.216 71.652 154.080 71.772 ;
      RECT 0.216 72.420 154.080 72.540 ;
      RECT 0.216 73.188 154.080 73.308 ;
      RECT 0.216 73.956 154.080 74.076 ;
      RECT 0.216 74.724 154.080 74.844 ;
      RECT 0.216 75.492 154.080 75.612 ;
      RECT 0.216 76.260 154.080 76.380 ;
      RECT 0.216 77.028 154.080 77.148 ;
      RECT 0.216 77.796 154.080 77.916 ;
      RECT 0.216 78.564 154.080 78.684 ;
      RECT 0.216 79.332 154.080 79.452 ;
      RECT 0.216 80.100 154.080 80.220 ;
      RECT 0.216 80.868 154.080 80.988 ;
      RECT 0.216 81.636 154.080 81.756 ;
      RECT 0.216 82.404 154.080 82.524 ;
      RECT 0.216 83.172 154.080 83.292 ;
      RECT 0.216 83.940 154.080 84.060 ;
      RECT 0.216 84.708 154.080 84.828 ;
      RECT 0.216 85.476 154.080 85.596 ;
      RECT 0.216 86.244 154.080 86.364 ;
      RECT 0.216 87.012 154.080 87.132 ;
      RECT 0.216 87.780 154.080 87.900 ;
      RECT 0.216 88.548 154.080 88.668 ;
      RECT 0.216 89.316 154.080 89.436 ;
      RECT 0.216 90.084 154.080 90.204 ;
      RECT 0.216 90.852 154.080 90.972 ;
      RECT 0.216 91.620 154.080 91.740 ;
      RECT 0.216 92.388 154.080 92.508 ;
      RECT 0.216 93.156 154.080 93.276 ;
      RECT 0.216 93.924 154.080 94.044 ;
      RECT 0.216 94.692 154.080 94.812 ;
      RECT 0.216 95.460 154.080 95.580 ;
      RECT 0.216 96.228 154.080 96.348 ;
      RECT 0.216 96.996 154.080 97.116 ;
      RECT 0.216 97.764 154.080 97.884 ;
      RECT 0.216 98.532 154.080 98.652 ;
      RECT 0.216 99.300 154.080 99.420 ;
      RECT 0.216 100.068 154.080 100.188 ;
      RECT 0.216 100.836 154.080 100.956 ;
      RECT 0.216 101.604 154.080 101.724 ;
      RECT 0.216 102.372 154.080 102.492 ;
      RECT 0.216 103.140 154.080 103.260 ;
      RECT 0.216 103.908 154.080 104.028 ;
      RECT 0.216 104.676 154.080 104.796 ;
      RECT 0.216 105.444 154.080 105.564 ;
      RECT 0.216 106.212 154.080 106.332 ;
      RECT 0.216 106.980 154.080 107.100 ;
      RECT 0.216 107.748 154.080 107.868 ;
      RECT 0.216 108.516 154.080 108.636 ;
      RECT 0.216 109.284 154.080 109.404 ;
      RECT 0.216 110.052 154.080 110.172 ;
      RECT 0.216 110.820 154.080 110.940 ;
      RECT 0.216 111.588 154.080 111.708 ;
      RECT 0.216 112.356 154.080 112.476 ;
      RECT 0.216 113.124 154.080 113.244 ;
      RECT 0.216 113.892 154.080 114.012 ;
      RECT 0.216 114.660 154.080 114.780 ;
      RECT 0.216 115.428 154.080 115.548 ;
      RECT 0.216 116.196 154.080 116.316 ;
      RECT 0.216 116.964 154.080 117.084 ;
      RECT 0.216 117.732 154.080 117.852 ;
      RECT 0.216 118.500 154.080 118.620 ;
      RECT 0.216 119.268 154.080 119.388 ;
      RECT 0.216 120.036 154.080 120.156 ;
      RECT 0.216 120.804 154.080 120.924 ;
      RECT 0.216 121.572 154.080 121.692 ;
      RECT 0.216 122.340 154.080 122.460 ;
      RECT 0.216 123.108 154.080 123.228 ;
      RECT 0.216 123.876 154.080 123.996 ;
      RECT 0.216 124.644 154.080 124.764 ;
      RECT 0.216 125.412 154.080 125.532 ;
      RECT 0.216 126.180 154.080 126.300 ;
      RECT 0.216 126.948 154.080 127.068 ;
      RECT 0.216 127.716 154.080 127.836 ;
      RECT 0.216 128.484 154.080 128.604 ;
      RECT 0.216 129.252 154.080 129.372 ;
      RECT 0.216 130.020 154.080 130.140 ;
      RECT 0.216 130.788 154.080 130.908 ;
      RECT 0.216 131.556 154.080 131.676 ;
      RECT 0.216 132.324 154.080 132.444 ;
      RECT 0.216 133.092 154.080 133.212 ;
      RECT 0.216 133.860 154.080 133.980 ;
      RECT 0.216 134.628 154.080 134.748 ;
      RECT 0.216 135.396 154.080 135.516 ;
      RECT 0.216 136.164 154.080 136.284 ;
      RECT 0.216 136.932 154.080 137.052 ;
      RECT 0.216 137.700 154.080 137.820 ;
      RECT 0.216 138.468 154.080 138.588 ;
      RECT 0.216 139.236 154.080 139.356 ;
      RECT 0.216 140.004 154.080 140.124 ;
      RECT 0.216 140.772 154.080 140.892 ;
      RECT 0.216 141.540 154.080 141.660 ;
      RECT 0.216 142.308 154.080 142.428 ;
      RECT 0.216 143.076 154.080 143.196 ;
      RECT 0.216 143.844 154.080 143.964 ;
      RECT 0.216 144.612 154.080 144.732 ;
      RECT 0.216 145.380 154.080 145.500 ;
      RECT 0.216 146.148 154.080 146.268 ;
      RECT 0.216 146.916 154.080 147.036 ;
      RECT 0.216 147.684 154.080 147.804 ;
      RECT 0.216 148.452 154.080 148.572 ;
      RECT 0.216 149.220 154.080 149.340 ;
      RECT 0.216 149.988 154.080 150.108 ;
      RECT 0.216 150.756 154.080 150.876 ;
      RECT 0.216 151.524 154.080 151.644 ;
      RECT 0.216 152.292 154.080 152.412 ;
      RECT 0.216 153.060 154.080 153.180 ;
      RECT 0.216 153.828 154.080 153.948 ;
      RECT 0.216 154.596 154.080 154.716 ;
      RECT 0.216 155.364 154.080 155.484 ;
      RECT 0.216 156.132 154.080 156.252 ;
      RECT 0.216 156.900 154.080 157.020 ;
      RECT 0.216 157.668 154.080 157.788 ;
      RECT 0.216 158.436 154.080 158.556 ;
      RECT 0.216 159.204 154.080 159.324 ;
      RECT 0.216 159.972 154.080 160.092 ;
      RECT 0.216 160.740 154.080 160.860 ;
      RECT 0.216 161.508 154.080 161.628 ;
      RECT 0.216 162.276 154.080 162.396 ;
      RECT 0.216 163.044 154.080 163.164 ;
      RECT 0.216 163.812 154.080 163.932 ;
      RECT 0.216 164.580 154.080 164.700 ;
      RECT 0.216 165.348 154.080 165.468 ;
      RECT 0.216 166.116 154.080 166.236 ;
      RECT 0.216 166.884 154.080 167.004 ;
      RECT 0.216 167.652 154.080 167.772 ;
      RECT 0.216 168.420 154.080 168.540 ;
      RECT 0.216 169.188 154.080 169.308 ;
      RECT 0.216 169.956 154.080 170.076 ;
      RECT 0.216 170.724 154.080 170.844 ;
      RECT 0.216 171.492 154.080 171.612 ;
      RECT 0.216 172.260 154.080 172.380 ;
      RECT 0.216 173.028 154.080 173.148 ;
      RECT 0.216 173.796 154.080 173.916 ;
      RECT 0.216 174.564 154.080 174.684 ;
      RECT 0.216 175.332 154.080 175.452 ;
      RECT 0.216 176.100 154.080 176.220 ;
      RECT 0.216 176.868 154.080 176.988 ;
      RECT 0.216 177.636 154.080 177.756 ;
      RECT 0.216 178.404 154.080 178.524 ;
      RECT 0.216 179.172 154.080 179.292 ;
      RECT 0.216 179.940 154.080 180.060 ;
      RECT 0.216 180.708 154.080 180.828 ;
      RECT 0.216 181.476 154.080 181.596 ;
      RECT 0.216 182.244 154.080 182.364 ;
      RECT 0.216 183.012 154.080 183.132 ;
      RECT 0.216 183.780 154.080 183.900 ;
      RECT 0.216 184.548 154.080 184.668 ;
      RECT 0.216 185.316 154.080 185.436 ;
      RECT 0.216 186.084 154.080 186.204 ;
      RECT 0.216 186.852 154.080 186.972 ;
      RECT 0.216 187.620 154.080 187.740 ;
      RECT 0.216 188.388 154.080 188.508 ;
      RECT 0.216 189.156 154.080 189.276 ;
      RECT 0.216 189.924 154.080 190.044 ;
      RECT 0.216 190.692 154.080 190.812 ;
      RECT 0.216 191.460 154.080 191.580 ;
      RECT 0.216 192.228 154.080 192.348 ;
      RECT 0.216 192.996 154.080 193.116 ;
      RECT 0.216 193.764 154.080 193.884 ;
      RECT 0.216 194.532 154.080 194.652 ;
      RECT 0.216 195.300 154.080 195.420 ;
      RECT 0.216 196.068 154.080 196.188 ;
      RECT 0.216 196.836 154.080 196.956 ;
      RECT 0.216 197.604 154.080 197.724 ;
      RECT 0.216 198.372 154.080 198.492 ;
      RECT 0.216 199.140 154.080 199.260 ;
      RECT 0.216 199.908 154.080 200.028 ;
      RECT 0.216 200.676 154.080 200.796 ;
      RECT 0.216 201.444 154.080 201.564 ;
      RECT 0.216 202.212 154.080 202.332 ;
      RECT 0.216 202.980 154.080 203.100 ;
      RECT 0.216 203.748 154.080 203.868 ;
      RECT 0.216 204.516 154.080 204.636 ;
      RECT 0.216 205.284 154.080 205.404 ;
      RECT 0.216 206.052 154.080 206.172 ;
      RECT 0.216 206.820 154.080 206.940 ;
      RECT 0.216 207.588 154.080 207.708 ;
      RECT 0.216 208.356 154.080 208.476 ;
      RECT 0.216 209.124 154.080 209.244 ;
      RECT 0.216 209.892 154.080 210.012 ;
      RECT 0.216 210.660 154.080 210.780 ;
      RECT 0.216 211.428 154.080 211.548 ;
      RECT 0.216 212.196 154.080 212.316 ;
      RECT 0.216 212.964 154.080 213.084 ;
      RECT 0.216 213.732 154.080 213.852 ;
      RECT 0.216 214.500 154.080 214.620 ;
      RECT 0.216 215.268 154.080 215.388 ;
      RECT 0.216 216.036 154.080 216.156 ;
      RECT 0.216 216.804 154.080 216.924 ;
      RECT 0.216 217.572 154.080 217.692 ;
      RECT 0.216 218.340 154.080 218.460 ;
      RECT 0.216 219.108 154.080 219.228 ;
      RECT 0.216 219.876 154.080 219.996 ;
      RECT 0.216 220.644 154.080 220.764 ;
      RECT 0.216 221.412 154.080 221.532 ;
      RECT 0.216 222.180 154.080 222.300 ;
      RECT 0.216 222.948 154.080 223.068 ;
      RECT 0.216 223.716 154.080 223.836 ;
      RECT 0.216 224.484 154.080 224.604 ;
      RECT 0.216 225.252 154.080 225.372 ;
      RECT 0.216 226.020 154.080 226.140 ;
      RECT 0.216 226.788 154.080 226.908 ;
      RECT 0.216 227.556 154.080 227.676 ;
      RECT 0.216 228.324 154.080 228.444 ;
      RECT 0.216 229.092 154.080 229.212 ;
      RECT 0.216 229.860 154.080 229.980 ;
      RECT 0.216 230.628 154.080 230.748 ;
      RECT 0.216 231.396 154.080 231.516 ;
      RECT 0.216 232.164 154.080 232.284 ;
      RECT 0.216 232.932 154.080 233.052 ;
      RECT 0.216 233.700 154.080 233.820 ;
      RECT 0.216 234.468 154.080 234.588 ;
      RECT 0.216 235.236 154.080 235.356 ;
      RECT 0.216 236.004 154.080 236.124 ;
      RECT 0.216 236.772 154.080 236.892 ;
      RECT 0.216 237.540 154.080 237.660 ;
      RECT 0.216 238.308 154.080 238.428 ;
      RECT 0.216 239.076 154.080 239.196 ;
      RECT 0.216 239.844 154.080 239.964 ;
      RECT 0.216 240.612 154.080 240.732 ;
      RECT 0.216 241.380 154.080 241.500 ;
      RECT 0.216 242.148 154.080 242.268 ;
      RECT 0.216 242.916 154.080 243.036 ;
      RECT 0.216 243.684 154.080 243.804 ;
      RECT 0.216 244.452 154.080 244.572 ;
      RECT 0.216 245.220 154.080 245.340 ;
      RECT 0.216 245.988 154.080 246.108 ;
      RECT 0.216 246.756 154.080 246.876 ;
      RECT 0.216 247.524 154.080 247.644 ;
      RECT 0.216 248.292 154.080 248.412 ;
      RECT 0.216 249.060 154.080 249.180 ;
      RECT 0.216 249.828 154.080 249.948 ;
      RECT 0.216 250.596 154.080 250.716 ;
      RECT 0.216 251.364 154.080 251.484 ;
      RECT 0.216 252.132 154.080 252.252 ;
      RECT 0.216 252.900 154.080 253.020 ;
      RECT 0.216 253.668 154.080 253.788 ;
      RECT 0.216 254.436 154.080 254.556 ;
      RECT 0.216 255.204 154.080 255.324 ;
      RECT 0.216 255.972 154.080 256.092 ;
      RECT 0.216 256.740 154.080 256.860 ;
      RECT 0.216 257.508 154.080 257.628 ;
      RECT 0.216 258.276 154.080 258.396 ;
      RECT 0.216 259.044 154.080 259.164 ;
      RECT 0.216 259.812 154.080 259.932 ;
      RECT 0.216 260.580 154.080 260.700 ;
      RECT 0.216 261.348 154.080 261.468 ;
      RECT 0.216 262.116 154.080 262.236 ;
      RECT 0.216 262.884 154.080 263.004 ;
      RECT 0.216 263.652 154.080 263.772 ;
      RECT 0.216 264.420 154.080 264.540 ;
      RECT 0.216 265.188 154.080 265.308 ;
      RECT 0.216 265.956 154.080 266.076 ;
      RECT 0.216 266.724 154.080 266.844 ;
      RECT 0.216 267.492 154.080 267.612 ;
      RECT 0.216 268.260 154.080 268.380 ;
      RECT 0.216 269.028 154.080 269.148 ;
      RECT 0.216 269.796 154.080 269.916 ;
      RECT 0.216 270.564 154.080 270.684 ;
      RECT 0.216 271.332 154.080 271.452 ;
      RECT 0.216 272.100 154.080 272.220 ;
      RECT 0.216 272.868 154.080 272.988 ;
      RECT 0.216 273.636 154.080 273.756 ;
      RECT 0.216 274.404 154.080 274.524 ;
      RECT 0.216 275.172 154.080 275.292 ;
      RECT 0.216 275.940 154.080 276.060 ;
      RECT 0.216 276.708 154.080 276.828 ;
      RECT 0.216 277.476 154.080 277.596 ;
      RECT 0.216 278.244 154.080 278.364 ;
      RECT 0.216 279.012 154.080 279.132 ;
      RECT 0.216 279.780 154.080 279.900 ;
      RECT 0.216 280.548 154.080 280.668 ;
      RECT 0.216 281.316 154.080 281.436 ;
      RECT 0.216 282.084 154.080 282.204 ;
      RECT 0.216 282.852 154.080 282.972 ;
      RECT 0.216 283.620 154.080 283.740 ;
      RECT 0.216 284.388 154.080 284.508 ;
      RECT 0.216 285.156 154.080 285.276 ;
      RECT 0.216 285.924 154.080 286.044 ;
      RECT 0.216 286.692 154.080 286.812 ;
      RECT 0.216 287.460 154.080 287.580 ;
      RECT 0.216 288.228 154.080 288.348 ;
      RECT 0.216 288.996 154.080 289.116 ;
      RECT 0.216 289.764 154.080 289.884 ;
      RECT 0.216 290.532 154.080 290.652 ;
      RECT 0.216 291.300 154.080 291.420 ;
      RECT 0.216 292.068 154.080 292.188 ;
      RECT 0.216 292.836 154.080 292.956 ;
      RECT 0.216 293.604 154.080 293.724 ;
      RECT 0.216 294.372 154.080 294.492 ;
      RECT 0.216 295.140 154.080 295.260 ;
      RECT 0.216 295.908 154.080 296.028 ;
      RECT 0.216 296.676 154.080 296.796 ;
      RECT 0.216 297.444 154.080 297.564 ;
      RECT 0.216 298.212 154.080 298.332 ;
      RECT 0.216 298.980 154.080 299.100 ;
      RECT 0.216 299.748 154.080 299.868 ;
      RECT 0.216 300.516 154.080 300.636 ;
      RECT 0.216 301.284 154.080 301.404 ;
      RECT 0.216 302.052 154.080 302.172 ;
      RECT 0.216 302.820 154.080 302.940 ;
      RECT 0.216 303.588 154.080 303.708 ;
      RECT 0.216 304.356 154.080 304.476 ;
      RECT 0.216 305.124 154.080 305.244 ;
      RECT 0.216 305.892 154.080 306.012 ;
      RECT 0.216 306.660 154.080 306.780 ;
      RECT 0.216 307.428 154.080 307.548 ;
      RECT 0.216 308.196 154.080 308.316 ;
      RECT 0.216 308.964 154.080 309.084 ;
      RECT 0.216 309.732 154.080 309.852 ;
      RECT 0.216 310.500 154.080 310.620 ;
      RECT 0.216 311.268 154.080 311.388 ;
      RECT 0.216 312.036 154.080 312.156 ;
      RECT 0.216 312.804 154.080 312.924 ;
      RECT 0.216 313.572 154.080 313.692 ;
      RECT 0.216 314.340 154.080 314.460 ;
      RECT 0.216 315.108 154.080 315.228 ;
      RECT 0.216 315.876 154.080 315.996 ;
      RECT 0.216 316.644 154.080 316.764 ;
      RECT 0.216 317.412 154.080 317.532 ;
      RECT 0.216 318.180 154.080 318.300 ;
      RECT 0.216 318.948 154.080 319.068 ;
      RECT 0.216 319.716 154.080 319.836 ;
      RECT 0.216 320.484 154.080 320.604 ;
      RECT 0.216 321.252 154.080 321.372 ;
      RECT 0.216 322.020 154.080 322.140 ;
      RECT 0.216 322.788 154.080 322.908 ;
      RECT 0.216 323.556 154.080 323.676 ;
      RECT 0.216 324.324 154.080 324.444 ;
      RECT 0.216 325.092 154.080 325.212 ;
      RECT 0.216 325.860 154.080 325.980 ;
      RECT 0.216 326.628 154.080 326.748 ;
      RECT 0.216 327.396 154.080 327.516 ;
      RECT 0.216 328.164 154.080 328.284 ;
      RECT 0.216 328.932 154.080 329.052 ;
      RECT 0.216 329.700 154.080 329.820 ;
      RECT 0.216 330.468 154.080 330.588 ;
      RECT 0.216 331.236 154.080 331.356 ;
      RECT 0.216 332.004 154.080 332.124 ;
      RECT 0.216 332.772 154.080 332.892 ;
      RECT 0.216 333.540 154.080 333.660 ;
      RECT 0.216 334.308 154.080 334.428 ;
      RECT 0.216 335.076 154.080 335.196 ;
      RECT 0.216 335.844 154.080 335.964 ;
      RECT 0.216 336.612 154.080 336.732 ;
      RECT 0.216 337.380 154.080 337.500 ;
      RECT 0.216 338.148 154.080 338.268 ;
      RECT 0.216 338.916 154.080 339.036 ;
      RECT 0.216 339.684 154.080 339.804 ;
      RECT 0.216 340.452 154.080 340.572 ;
      RECT 0.216 341.220 154.080 341.340 ;
      RECT 0.216 341.988 154.080 342.108 ;
      RECT 0.216 342.756 154.080 342.876 ;
      RECT 0.216 343.524 154.080 343.644 ;
      RECT 0.216 344.292 154.080 344.412 ;
      RECT 0.216 345.060 154.080 345.180 ;
      RECT 0.216 345.828 154.080 345.948 ;
      RECT 0.216 346.596 154.080 346.716 ;
      RECT 0.216 347.364 154.080 347.484 ;
      RECT 0.216 348.132 154.080 348.252 ;
      RECT 0.216 348.900 154.080 349.020 ;
      RECT 0.216 349.668 154.080 349.788 ;
      RECT 0.216 350.436 154.080 350.556 ;
      RECT 0.216 351.204 154.080 351.324 ;
      RECT 0.216 351.972 154.080 352.092 ;
      RECT 0.216 352.740 154.080 352.860 ;
      RECT 0.216 353.508 154.080 353.628 ;
      RECT 0.216 354.276 154.080 354.396 ;
      RECT 0.216 355.044 154.080 355.164 ;
      RECT 0.216 355.812 154.080 355.932 ;
      RECT 0.216 356.580 154.080 356.700 ;
      RECT 0.216 357.348 154.080 357.468 ;
      RECT 0.216 358.116 154.080 358.236 ;
      RECT 0.216 358.884 154.080 359.004 ;
      RECT 0.216 359.652 154.080 359.772 ;
      RECT 0.216 360.420 154.080 360.540 ;
      RECT 0.216 361.188 154.080 361.308 ;
      RECT 0.216 361.956 154.080 362.076 ;
      RECT 0.216 362.724 154.080 362.844 ;
      RECT 0.216 363.492 154.080 363.612 ;
      RECT 0.216 364.260 154.080 364.380 ;
      RECT 0.216 365.028 154.080 365.148 ;
      RECT 0.216 365.796 154.080 365.916 ;
      RECT 0.216 366.564 154.080 366.684 ;
      RECT 0.216 367.332 154.080 367.452 ;
      RECT 0.216 368.100 154.080 368.220 ;
      RECT 0.216 368.868 154.080 368.988 ;
      RECT 0.216 369.636 154.080 369.756 ;
      RECT 0.216 370.404 154.080 370.524 ;
      RECT 0.216 371.172 154.080 371.292 ;
      RECT 0.216 371.940 154.080 372.060 ;
      RECT 0.216 372.708 154.080 372.828 ;
      RECT 0.216 373.476 154.080 373.596 ;
      RECT 0.216 374.244 154.080 374.364 ;
      RECT 0.216 375.012 154.080 375.132 ;
      RECT 0.216 375.780 154.080 375.900 ;
      RECT 0.216 376.548 154.080 376.668 ;
      RECT 0.216 377.316 154.080 377.436 ;
      RECT 0.216 378.084 154.080 378.204 ;
      RECT 0.216 378.852 154.080 378.972 ;
      RECT 0.216 379.620 154.080 379.740 ;
      RECT 0.216 380.388 154.080 380.508 ;
      RECT 0.216 381.156 154.080 381.276 ;
      RECT 0.216 381.924 154.080 382.044 ;
      RECT 0.216 382.692 154.080 382.812 ;
      RECT 0.216 383.460 154.080 383.580 ;
      RECT 0.216 384.228 154.080 384.348 ;
      RECT 0.216 384.996 154.080 385.116 ;
    END
  END VSS
  PIN VDD
    DIRECTION INOUT ;
    USE POWER ;
    PORT
      LAYER M4 ;
      RECT 0.216 0.612 154.080 0.732 ;
      RECT 0.216 1.380 154.080 1.500 ;
      RECT 0.216 2.148 154.080 2.268 ;
      RECT 0.216 2.916 154.080 3.036 ;
      RECT 0.216 3.684 154.080 3.804 ;
      RECT 0.216 4.452 154.080 4.572 ;
      RECT 0.216 5.220 154.080 5.340 ;
      RECT 0.216 5.988 154.080 6.108 ;
      RECT 0.216 6.756 154.080 6.876 ;
      RECT 0.216 7.524 154.080 7.644 ;
      RECT 0.216 8.292 154.080 8.412 ;
      RECT 0.216 9.060 154.080 9.180 ;
      RECT 0.216 9.828 154.080 9.948 ;
      RECT 0.216 10.596 154.080 10.716 ;
      RECT 0.216 11.364 154.080 11.484 ;
      RECT 0.216 12.132 154.080 12.252 ;
      RECT 0.216 12.900 154.080 13.020 ;
      RECT 0.216 13.668 154.080 13.788 ;
      RECT 0.216 14.436 154.080 14.556 ;
      RECT 0.216 15.204 154.080 15.324 ;
      RECT 0.216 15.972 154.080 16.092 ;
      RECT 0.216 16.740 154.080 16.860 ;
      RECT 0.216 17.508 154.080 17.628 ;
      RECT 0.216 18.276 154.080 18.396 ;
      RECT 0.216 19.044 154.080 19.164 ;
      RECT 0.216 19.812 154.080 19.932 ;
      RECT 0.216 20.580 154.080 20.700 ;
      RECT 0.216 21.348 154.080 21.468 ;
      RECT 0.216 22.116 154.080 22.236 ;
      RECT 0.216 22.884 154.080 23.004 ;
      RECT 0.216 23.652 154.080 23.772 ;
      RECT 0.216 24.420 154.080 24.540 ;
      RECT 0.216 25.188 154.080 25.308 ;
      RECT 0.216 25.956 154.080 26.076 ;
      RECT 0.216 26.724 154.080 26.844 ;
      RECT 0.216 27.492 154.080 27.612 ;
      RECT 0.216 28.260 154.080 28.380 ;
      RECT 0.216 29.028 154.080 29.148 ;
      RECT 0.216 29.796 154.080 29.916 ;
      RECT 0.216 30.564 154.080 30.684 ;
      RECT 0.216 31.332 154.080 31.452 ;
      RECT 0.216 32.100 154.080 32.220 ;
      RECT 0.216 32.868 154.080 32.988 ;
      RECT 0.216 33.636 154.080 33.756 ;
      RECT 0.216 34.404 154.080 34.524 ;
      RECT 0.216 35.172 154.080 35.292 ;
      RECT 0.216 35.940 154.080 36.060 ;
      RECT 0.216 36.708 154.080 36.828 ;
      RECT 0.216 37.476 154.080 37.596 ;
      RECT 0.216 38.244 154.080 38.364 ;
      RECT 0.216 39.012 154.080 39.132 ;
      RECT 0.216 39.780 154.080 39.900 ;
      RECT 0.216 40.548 154.080 40.668 ;
      RECT 0.216 41.316 154.080 41.436 ;
      RECT 0.216 42.084 154.080 42.204 ;
      RECT 0.216 42.852 154.080 42.972 ;
      RECT 0.216 43.620 154.080 43.740 ;
      RECT 0.216 44.388 154.080 44.508 ;
      RECT 0.216 45.156 154.080 45.276 ;
      RECT 0.216 45.924 154.080 46.044 ;
      RECT 0.216 46.692 154.080 46.812 ;
      RECT 0.216 47.460 154.080 47.580 ;
      RECT 0.216 48.228 154.080 48.348 ;
      RECT 0.216 48.996 154.080 49.116 ;
      RECT 0.216 49.764 154.080 49.884 ;
      RECT 0.216 50.532 154.080 50.652 ;
      RECT 0.216 51.300 154.080 51.420 ;
      RECT 0.216 52.068 154.080 52.188 ;
      RECT 0.216 52.836 154.080 52.956 ;
      RECT 0.216 53.604 154.080 53.724 ;
      RECT 0.216 54.372 154.080 54.492 ;
      RECT 0.216 55.140 154.080 55.260 ;
      RECT 0.216 55.908 154.080 56.028 ;
      RECT 0.216 56.676 154.080 56.796 ;
      RECT 0.216 57.444 154.080 57.564 ;
      RECT 0.216 58.212 154.080 58.332 ;
      RECT 0.216 58.980 154.080 59.100 ;
      RECT 0.216 59.748 154.080 59.868 ;
      RECT 0.216 60.516 154.080 60.636 ;
      RECT 0.216 61.284 154.080 61.404 ;
      RECT 0.216 62.052 154.080 62.172 ;
      RECT 0.216 62.820 154.080 62.940 ;
      RECT 0.216 63.588 154.080 63.708 ;
      RECT 0.216 64.356 154.080 64.476 ;
      RECT 0.216 65.124 154.080 65.244 ;
      RECT 0.216 65.892 154.080 66.012 ;
      RECT 0.216 66.660 154.080 66.780 ;
      RECT 0.216 67.428 154.080 67.548 ;
      RECT 0.216 68.196 154.080 68.316 ;
      RECT 0.216 68.964 154.080 69.084 ;
      RECT 0.216 69.732 154.080 69.852 ;
      RECT 0.216 70.500 154.080 70.620 ;
      RECT 0.216 71.268 154.080 71.388 ;
      RECT 0.216 72.036 154.080 72.156 ;
      RECT 0.216 72.804 154.080 72.924 ;
      RECT 0.216 73.572 154.080 73.692 ;
      RECT 0.216 74.340 154.080 74.460 ;
      RECT 0.216 75.108 154.080 75.228 ;
      RECT 0.216 75.876 154.080 75.996 ;
      RECT 0.216 76.644 154.080 76.764 ;
      RECT 0.216 77.412 154.080 77.532 ;
      RECT 0.216 78.180 154.080 78.300 ;
      RECT 0.216 78.948 154.080 79.068 ;
      RECT 0.216 79.716 154.080 79.836 ;
      RECT 0.216 80.484 154.080 80.604 ;
      RECT 0.216 81.252 154.080 81.372 ;
      RECT 0.216 82.020 154.080 82.140 ;
      RECT 0.216 82.788 154.080 82.908 ;
      RECT 0.216 83.556 154.080 83.676 ;
      RECT 0.216 84.324 154.080 84.444 ;
      RECT 0.216 85.092 154.080 85.212 ;
      RECT 0.216 85.860 154.080 85.980 ;
      RECT 0.216 86.628 154.080 86.748 ;
      RECT 0.216 87.396 154.080 87.516 ;
      RECT 0.216 88.164 154.080 88.284 ;
      RECT 0.216 88.932 154.080 89.052 ;
      RECT 0.216 89.700 154.080 89.820 ;
      RECT 0.216 90.468 154.080 90.588 ;
      RECT 0.216 91.236 154.080 91.356 ;
      RECT 0.216 92.004 154.080 92.124 ;
      RECT 0.216 92.772 154.080 92.892 ;
      RECT 0.216 93.540 154.080 93.660 ;
      RECT 0.216 94.308 154.080 94.428 ;
      RECT 0.216 95.076 154.080 95.196 ;
      RECT 0.216 95.844 154.080 95.964 ;
      RECT 0.216 96.612 154.080 96.732 ;
      RECT 0.216 97.380 154.080 97.500 ;
      RECT 0.216 98.148 154.080 98.268 ;
      RECT 0.216 98.916 154.080 99.036 ;
      RECT 0.216 99.684 154.080 99.804 ;
      RECT 0.216 100.452 154.080 100.572 ;
      RECT 0.216 101.220 154.080 101.340 ;
      RECT 0.216 101.988 154.080 102.108 ;
      RECT 0.216 102.756 154.080 102.876 ;
      RECT 0.216 103.524 154.080 103.644 ;
      RECT 0.216 104.292 154.080 104.412 ;
      RECT 0.216 105.060 154.080 105.180 ;
      RECT 0.216 105.828 154.080 105.948 ;
      RECT 0.216 106.596 154.080 106.716 ;
      RECT 0.216 107.364 154.080 107.484 ;
      RECT 0.216 108.132 154.080 108.252 ;
      RECT 0.216 108.900 154.080 109.020 ;
      RECT 0.216 109.668 154.080 109.788 ;
      RECT 0.216 110.436 154.080 110.556 ;
      RECT 0.216 111.204 154.080 111.324 ;
      RECT 0.216 111.972 154.080 112.092 ;
      RECT 0.216 112.740 154.080 112.860 ;
      RECT 0.216 113.508 154.080 113.628 ;
      RECT 0.216 114.276 154.080 114.396 ;
      RECT 0.216 115.044 154.080 115.164 ;
      RECT 0.216 115.812 154.080 115.932 ;
      RECT 0.216 116.580 154.080 116.700 ;
      RECT 0.216 117.348 154.080 117.468 ;
      RECT 0.216 118.116 154.080 118.236 ;
      RECT 0.216 118.884 154.080 119.004 ;
      RECT 0.216 119.652 154.080 119.772 ;
      RECT 0.216 120.420 154.080 120.540 ;
      RECT 0.216 121.188 154.080 121.308 ;
      RECT 0.216 121.956 154.080 122.076 ;
      RECT 0.216 122.724 154.080 122.844 ;
      RECT 0.216 123.492 154.080 123.612 ;
      RECT 0.216 124.260 154.080 124.380 ;
      RECT 0.216 125.028 154.080 125.148 ;
      RECT 0.216 125.796 154.080 125.916 ;
      RECT 0.216 126.564 154.080 126.684 ;
      RECT 0.216 127.332 154.080 127.452 ;
      RECT 0.216 128.100 154.080 128.220 ;
      RECT 0.216 128.868 154.080 128.988 ;
      RECT 0.216 129.636 154.080 129.756 ;
      RECT 0.216 130.404 154.080 130.524 ;
      RECT 0.216 131.172 154.080 131.292 ;
      RECT 0.216 131.940 154.080 132.060 ;
      RECT 0.216 132.708 154.080 132.828 ;
      RECT 0.216 133.476 154.080 133.596 ;
      RECT 0.216 134.244 154.080 134.364 ;
      RECT 0.216 135.012 154.080 135.132 ;
      RECT 0.216 135.780 154.080 135.900 ;
      RECT 0.216 136.548 154.080 136.668 ;
      RECT 0.216 137.316 154.080 137.436 ;
      RECT 0.216 138.084 154.080 138.204 ;
      RECT 0.216 138.852 154.080 138.972 ;
      RECT 0.216 139.620 154.080 139.740 ;
      RECT 0.216 140.388 154.080 140.508 ;
      RECT 0.216 141.156 154.080 141.276 ;
      RECT 0.216 141.924 154.080 142.044 ;
      RECT 0.216 142.692 154.080 142.812 ;
      RECT 0.216 143.460 154.080 143.580 ;
      RECT 0.216 144.228 154.080 144.348 ;
      RECT 0.216 144.996 154.080 145.116 ;
      RECT 0.216 145.764 154.080 145.884 ;
      RECT 0.216 146.532 154.080 146.652 ;
      RECT 0.216 147.300 154.080 147.420 ;
      RECT 0.216 148.068 154.080 148.188 ;
      RECT 0.216 148.836 154.080 148.956 ;
      RECT 0.216 149.604 154.080 149.724 ;
      RECT 0.216 150.372 154.080 150.492 ;
      RECT 0.216 151.140 154.080 151.260 ;
      RECT 0.216 151.908 154.080 152.028 ;
      RECT 0.216 152.676 154.080 152.796 ;
      RECT 0.216 153.444 154.080 153.564 ;
      RECT 0.216 154.212 154.080 154.332 ;
      RECT 0.216 154.980 154.080 155.100 ;
      RECT 0.216 155.748 154.080 155.868 ;
      RECT 0.216 156.516 154.080 156.636 ;
      RECT 0.216 157.284 154.080 157.404 ;
      RECT 0.216 158.052 154.080 158.172 ;
      RECT 0.216 158.820 154.080 158.940 ;
      RECT 0.216 159.588 154.080 159.708 ;
      RECT 0.216 160.356 154.080 160.476 ;
      RECT 0.216 161.124 154.080 161.244 ;
      RECT 0.216 161.892 154.080 162.012 ;
      RECT 0.216 162.660 154.080 162.780 ;
      RECT 0.216 163.428 154.080 163.548 ;
      RECT 0.216 164.196 154.080 164.316 ;
      RECT 0.216 164.964 154.080 165.084 ;
      RECT 0.216 165.732 154.080 165.852 ;
      RECT 0.216 166.500 154.080 166.620 ;
      RECT 0.216 167.268 154.080 167.388 ;
      RECT 0.216 168.036 154.080 168.156 ;
      RECT 0.216 168.804 154.080 168.924 ;
      RECT 0.216 169.572 154.080 169.692 ;
      RECT 0.216 170.340 154.080 170.460 ;
      RECT 0.216 171.108 154.080 171.228 ;
      RECT 0.216 171.876 154.080 171.996 ;
      RECT 0.216 172.644 154.080 172.764 ;
      RECT 0.216 173.412 154.080 173.532 ;
      RECT 0.216 174.180 154.080 174.300 ;
      RECT 0.216 174.948 154.080 175.068 ;
      RECT 0.216 175.716 154.080 175.836 ;
      RECT 0.216 176.484 154.080 176.604 ;
      RECT 0.216 177.252 154.080 177.372 ;
      RECT 0.216 178.020 154.080 178.140 ;
      RECT 0.216 178.788 154.080 178.908 ;
      RECT 0.216 179.556 154.080 179.676 ;
      RECT 0.216 180.324 154.080 180.444 ;
      RECT 0.216 181.092 154.080 181.212 ;
      RECT 0.216 181.860 154.080 181.980 ;
      RECT 0.216 182.628 154.080 182.748 ;
      RECT 0.216 183.396 154.080 183.516 ;
      RECT 0.216 184.164 154.080 184.284 ;
      RECT 0.216 184.932 154.080 185.052 ;
      RECT 0.216 185.700 154.080 185.820 ;
      RECT 0.216 186.468 154.080 186.588 ;
      RECT 0.216 187.236 154.080 187.356 ;
      RECT 0.216 188.004 154.080 188.124 ;
      RECT 0.216 188.772 154.080 188.892 ;
      RECT 0.216 189.540 154.080 189.660 ;
      RECT 0.216 190.308 154.080 190.428 ;
      RECT 0.216 191.076 154.080 191.196 ;
      RECT 0.216 191.844 154.080 191.964 ;
      RECT 0.216 192.612 154.080 192.732 ;
      RECT 0.216 193.380 154.080 193.500 ;
      RECT 0.216 194.148 154.080 194.268 ;
      RECT 0.216 194.916 154.080 195.036 ;
      RECT 0.216 195.684 154.080 195.804 ;
      RECT 0.216 196.452 154.080 196.572 ;
      RECT 0.216 197.220 154.080 197.340 ;
      RECT 0.216 197.988 154.080 198.108 ;
      RECT 0.216 198.756 154.080 198.876 ;
      RECT 0.216 199.524 154.080 199.644 ;
      RECT 0.216 200.292 154.080 200.412 ;
      RECT 0.216 201.060 154.080 201.180 ;
      RECT 0.216 201.828 154.080 201.948 ;
      RECT 0.216 202.596 154.080 202.716 ;
      RECT 0.216 203.364 154.080 203.484 ;
      RECT 0.216 204.132 154.080 204.252 ;
      RECT 0.216 204.900 154.080 205.020 ;
      RECT 0.216 205.668 154.080 205.788 ;
      RECT 0.216 206.436 154.080 206.556 ;
      RECT 0.216 207.204 154.080 207.324 ;
      RECT 0.216 207.972 154.080 208.092 ;
      RECT 0.216 208.740 154.080 208.860 ;
      RECT 0.216 209.508 154.080 209.628 ;
      RECT 0.216 210.276 154.080 210.396 ;
      RECT 0.216 211.044 154.080 211.164 ;
      RECT 0.216 211.812 154.080 211.932 ;
      RECT 0.216 212.580 154.080 212.700 ;
      RECT 0.216 213.348 154.080 213.468 ;
      RECT 0.216 214.116 154.080 214.236 ;
      RECT 0.216 214.884 154.080 215.004 ;
      RECT 0.216 215.652 154.080 215.772 ;
      RECT 0.216 216.420 154.080 216.540 ;
      RECT 0.216 217.188 154.080 217.308 ;
      RECT 0.216 217.956 154.080 218.076 ;
      RECT 0.216 218.724 154.080 218.844 ;
      RECT 0.216 219.492 154.080 219.612 ;
      RECT 0.216 220.260 154.080 220.380 ;
      RECT 0.216 221.028 154.080 221.148 ;
      RECT 0.216 221.796 154.080 221.916 ;
      RECT 0.216 222.564 154.080 222.684 ;
      RECT 0.216 223.332 154.080 223.452 ;
      RECT 0.216 224.100 154.080 224.220 ;
      RECT 0.216 224.868 154.080 224.988 ;
      RECT 0.216 225.636 154.080 225.756 ;
      RECT 0.216 226.404 154.080 226.524 ;
      RECT 0.216 227.172 154.080 227.292 ;
      RECT 0.216 227.940 154.080 228.060 ;
      RECT 0.216 228.708 154.080 228.828 ;
      RECT 0.216 229.476 154.080 229.596 ;
      RECT 0.216 230.244 154.080 230.364 ;
      RECT 0.216 231.012 154.080 231.132 ;
      RECT 0.216 231.780 154.080 231.900 ;
      RECT 0.216 232.548 154.080 232.668 ;
      RECT 0.216 233.316 154.080 233.436 ;
      RECT 0.216 234.084 154.080 234.204 ;
      RECT 0.216 234.852 154.080 234.972 ;
      RECT 0.216 235.620 154.080 235.740 ;
      RECT 0.216 236.388 154.080 236.508 ;
      RECT 0.216 237.156 154.080 237.276 ;
      RECT 0.216 237.924 154.080 238.044 ;
      RECT 0.216 238.692 154.080 238.812 ;
      RECT 0.216 239.460 154.080 239.580 ;
      RECT 0.216 240.228 154.080 240.348 ;
      RECT 0.216 240.996 154.080 241.116 ;
      RECT 0.216 241.764 154.080 241.884 ;
      RECT 0.216 242.532 154.080 242.652 ;
      RECT 0.216 243.300 154.080 243.420 ;
      RECT 0.216 244.068 154.080 244.188 ;
      RECT 0.216 244.836 154.080 244.956 ;
      RECT 0.216 245.604 154.080 245.724 ;
      RECT 0.216 246.372 154.080 246.492 ;
      RECT 0.216 247.140 154.080 247.260 ;
      RECT 0.216 247.908 154.080 248.028 ;
      RECT 0.216 248.676 154.080 248.796 ;
      RECT 0.216 249.444 154.080 249.564 ;
      RECT 0.216 250.212 154.080 250.332 ;
      RECT 0.216 250.980 154.080 251.100 ;
      RECT 0.216 251.748 154.080 251.868 ;
      RECT 0.216 252.516 154.080 252.636 ;
      RECT 0.216 253.284 154.080 253.404 ;
      RECT 0.216 254.052 154.080 254.172 ;
      RECT 0.216 254.820 154.080 254.940 ;
      RECT 0.216 255.588 154.080 255.708 ;
      RECT 0.216 256.356 154.080 256.476 ;
      RECT 0.216 257.124 154.080 257.244 ;
      RECT 0.216 257.892 154.080 258.012 ;
      RECT 0.216 258.660 154.080 258.780 ;
      RECT 0.216 259.428 154.080 259.548 ;
      RECT 0.216 260.196 154.080 260.316 ;
      RECT 0.216 260.964 154.080 261.084 ;
      RECT 0.216 261.732 154.080 261.852 ;
      RECT 0.216 262.500 154.080 262.620 ;
      RECT 0.216 263.268 154.080 263.388 ;
      RECT 0.216 264.036 154.080 264.156 ;
      RECT 0.216 264.804 154.080 264.924 ;
      RECT 0.216 265.572 154.080 265.692 ;
      RECT 0.216 266.340 154.080 266.460 ;
      RECT 0.216 267.108 154.080 267.228 ;
      RECT 0.216 267.876 154.080 267.996 ;
      RECT 0.216 268.644 154.080 268.764 ;
      RECT 0.216 269.412 154.080 269.532 ;
      RECT 0.216 270.180 154.080 270.300 ;
      RECT 0.216 270.948 154.080 271.068 ;
      RECT 0.216 271.716 154.080 271.836 ;
      RECT 0.216 272.484 154.080 272.604 ;
      RECT 0.216 273.252 154.080 273.372 ;
      RECT 0.216 274.020 154.080 274.140 ;
      RECT 0.216 274.788 154.080 274.908 ;
      RECT 0.216 275.556 154.080 275.676 ;
      RECT 0.216 276.324 154.080 276.444 ;
      RECT 0.216 277.092 154.080 277.212 ;
      RECT 0.216 277.860 154.080 277.980 ;
      RECT 0.216 278.628 154.080 278.748 ;
      RECT 0.216 279.396 154.080 279.516 ;
      RECT 0.216 280.164 154.080 280.284 ;
      RECT 0.216 280.932 154.080 281.052 ;
      RECT 0.216 281.700 154.080 281.820 ;
      RECT 0.216 282.468 154.080 282.588 ;
      RECT 0.216 283.236 154.080 283.356 ;
      RECT 0.216 284.004 154.080 284.124 ;
      RECT 0.216 284.772 154.080 284.892 ;
      RECT 0.216 285.540 154.080 285.660 ;
      RECT 0.216 286.308 154.080 286.428 ;
      RECT 0.216 287.076 154.080 287.196 ;
      RECT 0.216 287.844 154.080 287.964 ;
      RECT 0.216 288.612 154.080 288.732 ;
      RECT 0.216 289.380 154.080 289.500 ;
      RECT 0.216 290.148 154.080 290.268 ;
      RECT 0.216 290.916 154.080 291.036 ;
      RECT 0.216 291.684 154.080 291.804 ;
      RECT 0.216 292.452 154.080 292.572 ;
      RECT 0.216 293.220 154.080 293.340 ;
      RECT 0.216 293.988 154.080 294.108 ;
      RECT 0.216 294.756 154.080 294.876 ;
      RECT 0.216 295.524 154.080 295.644 ;
      RECT 0.216 296.292 154.080 296.412 ;
      RECT 0.216 297.060 154.080 297.180 ;
      RECT 0.216 297.828 154.080 297.948 ;
      RECT 0.216 298.596 154.080 298.716 ;
      RECT 0.216 299.364 154.080 299.484 ;
      RECT 0.216 300.132 154.080 300.252 ;
      RECT 0.216 300.900 154.080 301.020 ;
      RECT 0.216 301.668 154.080 301.788 ;
      RECT 0.216 302.436 154.080 302.556 ;
      RECT 0.216 303.204 154.080 303.324 ;
      RECT 0.216 303.972 154.080 304.092 ;
      RECT 0.216 304.740 154.080 304.860 ;
      RECT 0.216 305.508 154.080 305.628 ;
      RECT 0.216 306.276 154.080 306.396 ;
      RECT 0.216 307.044 154.080 307.164 ;
      RECT 0.216 307.812 154.080 307.932 ;
      RECT 0.216 308.580 154.080 308.700 ;
      RECT 0.216 309.348 154.080 309.468 ;
      RECT 0.216 310.116 154.080 310.236 ;
      RECT 0.216 310.884 154.080 311.004 ;
      RECT 0.216 311.652 154.080 311.772 ;
      RECT 0.216 312.420 154.080 312.540 ;
      RECT 0.216 313.188 154.080 313.308 ;
      RECT 0.216 313.956 154.080 314.076 ;
      RECT 0.216 314.724 154.080 314.844 ;
      RECT 0.216 315.492 154.080 315.612 ;
      RECT 0.216 316.260 154.080 316.380 ;
      RECT 0.216 317.028 154.080 317.148 ;
      RECT 0.216 317.796 154.080 317.916 ;
      RECT 0.216 318.564 154.080 318.684 ;
      RECT 0.216 319.332 154.080 319.452 ;
      RECT 0.216 320.100 154.080 320.220 ;
      RECT 0.216 320.868 154.080 320.988 ;
      RECT 0.216 321.636 154.080 321.756 ;
      RECT 0.216 322.404 154.080 322.524 ;
      RECT 0.216 323.172 154.080 323.292 ;
      RECT 0.216 323.940 154.080 324.060 ;
      RECT 0.216 324.708 154.080 324.828 ;
      RECT 0.216 325.476 154.080 325.596 ;
      RECT 0.216 326.244 154.080 326.364 ;
      RECT 0.216 327.012 154.080 327.132 ;
      RECT 0.216 327.780 154.080 327.900 ;
      RECT 0.216 328.548 154.080 328.668 ;
      RECT 0.216 329.316 154.080 329.436 ;
      RECT 0.216 330.084 154.080 330.204 ;
      RECT 0.216 330.852 154.080 330.972 ;
      RECT 0.216 331.620 154.080 331.740 ;
      RECT 0.216 332.388 154.080 332.508 ;
      RECT 0.216 333.156 154.080 333.276 ;
      RECT 0.216 333.924 154.080 334.044 ;
      RECT 0.216 334.692 154.080 334.812 ;
      RECT 0.216 335.460 154.080 335.580 ;
      RECT 0.216 336.228 154.080 336.348 ;
      RECT 0.216 336.996 154.080 337.116 ;
      RECT 0.216 337.764 154.080 337.884 ;
      RECT 0.216 338.532 154.080 338.652 ;
      RECT 0.216 339.300 154.080 339.420 ;
      RECT 0.216 340.068 154.080 340.188 ;
      RECT 0.216 340.836 154.080 340.956 ;
      RECT 0.216 341.604 154.080 341.724 ;
      RECT 0.216 342.372 154.080 342.492 ;
      RECT 0.216 343.140 154.080 343.260 ;
      RECT 0.216 343.908 154.080 344.028 ;
      RECT 0.216 344.676 154.080 344.796 ;
      RECT 0.216 345.444 154.080 345.564 ;
      RECT 0.216 346.212 154.080 346.332 ;
      RECT 0.216 346.980 154.080 347.100 ;
      RECT 0.216 347.748 154.080 347.868 ;
      RECT 0.216 348.516 154.080 348.636 ;
      RECT 0.216 349.284 154.080 349.404 ;
      RECT 0.216 350.052 154.080 350.172 ;
      RECT 0.216 350.820 154.080 350.940 ;
      RECT 0.216 351.588 154.080 351.708 ;
      RECT 0.216 352.356 154.080 352.476 ;
      RECT 0.216 353.124 154.080 353.244 ;
      RECT 0.216 353.892 154.080 354.012 ;
      RECT 0.216 354.660 154.080 354.780 ;
      RECT 0.216 355.428 154.080 355.548 ;
      RECT 0.216 356.196 154.080 356.316 ;
      RECT 0.216 356.964 154.080 357.084 ;
      RECT 0.216 357.732 154.080 357.852 ;
      RECT 0.216 358.500 154.080 358.620 ;
      RECT 0.216 359.268 154.080 359.388 ;
      RECT 0.216 360.036 154.080 360.156 ;
      RECT 0.216 360.804 154.080 360.924 ;
      RECT 0.216 361.572 154.080 361.692 ;
      RECT 0.216 362.340 154.080 362.460 ;
      RECT 0.216 363.108 154.080 363.228 ;
      RECT 0.216 363.876 154.080 363.996 ;
      RECT 0.216 364.644 154.080 364.764 ;
      RECT 0.216 365.412 154.080 365.532 ;
      RECT 0.216 366.180 154.080 366.300 ;
      RECT 0.216 366.948 154.080 367.068 ;
      RECT 0.216 367.716 154.080 367.836 ;
      RECT 0.216 368.484 154.080 368.604 ;
      RECT 0.216 369.252 154.080 369.372 ;
      RECT 0.216 370.020 154.080 370.140 ;
      RECT 0.216 370.788 154.080 370.908 ;
      RECT 0.216 371.556 154.080 371.676 ;
      RECT 0.216 372.324 154.080 372.444 ;
      RECT 0.216 373.092 154.080 373.212 ;
      RECT 0.216 373.860 154.080 373.980 ;
      RECT 0.216 374.628 154.080 374.748 ;
      RECT 0.216 375.396 154.080 375.516 ;
      RECT 0.216 376.164 154.080 376.284 ;
      RECT 0.216 376.932 154.080 377.052 ;
      RECT 0.216 377.700 154.080 377.820 ;
      RECT 0.216 378.468 154.080 378.588 ;
      RECT 0.216 379.236 154.080 379.356 ;
      RECT 0.216 380.004 154.080 380.124 ;
      RECT 0.216 380.772 154.080 380.892 ;
      RECT 0.216 381.540 154.080 381.660 ;
      RECT 0.216 382.308 154.080 382.428 ;
      RECT 0.216 383.076 154.080 383.196 ;
      RECT 0.216 383.844 154.080 383.964 ;
      RECT 0.216 384.612 154.080 384.732 ;
      RECT 0.216 385.380 154.080 385.500 ;
    END
  END VDD
  OBS
    LAYER M1 ;
    RECT 0 0 154.296 385.830 ;
    LAYER M2 ;
    RECT 0 0 154.296 385.830 ;
    LAYER M3 ;
    RECT 0 0 154.296 385.830 ;
    LAYER M4 ;
    RECT 0 0 154.296 385.830 ;
  END
END ht_asap7_nyuzi_2048x512

END LIBRARY
